VERSION 5.8 ;
BUSBITCHARS "[]" ;
DIVIDERCHAR "/" ;
UNITS
    DATABASE MICRONS 1000 ;
END UNITS

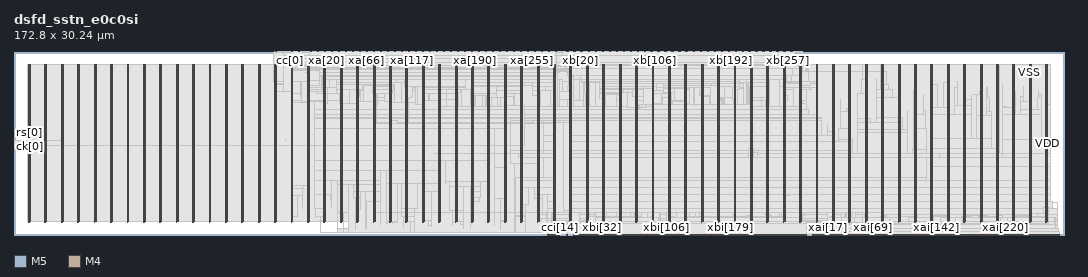
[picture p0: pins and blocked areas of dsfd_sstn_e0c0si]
MACRO dsfd_sstn_e0c0si
  FOREIGN dsfd_sstn_e0c0si 0 0 ;
  CLASS BLOCK ;
  SIZE 172.8 BY 30.24 ;
  PIN c0[0]
    DIRECTION INPUT ;
    USE SIGNAL ;
    PORT
      LAYER M5 ;
        RECT  44.208 30.156 44.232 30.24 ;
    END
  END c0[0]
  PIN c0[1]
    DIRECTION INPUT ;
    USE SIGNAL ;
    PORT
      LAYER M5 ;
        RECT  44.352 30.156 44.376 30.24 ;
    END
  END c0[1]
  PIN cc[0]
    DIRECTION OUTPUT ;
    USE SIGNAL ;
    PORT
      LAYER M5 ;
        RECT  45.456 30.156 45.48 30.24 ;
    END
  END cc[0]
  PIN cc[10]
    DIRECTION OUTPUT ;
    USE SIGNAL ;
    PORT
      LAYER M5 ;
        RECT  46.896 30.156 46.92 30.24 ;
    END
  END cc[10]
  PIN cc[11]
    DIRECTION OUTPUT ;
    USE SIGNAL ;
    PORT
      LAYER M5 ;
        RECT  47.04 30.156 47.064 30.24 ;
    END
  END cc[11]
  PIN cc[12]
    DIRECTION OUTPUT ;
    USE SIGNAL ;
    PORT
      LAYER M5 ;
        RECT  47.184 30.156 47.208 30.24 ;
    END
  END cc[12]
  PIN cc[13]
    DIRECTION OUTPUT ;
    USE SIGNAL ;
    PORT
      LAYER M5 ;
        RECT  47.328 30.156 47.352 30.24 ;
    END
  END cc[13]
  PIN cc[14]
    DIRECTION OUTPUT ;
    USE SIGNAL ;
    PORT
      LAYER M5 ;
        RECT  47.472 30.156 47.496 30.24 ;
    END
  END cc[14]
  PIN cc[1]
    DIRECTION OUTPUT ;
    USE SIGNAL ;
    PORT
      LAYER M5 ;
        RECT  45.6 30.156 45.624 30.24 ;
    END
  END cc[1]
  PIN cc[2]
    DIRECTION OUTPUT ;
    USE SIGNAL ;
    PORT
      LAYER M5 ;
        RECT  45.744 30.156 45.768 30.24 ;
    END
  END cc[2]
  PIN cc[3]
    DIRECTION OUTPUT ;
    USE SIGNAL ;
    PORT
      LAYER M5 ;
        RECT  45.888 30.156 45.912 30.24 ;
    END
  END cc[3]
  PIN cc[4]
    DIRECTION OUTPUT ;
    USE SIGNAL ;
    PORT
      LAYER M5 ;
        RECT  46.032 30.156 46.056 30.24 ;
    END
  END cc[4]
  PIN cc[5]
    DIRECTION OUTPUT ;
    USE SIGNAL ;
    PORT
      LAYER M5 ;
        RECT  46.176 30.156 46.2 30.24 ;
    END
  END cc[5]
  PIN cc[6]
    DIRECTION OUTPUT ;
    USE SIGNAL ;
    PORT
      LAYER M5 ;
        RECT  46.32 30.156 46.344 30.24 ;
    END
  END cc[6]
  PIN cc[7]
    DIRECTION OUTPUT ;
    USE SIGNAL ;
    PORT
      LAYER M5 ;
        RECT  46.464 30.156 46.488 30.24 ;
    END
  END cc[7]
  PIN cc[8]
    DIRECTION OUTPUT ;
    USE SIGNAL ;
    PORT
      LAYER M5 ;
        RECT  46.608 30.156 46.632 30.24 ;
    END
  END cc[8]
  PIN cc[9]
    DIRECTION OUTPUT ;
    USE SIGNAL ;
    PORT
      LAYER M5 ;
        RECT  46.752 30.156 46.776 30.24 ;
    END
  END cc[9]
  PIN cci[0]
    DIRECTION INPUT ;
    USE SIGNAL ;
    PORT
      LAYER M5 ;
        RECT  87.792 0 87.816 0.084 ;
    END
  END cci[0]
  PIN cci[10]
    DIRECTION INPUT ;
    USE SIGNAL ;
    PORT
      LAYER M5 ;
        RECT  89.232 0 89.256 0.084 ;
    END
  END cci[10]
  PIN cci[11]
    DIRECTION INPUT ;
    USE SIGNAL ;
    PORT
      LAYER M5 ;
        RECT  89.376 0 89.4 0.084 ;
    END
  END cci[11]
  PIN cci[12]
    DIRECTION INPUT ;
    USE SIGNAL ;
    PORT
      LAYER M5 ;
        RECT  89.52 0 89.544 0.084 ;
    END
  END cci[12]
  PIN cci[13]
    DIRECTION INPUT ;
    USE SIGNAL ;
    PORT
      LAYER M5 ;
        RECT  89.664 0 89.688 0.084 ;
    END
  END cci[13]
  PIN cci[14]
    DIRECTION INPUT ;
    USE SIGNAL ;
    PORT
      LAYER M5 ;
        RECT  89.808 0 89.832 0.084 ;
    END
  END cci[14]
  PIN cci[1]
    DIRECTION INPUT ;
    USE SIGNAL ;
    PORT
      LAYER M5 ;
        RECT  87.936 0 87.96 0.084 ;
    END
  END cci[1]
  PIN cci[2]
    DIRECTION INPUT ;
    USE SIGNAL ;
    PORT
      LAYER M5 ;
        RECT  88.08 0 88.104 0.084 ;
    END
  END cci[2]
  PIN cci[3]
    DIRECTION INPUT ;
    USE SIGNAL ;
    PORT
      LAYER M5 ;
        RECT  88.224 0 88.248 0.084 ;
    END
  END cci[3]
  PIN cci[4]
    DIRECTION INPUT ;
    USE SIGNAL ;
    PORT
      LAYER M5 ;
        RECT  88.368 0 88.392 0.084 ;
    END
  END cci[4]
  PIN cci[5]
    DIRECTION INPUT ;
    USE SIGNAL ;
    PORT
      LAYER M5 ;
        RECT  88.512 0 88.536 0.084 ;
    END
  END cci[5]
  PIN cci[6]
    DIRECTION INPUT ;
    USE SIGNAL ;
    PORT
      LAYER M5 ;
        RECT  88.656 0 88.68 0.084 ;
    END
  END cci[6]
  PIN cci[7]
    DIRECTION INPUT ;
    USE SIGNAL ;
    PORT
      LAYER M5 ;
        RECT  88.8 0 88.824 0.084 ;
    END
  END cci[7]
  PIN cci[8]
    DIRECTION INPUT ;
    USE SIGNAL ;
    PORT
      LAYER M5 ;
        RECT  88.944 0 88.968 0.084 ;
    END
  END cci[8]
  PIN cci[9]
    DIRECTION INPUT ;
    USE SIGNAL ;
    PORT
      LAYER M5 ;
        RECT  89.088 0 89.112 0.084 ;
    END
  END cci[9]
  PIN ck[0]
    DIRECTION INPUT ;
    USE SIGNAL ;
    PORT
      LAYER M4 ;
        RECT  0 14.592 0.084 14.616 ;
    END
    PORT
      LAYER M4 ;
        RECT  0.06 14.592 0.097 14.616 ;
    END
  END ck[0]
  PIN e0[0]
    DIRECTION INPUT ;
    USE SIGNAL ;
    PORT
      LAYER M5 ;
        RECT  42.96 30.156 42.984 30.24 ;
    END
  END e0[0]
  PIN e0[1]
    DIRECTION INPUT ;
    USE SIGNAL ;
    PORT
      LAYER M5 ;
        RECT  43.104 30.156 43.128 30.24 ;
    END
  END e0[1]
  PIN rs[0]
    DIRECTION INPUT ;
    USE SIGNAL ;
    PORT
      LAYER M4 ;
        RECT  0 15.6 0.084 15.624 ;
    END
    PORT
      LAYER M4 ;
        RECT  0.06 15.6 0.097 15.624 ;
    END
  END rs[0]
  PIN si[0]
    DIRECTION INPUT ;
    USE SIGNAL ;
    PORT
      LAYER M5 ;
        RECT  129.552 30.156 129.576 30.24 ;
    END
  END si[0]
  PIN si[1]
    DIRECTION INPUT ;
    USE SIGNAL ;
    PORT
      LAYER M5 ;
        RECT  129.696 30.156 129.72 30.24 ;
    END
  END si[1]
  PIN so[0]
    DIRECTION OUTPUT ;
    USE SIGNAL ;
    PORT
      LAYER M5 ;
        RECT  90.912 0 90.936 0.084 ;
    END
  END so[0]
  PIN so[1]
    DIRECTION OUTPUT ;
    USE SIGNAL ;
    PORT
      LAYER M5 ;
        RECT  91.056 0 91.08 0.084 ;
    END
  END so[1]
  PIN xa[0]
    DIRECTION OUTPUT ;
    USE SIGNAL ;
    PORT
      LAYER M5 ;
        RECT  48.576 30.156 48.6 30.24 ;
    END
  END xa[0]
  PIN xa[100]
    DIRECTION OUTPUT ;
    USE SIGNAL ;
    PORT
      LAYER M5 ;
        RECT  62.976 30.156 63 30.24 ;
    END
  END xa[100]
  PIN xa[101]
    DIRECTION OUTPUT ;
    USE SIGNAL ;
    PORT
      LAYER M5 ;
        RECT  63.12 30.156 63.144 30.24 ;
    END
  END xa[101]
  PIN xa[102]
    DIRECTION OUTPUT ;
    USE SIGNAL ;
    PORT
      LAYER M5 ;
        RECT  63.264 30.156 63.288 30.24 ;
    END
  END xa[102]
  PIN xa[103]
    DIRECTION OUTPUT ;
    USE SIGNAL ;
    PORT
      LAYER M5 ;
        RECT  63.408 30.156 63.432 30.24 ;
    END
  END xa[103]
  PIN xa[104]
    DIRECTION OUTPUT ;
    USE SIGNAL ;
    PORT
      LAYER M5 ;
        RECT  63.552 30.156 63.576 30.24 ;
    END
  END xa[104]
  PIN xa[105]
    DIRECTION OUTPUT ;
    USE SIGNAL ;
    PORT
      LAYER M5 ;
        RECT  63.696 30.156 63.72 30.24 ;
    END
  END xa[105]
  PIN xa[106]
    DIRECTION OUTPUT ;
    USE SIGNAL ;
    PORT
      LAYER M5 ;
        RECT  63.84 30.156 63.864 30.24 ;
    END
  END xa[106]
  PIN xa[107]
    DIRECTION OUTPUT ;
    USE SIGNAL ;
    PORT
      LAYER M5 ;
        RECT  63.984 30.156 64.008 30.24 ;
    END
  END xa[107]
  PIN xa[108]
    DIRECTION OUTPUT ;
    USE SIGNAL ;
    PORT
      LAYER M5 ;
        RECT  64.128 30.156 64.152 30.24 ;
    END
  END xa[108]
  PIN xa[109]
    DIRECTION OUTPUT ;
    USE SIGNAL ;
    PORT
      LAYER M5 ;
        RECT  64.272 30.156 64.296 30.24 ;
    END
  END xa[109]
  PIN xa[10]
    DIRECTION OUTPUT ;
    USE SIGNAL ;
    PORT
      LAYER M5 ;
        RECT  50.016 30.156 50.04 30.24 ;
    END
  END xa[10]
  PIN xa[110]
    DIRECTION OUTPUT ;
    USE SIGNAL ;
    PORT
      LAYER M5 ;
        RECT  64.416 30.156 64.44 30.24 ;
    END
  END xa[110]
  PIN xa[111]
    DIRECTION OUTPUT ;
    USE SIGNAL ;
    PORT
      LAYER M5 ;
        RECT  64.56 30.156 64.584 30.24 ;
    END
  END xa[111]
  PIN xa[112]
    DIRECTION OUTPUT ;
    USE SIGNAL ;
    PORT
      LAYER M5 ;
        RECT  64.704 30.156 64.728 30.24 ;
    END
  END xa[112]
  PIN xa[113]
    DIRECTION OUTPUT ;
    USE SIGNAL ;
    PORT
      LAYER M5 ;
        RECT  64.848 30.156 64.872 30.24 ;
    END
  END xa[113]
  PIN xa[114]
    DIRECTION OUTPUT ;
    USE SIGNAL ;
    PORT
      LAYER M5 ;
        RECT  64.992 30.156 65.016 30.24 ;
    END
  END xa[114]
  PIN xa[115]
    DIRECTION OUTPUT ;
    USE SIGNAL ;
    PORT
      LAYER M5 ;
        RECT  65.136 30.156 65.16 30.24 ;
    END
  END xa[115]
  PIN xa[116]
    DIRECTION OUTPUT ;
    USE SIGNAL ;
    PORT
      LAYER M5 ;
        RECT  65.28 30.156 65.304 30.24 ;
    END
  END xa[116]
  PIN xa[117]
    DIRECTION OUTPUT ;
    USE SIGNAL ;
    PORT
      LAYER M5 ;
        RECT  65.424 30.156 65.448 30.24 ;
    END
  END xa[117]
  PIN xa[118]
    DIRECTION OUTPUT ;
    USE SIGNAL ;
    PORT
      LAYER M5 ;
        RECT  65.568 30.156 65.592 30.24 ;
    END
  END xa[118]
  PIN xa[119]
    DIRECTION OUTPUT ;
    USE SIGNAL ;
    PORT
      LAYER M5 ;
        RECT  65.712 30.156 65.736 30.24 ;
    END
  END xa[119]
  PIN xa[11]
    DIRECTION OUTPUT ;
    USE SIGNAL ;
    PORT
      LAYER M5 ;
        RECT  50.16 30.156 50.184 30.24 ;
    END
  END xa[11]
  PIN xa[120]
    DIRECTION OUTPUT ;
    USE SIGNAL ;
    PORT
      LAYER M5 ;
        RECT  65.856 30.156 65.88 30.24 ;
    END
  END xa[120]
  PIN xa[121]
    DIRECTION OUTPUT ;
    USE SIGNAL ;
    PORT
      LAYER M5 ;
        RECT  66 30.156 66.024 30.24 ;
    END
  END xa[121]
  PIN xa[122]
    DIRECTION OUTPUT ;
    USE SIGNAL ;
    PORT
      LAYER M5 ;
        RECT  66.144 30.156 66.168 30.24 ;
    END
  END xa[122]
  PIN xa[123]
    DIRECTION OUTPUT ;
    USE SIGNAL ;
    PORT
      LAYER M5 ;
        RECT  66.288 30.156 66.312 30.24 ;
    END
  END xa[123]
  PIN xa[124]
    DIRECTION OUTPUT ;
    USE SIGNAL ;
    PORT
      LAYER M5 ;
        RECT  66.432 30.156 66.456 30.24 ;
    END
  END xa[124]
  PIN xa[125]
    DIRECTION OUTPUT ;
    USE SIGNAL ;
    PORT
      LAYER M5 ;
        RECT  66.576 30.156 66.6 30.24 ;
    END
  END xa[125]
  PIN xa[126]
    DIRECTION OUTPUT ;
    USE SIGNAL ;
    PORT
      LAYER M5 ;
        RECT  66.72 30.156 66.744 30.24 ;
    END
  END xa[126]
  PIN xa[127]
    DIRECTION OUTPUT ;
    USE SIGNAL ;
    PORT
      LAYER M5 ;
        RECT  66.864 30.156 66.888 30.24 ;
    END
  END xa[127]
  PIN xa[128]
    DIRECTION OUTPUT ;
    USE SIGNAL ;
    PORT
      LAYER M5 ;
        RECT  67.008 30.156 67.032 30.24 ;
    END
  END xa[128]
  PIN xa[129]
    DIRECTION OUTPUT ;
    USE SIGNAL ;
    PORT
      LAYER M5 ;
        RECT  67.152 30.156 67.176 30.24 ;
    END
  END xa[129]
  PIN xa[12]
    DIRECTION OUTPUT ;
    USE SIGNAL ;
    PORT
      LAYER M5 ;
        RECT  50.304 30.156 50.328 30.24 ;
    END
  END xa[12]
  PIN xa[130]
    DIRECTION OUTPUT ;
    USE SIGNAL ;
    PORT
      LAYER M5 ;
        RECT  67.296 30.156 67.32 30.24 ;
    END
  END xa[130]
  PIN xa[131]
    DIRECTION OUTPUT ;
    USE SIGNAL ;
    PORT
      LAYER M5 ;
        RECT  67.44 30.156 67.464 30.24 ;
    END
  END xa[131]
  PIN xa[132]
    DIRECTION OUTPUT ;
    USE SIGNAL ;
    PORT
      LAYER M5 ;
        RECT  67.584 30.156 67.608 30.24 ;
    END
  END xa[132]
  PIN xa[133]
    DIRECTION OUTPUT ;
    USE SIGNAL ;
    PORT
      LAYER M5 ;
        RECT  67.728 30.156 67.752 30.24 ;
    END
  END xa[133]
  PIN xa[134]
    DIRECTION OUTPUT ;
    USE SIGNAL ;
    PORT
      LAYER M5 ;
        RECT  67.872 30.156 67.896 30.24 ;
    END
  END xa[134]
  PIN xa[135]
    DIRECTION OUTPUT ;
    USE SIGNAL ;
    PORT
      LAYER M5 ;
        RECT  68.016 30.156 68.04 30.24 ;
    END
  END xa[135]
  PIN xa[136]
    DIRECTION OUTPUT ;
    USE SIGNAL ;
    PORT
      LAYER M5 ;
        RECT  68.16 30.156 68.184 30.24 ;
    END
  END xa[136]
  PIN xa[137]
    DIRECTION OUTPUT ;
    USE SIGNAL ;
    PORT
      LAYER M5 ;
        RECT  68.304 30.156 68.328 30.24 ;
    END
  END xa[137]
  PIN xa[138]
    DIRECTION OUTPUT ;
    USE SIGNAL ;
    PORT
      LAYER M5 ;
        RECT  68.448 30.156 68.472 30.24 ;
    END
  END xa[138]
  PIN xa[139]
    DIRECTION OUTPUT ;
    USE SIGNAL ;
    PORT
      LAYER M5 ;
        RECT  68.592 30.156 68.616 30.24 ;
    END
  END xa[139]
  PIN xa[13]
    DIRECTION OUTPUT ;
    USE SIGNAL ;
    PORT
      LAYER M5 ;
        RECT  50.448 30.156 50.472 30.24 ;
    END
  END xa[13]
  PIN xa[140]
    DIRECTION OUTPUT ;
    USE SIGNAL ;
    PORT
      LAYER M5 ;
        RECT  68.736 30.156 68.76 30.24 ;
    END
  END xa[140]
  PIN xa[141]
    DIRECTION OUTPUT ;
    USE SIGNAL ;
    PORT
      LAYER M5 ;
        RECT  68.88 30.156 68.904 30.24 ;
    END
  END xa[141]
  PIN xa[142]
    DIRECTION OUTPUT ;
    USE SIGNAL ;
    PORT
      LAYER M5 ;
        RECT  69.024 30.156 69.048 30.24 ;
    END
  END xa[142]
  PIN xa[143]
    DIRECTION OUTPUT ;
    USE SIGNAL ;
    PORT
      LAYER M5 ;
        RECT  69.168 30.156 69.192 30.24 ;
    END
  END xa[143]
  PIN xa[144]
    DIRECTION OUTPUT ;
    USE SIGNAL ;
    PORT
      LAYER M5 ;
        RECT  69.312 30.156 69.336 30.24 ;
    END
  END xa[144]
  PIN xa[145]
    DIRECTION OUTPUT ;
    USE SIGNAL ;
    PORT
      LAYER M5 ;
        RECT  69.456 30.156 69.48 30.24 ;
    END
  END xa[145]
  PIN xa[146]
    DIRECTION OUTPUT ;
    USE SIGNAL ;
    PORT
      LAYER M5 ;
        RECT  69.6 30.156 69.624 30.24 ;
    END
  END xa[146]
  PIN xa[147]
    DIRECTION OUTPUT ;
    USE SIGNAL ;
    PORT
      LAYER M5 ;
        RECT  69.744 30.156 69.768 30.24 ;
    END
  END xa[147]
  PIN xa[148]
    DIRECTION OUTPUT ;
    USE SIGNAL ;
    PORT
      LAYER M5 ;
        RECT  69.888 30.156 69.912 30.24 ;
    END
  END xa[148]
  PIN xa[149]
    DIRECTION OUTPUT ;
    USE SIGNAL ;
    PORT
      LAYER M5 ;
        RECT  70.032 30.156 70.056 30.24 ;
    END
  END xa[149]
  PIN xa[14]
    DIRECTION OUTPUT ;
    USE SIGNAL ;
    PORT
      LAYER M5 ;
        RECT  50.592 30.156 50.616 30.24 ;
    END
  END xa[14]
  PIN xa[150]
    DIRECTION OUTPUT ;
    USE SIGNAL ;
    PORT
      LAYER M5 ;
        RECT  70.176 30.156 70.2 30.24 ;
    END
  END xa[150]
  PIN xa[151]
    DIRECTION OUTPUT ;
    USE SIGNAL ;
    PORT
      LAYER M5 ;
        RECT  70.32 30.156 70.344 30.24 ;
    END
  END xa[151]
  PIN xa[152]
    DIRECTION OUTPUT ;
    USE SIGNAL ;
    PORT
      LAYER M5 ;
        RECT  70.464 30.156 70.488 30.24 ;
    END
  END xa[152]
  PIN xa[153]
    DIRECTION OUTPUT ;
    USE SIGNAL ;
    PORT
      LAYER M5 ;
        RECT  70.608 30.156 70.632 30.24 ;
    END
  END xa[153]
  PIN xa[154]
    DIRECTION OUTPUT ;
    USE SIGNAL ;
    PORT
      LAYER M5 ;
        RECT  70.752 30.156 70.776 30.24 ;
    END
  END xa[154]
  PIN xa[155]
    DIRECTION OUTPUT ;
    USE SIGNAL ;
    PORT
      LAYER M5 ;
        RECT  70.896 30.156 70.92 30.24 ;
    END
  END xa[155]
  PIN xa[156]
    DIRECTION OUTPUT ;
    USE SIGNAL ;
    PORT
      LAYER M5 ;
        RECT  71.04 30.156 71.064 30.24 ;
    END
  END xa[156]
  PIN xa[157]
    DIRECTION OUTPUT ;
    USE SIGNAL ;
    PORT
      LAYER M5 ;
        RECT  71.184 30.156 71.208 30.24 ;
    END
  END xa[157]
  PIN xa[158]
    DIRECTION OUTPUT ;
    USE SIGNAL ;
    PORT
      LAYER M5 ;
        RECT  71.328 30.156 71.352 30.24 ;
    END
  END xa[158]
  PIN xa[159]
    DIRECTION OUTPUT ;
    USE SIGNAL ;
    PORT
      LAYER M5 ;
        RECT  71.472 30.156 71.496 30.24 ;
    END
  END xa[159]
  PIN xa[15]
    DIRECTION OUTPUT ;
    USE SIGNAL ;
    PORT
      LAYER M5 ;
        RECT  50.736 30.156 50.76 30.24 ;
    END
  END xa[15]
  PIN xa[160]
    DIRECTION OUTPUT ;
    USE SIGNAL ;
    PORT
      LAYER M5 ;
        RECT  71.616 30.156 71.64 30.24 ;
    END
  END xa[160]
  PIN xa[161]
    DIRECTION OUTPUT ;
    USE SIGNAL ;
    PORT
      LAYER M5 ;
        RECT  71.76 30.156 71.784 30.24 ;
    END
  END xa[161]
  PIN xa[162]
    DIRECTION OUTPUT ;
    USE SIGNAL ;
    PORT
      LAYER M5 ;
        RECT  71.904 30.156 71.928 30.24 ;
    END
  END xa[162]
  PIN xa[163]
    DIRECTION OUTPUT ;
    USE SIGNAL ;
    PORT
      LAYER M5 ;
        RECT  72.048 30.156 72.072 30.24 ;
    END
  END xa[163]
  PIN xa[164]
    DIRECTION OUTPUT ;
    USE SIGNAL ;
    PORT
      LAYER M5 ;
        RECT  72.192 30.156 72.216 30.24 ;
    END
  END xa[164]
  PIN xa[165]
    DIRECTION OUTPUT ;
    USE SIGNAL ;
    PORT
      LAYER M5 ;
        RECT  72.336 30.156 72.36 30.24 ;
    END
  END xa[165]
  PIN xa[166]
    DIRECTION OUTPUT ;
    USE SIGNAL ;
    PORT
      LAYER M5 ;
        RECT  72.48 30.156 72.504 30.24 ;
    END
  END xa[166]
  PIN xa[167]
    DIRECTION OUTPUT ;
    USE SIGNAL ;
    PORT
      LAYER M5 ;
        RECT  72.624 30.156 72.648 30.24 ;
    END
  END xa[167]
  PIN xa[168]
    DIRECTION OUTPUT ;
    USE SIGNAL ;
    PORT
      LAYER M5 ;
        RECT  72.768 30.156 72.792 30.24 ;
    END
  END xa[168]
  PIN xa[169]
    DIRECTION OUTPUT ;
    USE SIGNAL ;
    PORT
      LAYER M5 ;
        RECT  72.912 30.156 72.936 30.24 ;
    END
  END xa[169]
  PIN xa[16]
    DIRECTION OUTPUT ;
    USE SIGNAL ;
    PORT
      LAYER M5 ;
        RECT  50.88 30.156 50.904 30.24 ;
    END
  END xa[16]
  PIN xa[170]
    DIRECTION OUTPUT ;
    USE SIGNAL ;
    PORT
      LAYER M5 ;
        RECT  73.056 30.156 73.08 30.24 ;
    END
  END xa[170]
  PIN xa[171]
    DIRECTION OUTPUT ;
    USE SIGNAL ;
    PORT
      LAYER M5 ;
        RECT  73.2 30.156 73.224 30.24 ;
    END
  END xa[171]
  PIN xa[172]
    DIRECTION OUTPUT ;
    USE SIGNAL ;
    PORT
      LAYER M5 ;
        RECT  73.344 30.156 73.368 30.24 ;
    END
  END xa[172]
  PIN xa[173]
    DIRECTION OUTPUT ;
    USE SIGNAL ;
    PORT
      LAYER M5 ;
        RECT  73.488 30.156 73.512 30.24 ;
    END
  END xa[173]
  PIN xa[174]
    DIRECTION OUTPUT ;
    USE SIGNAL ;
    PORT
      LAYER M5 ;
        RECT  73.632 30.156 73.656 30.24 ;
    END
  END xa[174]
  PIN xa[175]
    DIRECTION OUTPUT ;
    USE SIGNAL ;
    PORT
      LAYER M5 ;
        RECT  73.776 30.156 73.8 30.24 ;
    END
  END xa[175]
  PIN xa[176]
    DIRECTION OUTPUT ;
    USE SIGNAL ;
    PORT
      LAYER M5 ;
        RECT  73.92 30.156 73.944 30.24 ;
    END
  END xa[176]
  PIN xa[177]
    DIRECTION OUTPUT ;
    USE SIGNAL ;
    PORT
      LAYER M5 ;
        RECT  74.064 30.156 74.088 30.24 ;
    END
  END xa[177]
  PIN xa[178]
    DIRECTION OUTPUT ;
    USE SIGNAL ;
    PORT
      LAYER M5 ;
        RECT  74.208 30.156 74.232 30.24 ;
    END
  END xa[178]
  PIN xa[179]
    DIRECTION OUTPUT ;
    USE SIGNAL ;
    PORT
      LAYER M5 ;
        RECT  74.352 30.156 74.376 30.24 ;
    END
  END xa[179]
  PIN xa[17]
    DIRECTION OUTPUT ;
    USE SIGNAL ;
    PORT
      LAYER M5 ;
        RECT  51.024 30.156 51.048 30.24 ;
    END
  END xa[17]
  PIN xa[180]
    DIRECTION OUTPUT ;
    USE SIGNAL ;
    PORT
      LAYER M5 ;
        RECT  74.496 30.156 74.52 30.24 ;
    END
  END xa[180]
  PIN xa[181]
    DIRECTION OUTPUT ;
    USE SIGNAL ;
    PORT
      LAYER M5 ;
        RECT  74.64 30.156 74.664 30.24 ;
    END
  END xa[181]
  PIN xa[182]
    DIRECTION OUTPUT ;
    USE SIGNAL ;
    PORT
      LAYER M5 ;
        RECT  74.784 30.156 74.808 30.24 ;
    END
  END xa[182]
  PIN xa[183]
    DIRECTION OUTPUT ;
    USE SIGNAL ;
    PORT
      LAYER M5 ;
        RECT  74.928 30.156 74.952 30.24 ;
    END
  END xa[183]
  PIN xa[184]
    DIRECTION OUTPUT ;
    USE SIGNAL ;
    PORT
      LAYER M5 ;
        RECT  75.072 30.156 75.096 30.24 ;
    END
  END xa[184]
  PIN xa[185]
    DIRECTION OUTPUT ;
    USE SIGNAL ;
    PORT
      LAYER M5 ;
        RECT  75.216 30.156 75.24 30.24 ;
    END
  END xa[185]
  PIN xa[186]
    DIRECTION OUTPUT ;
    USE SIGNAL ;
    PORT
      LAYER M5 ;
        RECT  75.36 30.156 75.384 30.24 ;
    END
  END xa[186]
  PIN xa[187]
    DIRECTION OUTPUT ;
    USE SIGNAL ;
    PORT
      LAYER M5 ;
        RECT  75.504 30.156 75.528 30.24 ;
    END
  END xa[187]
  PIN xa[188]
    DIRECTION OUTPUT ;
    USE SIGNAL ;
    PORT
      LAYER M5 ;
        RECT  75.648 30.156 75.672 30.24 ;
    END
  END xa[188]
  PIN xa[189]
    DIRECTION OUTPUT ;
    USE SIGNAL ;
    PORT
      LAYER M5 ;
        RECT  75.792 30.156 75.816 30.24 ;
    END
  END xa[189]
  PIN xa[18]
    DIRECTION OUTPUT ;
    USE SIGNAL ;
    PORT
      LAYER M5 ;
        RECT  51.168 30.156 51.192 30.24 ;
    END
  END xa[18]
  PIN xa[190]
    DIRECTION OUTPUT ;
    USE SIGNAL ;
    PORT
      LAYER M5 ;
        RECT  75.936 30.156 75.96 30.24 ;
    END
  END xa[190]
  PIN xa[191]
    DIRECTION OUTPUT ;
    USE SIGNAL ;
    PORT
      LAYER M5 ;
        RECT  76.08 30.156 76.104 30.24 ;
    END
  END xa[191]
  PIN xa[192]
    DIRECTION OUTPUT ;
    USE SIGNAL ;
    PORT
      LAYER M5 ;
        RECT  76.224 30.156 76.248 30.24 ;
    END
  END xa[192]
  PIN xa[193]
    DIRECTION OUTPUT ;
    USE SIGNAL ;
    PORT
      LAYER M5 ;
        RECT  76.368 30.156 76.392 30.24 ;
    END
  END xa[193]
  PIN xa[194]
    DIRECTION OUTPUT ;
    USE SIGNAL ;
    PORT
      LAYER M5 ;
        RECT  76.512 30.156 76.536 30.24 ;
    END
  END xa[194]
  PIN xa[195]
    DIRECTION OUTPUT ;
    USE SIGNAL ;
    PORT
      LAYER M5 ;
        RECT  76.656 30.156 76.68 30.24 ;
    END
  END xa[195]
  PIN xa[196]
    DIRECTION OUTPUT ;
    USE SIGNAL ;
    PORT
      LAYER M5 ;
        RECT  76.8 30.156 76.824 30.24 ;
    END
  END xa[196]
  PIN xa[197]
    DIRECTION OUTPUT ;
    USE SIGNAL ;
    PORT
      LAYER M5 ;
        RECT  76.944 30.156 76.968 30.24 ;
    END
  END xa[197]
  PIN xa[198]
    DIRECTION OUTPUT ;
    USE SIGNAL ;
    PORT
      LAYER M5 ;
        RECT  77.088 30.156 77.112 30.24 ;
    END
  END xa[198]
  PIN xa[199]
    DIRECTION OUTPUT ;
    USE SIGNAL ;
    PORT
      LAYER M5 ;
        RECT  77.232 30.156 77.256 30.24 ;
    END
  END xa[199]
  PIN xa[19]
    DIRECTION OUTPUT ;
    USE SIGNAL ;
    PORT
      LAYER M5 ;
        RECT  51.312 30.156 51.336 30.24 ;
    END
  END xa[19]
  PIN xa[1]
    DIRECTION OUTPUT ;
    USE SIGNAL ;
    PORT
      LAYER M5 ;
        RECT  48.72 30.156 48.744 30.24 ;
    END
  END xa[1]
  PIN xa[200]
    DIRECTION OUTPUT ;
    USE SIGNAL ;
    PORT
      LAYER M5 ;
        RECT  77.376 30.156 77.4 30.24 ;
    END
  END xa[200]
  PIN xa[201]
    DIRECTION OUTPUT ;
    USE SIGNAL ;
    PORT
      LAYER M5 ;
        RECT  77.52 30.156 77.544 30.24 ;
    END
  END xa[201]
  PIN xa[202]
    DIRECTION OUTPUT ;
    USE SIGNAL ;
    PORT
      LAYER M5 ;
        RECT  77.664 30.156 77.688 30.24 ;
    END
  END xa[202]
  PIN xa[203]
    DIRECTION OUTPUT ;
    USE SIGNAL ;
    PORT
      LAYER M5 ;
        RECT  77.808 30.156 77.832 30.24 ;
    END
  END xa[203]
  PIN xa[204]
    DIRECTION OUTPUT ;
    USE SIGNAL ;
    PORT
      LAYER M5 ;
        RECT  77.952 30.156 77.976 30.24 ;
    END
  END xa[204]
  PIN xa[205]
    DIRECTION OUTPUT ;
    USE SIGNAL ;
    PORT
      LAYER M5 ;
        RECT  78.096 30.156 78.12 30.24 ;
    END
  END xa[205]
  PIN xa[206]
    DIRECTION OUTPUT ;
    USE SIGNAL ;
    PORT
      LAYER M5 ;
        RECT  78.24 30.156 78.264 30.24 ;
    END
  END xa[206]
  PIN xa[207]
    DIRECTION OUTPUT ;
    USE SIGNAL ;
    PORT
      LAYER M5 ;
        RECT  78.384 30.156 78.408 30.24 ;
    END
  END xa[207]
  PIN xa[208]
    DIRECTION OUTPUT ;
    USE SIGNAL ;
    PORT
      LAYER M5 ;
        RECT  78.528 30.156 78.552 30.24 ;
    END
  END xa[208]
  PIN xa[209]
    DIRECTION OUTPUT ;
    USE SIGNAL ;
    PORT
      LAYER M5 ;
        RECT  78.672 30.156 78.696 30.24 ;
    END
  END xa[209]
  PIN xa[20]
    DIRECTION OUTPUT ;
    USE SIGNAL ;
    PORT
      LAYER M5 ;
        RECT  51.456 30.156 51.48 30.24 ;
    END
  END xa[20]
  PIN xa[210]
    DIRECTION OUTPUT ;
    USE SIGNAL ;
    PORT
      LAYER M5 ;
        RECT  78.816 30.156 78.84 30.24 ;
    END
  END xa[210]
  PIN xa[211]
    DIRECTION OUTPUT ;
    USE SIGNAL ;
    PORT
      LAYER M5 ;
        RECT  78.96 30.156 78.984 30.24 ;
    END
  END xa[211]
  PIN xa[212]
    DIRECTION OUTPUT ;
    USE SIGNAL ;
    PORT
      LAYER M5 ;
        RECT  79.104 30.156 79.128 30.24 ;
    END
  END xa[212]
  PIN xa[213]
    DIRECTION OUTPUT ;
    USE SIGNAL ;
    PORT
      LAYER M5 ;
        RECT  79.248 30.156 79.272 30.24 ;
    END
  END xa[213]
  PIN xa[214]
    DIRECTION OUTPUT ;
    USE SIGNAL ;
    PORT
      LAYER M5 ;
        RECT  79.392 30.156 79.416 30.24 ;
    END
  END xa[214]
  PIN xa[215]
    DIRECTION OUTPUT ;
    USE SIGNAL ;
    PORT
      LAYER M5 ;
        RECT  79.536 30.156 79.56 30.24 ;
    END
  END xa[215]
  PIN xa[216]
    DIRECTION OUTPUT ;
    USE SIGNAL ;
    PORT
      LAYER M5 ;
        RECT  79.68 30.156 79.704 30.24 ;
    END
  END xa[216]
  PIN xa[217]
    DIRECTION OUTPUT ;
    USE SIGNAL ;
    PORT
      LAYER M5 ;
        RECT  79.824 30.156 79.848 30.24 ;
    END
  END xa[217]
  PIN xa[218]
    DIRECTION OUTPUT ;
    USE SIGNAL ;
    PORT
      LAYER M5 ;
        RECT  79.968 30.156 79.992 30.24 ;
    END
  END xa[218]
  PIN xa[219]
    DIRECTION OUTPUT ;
    USE SIGNAL ;
    PORT
      LAYER M5 ;
        RECT  80.112 30.156 80.136 30.24 ;
    END
  END xa[219]
  PIN xa[21]
    DIRECTION OUTPUT ;
    USE SIGNAL ;
    PORT
      LAYER M5 ;
        RECT  51.6 30.156 51.624 30.24 ;
    END
  END xa[21]
  PIN xa[220]
    DIRECTION OUTPUT ;
    USE SIGNAL ;
    PORT
      LAYER M5 ;
        RECT  80.256 30.156 80.28 30.24 ;
    END
  END xa[220]
  PIN xa[221]
    DIRECTION OUTPUT ;
    USE SIGNAL ;
    PORT
      LAYER M5 ;
        RECT  80.4 30.156 80.424 30.24 ;
    END
  END xa[221]
  PIN xa[222]
    DIRECTION OUTPUT ;
    USE SIGNAL ;
    PORT
      LAYER M5 ;
        RECT  80.544 30.156 80.568 30.24 ;
    END
  END xa[222]
  PIN xa[223]
    DIRECTION OUTPUT ;
    USE SIGNAL ;
    PORT
      LAYER M5 ;
        RECT  80.688 30.156 80.712 30.24 ;
    END
  END xa[223]
  PIN xa[224]
    DIRECTION OUTPUT ;
    USE SIGNAL ;
    PORT
      LAYER M5 ;
        RECT  80.832 30.156 80.856 30.24 ;
    END
  END xa[224]
  PIN xa[225]
    DIRECTION OUTPUT ;
    USE SIGNAL ;
    PORT
      LAYER M5 ;
        RECT  80.976 30.156 81 30.24 ;
    END
  END xa[225]
  PIN xa[226]
    DIRECTION OUTPUT ;
    USE SIGNAL ;
    PORT
      LAYER M5 ;
        RECT  81.12 30.156 81.144 30.24 ;
    END
  END xa[226]
  PIN xa[227]
    DIRECTION OUTPUT ;
    USE SIGNAL ;
    PORT
      LAYER M5 ;
        RECT  81.264 30.156 81.288 30.24 ;
    END
  END xa[227]
  PIN xa[228]
    DIRECTION OUTPUT ;
    USE SIGNAL ;
    PORT
      LAYER M5 ;
        RECT  81.408 30.156 81.432 30.24 ;
    END
  END xa[228]
  PIN xa[229]
    DIRECTION OUTPUT ;
    USE SIGNAL ;
    PORT
      LAYER M5 ;
        RECT  81.552 30.156 81.576 30.24 ;
    END
  END xa[229]
  PIN xa[22]
    DIRECTION OUTPUT ;
    USE SIGNAL ;
    PORT
      LAYER M5 ;
        RECT  51.744 30.156 51.768 30.24 ;
    END
  END xa[22]
  PIN xa[230]
    DIRECTION OUTPUT ;
    USE SIGNAL ;
    PORT
      LAYER M5 ;
        RECT  81.696 30.156 81.72 30.24 ;
    END
  END xa[230]
  PIN xa[231]
    DIRECTION OUTPUT ;
    USE SIGNAL ;
    PORT
      LAYER M5 ;
        RECT  81.84 30.156 81.864 30.24 ;
    END
  END xa[231]
  PIN xa[232]
    DIRECTION OUTPUT ;
    USE SIGNAL ;
    PORT
      LAYER M5 ;
        RECT  81.984 30.156 82.008 30.24 ;
    END
  END xa[232]
  PIN xa[233]
    DIRECTION OUTPUT ;
    USE SIGNAL ;
    PORT
      LAYER M5 ;
        RECT  82.128 30.156 82.152 30.24 ;
    END
  END xa[233]
  PIN xa[234]
    DIRECTION OUTPUT ;
    USE SIGNAL ;
    PORT
      LAYER M5 ;
        RECT  82.272 30.156 82.296 30.24 ;
    END
  END xa[234]
  PIN xa[235]
    DIRECTION OUTPUT ;
    USE SIGNAL ;
    PORT
      LAYER M5 ;
        RECT  82.416 30.156 82.44 30.24 ;
    END
  END xa[235]
  PIN xa[236]
    DIRECTION OUTPUT ;
    USE SIGNAL ;
    PORT
      LAYER M5 ;
        RECT  82.56 30.156 82.584 30.24 ;
    END
  END xa[236]
  PIN xa[237]
    DIRECTION OUTPUT ;
    USE SIGNAL ;
    PORT
      LAYER M5 ;
        RECT  82.704 30.156 82.728 30.24 ;
    END
  END xa[237]
  PIN xa[238]
    DIRECTION OUTPUT ;
    USE SIGNAL ;
    PORT
      LAYER M5 ;
        RECT  82.848 30.156 82.872 30.24 ;
    END
  END xa[238]
  PIN xa[239]
    DIRECTION OUTPUT ;
    USE SIGNAL ;
    PORT
      LAYER M5 ;
        RECT  82.992 30.156 83.016 30.24 ;
    END
  END xa[239]
  PIN xa[23]
    DIRECTION OUTPUT ;
    USE SIGNAL ;
    PORT
      LAYER M5 ;
        RECT  51.888 30.156 51.912 30.24 ;
    END
  END xa[23]
  PIN xa[240]
    DIRECTION OUTPUT ;
    USE SIGNAL ;
    PORT
      LAYER M5 ;
        RECT  83.136 30.156 83.16 30.24 ;
    END
  END xa[240]
  PIN xa[241]
    DIRECTION OUTPUT ;
    USE SIGNAL ;
    PORT
      LAYER M5 ;
        RECT  83.28 30.156 83.304 30.24 ;
    END
  END xa[241]
  PIN xa[242]
    DIRECTION OUTPUT ;
    USE SIGNAL ;
    PORT
      LAYER M5 ;
        RECT  83.424 30.156 83.448 30.24 ;
    END
  END xa[242]
  PIN xa[243]
    DIRECTION OUTPUT ;
    USE SIGNAL ;
    PORT
      LAYER M5 ;
        RECT  83.568 30.156 83.592 30.24 ;
    END
  END xa[243]
  PIN xa[244]
    DIRECTION OUTPUT ;
    USE SIGNAL ;
    PORT
      LAYER M5 ;
        RECT  83.712 30.156 83.736 30.24 ;
    END
  END xa[244]
  PIN xa[245]
    DIRECTION OUTPUT ;
    USE SIGNAL ;
    PORT
      LAYER M5 ;
        RECT  83.856 30.156 83.88 30.24 ;
    END
  END xa[245]
  PIN xa[246]
    DIRECTION OUTPUT ;
    USE SIGNAL ;
    PORT
      LAYER M5 ;
        RECT  84 30.156 84.024 30.24 ;
    END
  END xa[246]
  PIN xa[247]
    DIRECTION OUTPUT ;
    USE SIGNAL ;
    PORT
      LAYER M5 ;
        RECT  84.144 30.156 84.168 30.24 ;
    END
  END xa[247]
  PIN xa[248]
    DIRECTION OUTPUT ;
    USE SIGNAL ;
    PORT
      LAYER M5 ;
        RECT  84.288 30.156 84.312 30.24 ;
    END
  END xa[248]
  PIN xa[249]
    DIRECTION OUTPUT ;
    USE SIGNAL ;
    PORT
      LAYER M5 ;
        RECT  84.432 30.156 84.456 30.24 ;
    END
  END xa[249]
  PIN xa[24]
    DIRECTION OUTPUT ;
    USE SIGNAL ;
    PORT
      LAYER M5 ;
        RECT  52.032 30.156 52.056 30.24 ;
    END
  END xa[24]
  PIN xa[250]
    DIRECTION OUTPUT ;
    USE SIGNAL ;
    PORT
      LAYER M5 ;
        RECT  84.576 30.156 84.6 30.24 ;
    END
  END xa[250]
  PIN xa[251]
    DIRECTION OUTPUT ;
    USE SIGNAL ;
    PORT
      LAYER M5 ;
        RECT  84.72 30.156 84.744 30.24 ;
    END
  END xa[251]
  PIN xa[252]
    DIRECTION OUTPUT ;
    USE SIGNAL ;
    PORT
      LAYER M5 ;
        RECT  84.864 30.156 84.888 30.24 ;
    END
  END xa[252]
  PIN xa[253]
    DIRECTION OUTPUT ;
    USE SIGNAL ;
    PORT
      LAYER M5 ;
        RECT  85.008 30.156 85.032 30.24 ;
    END
  END xa[253]
  PIN xa[254]
    DIRECTION OUTPUT ;
    USE SIGNAL ;
    PORT
      LAYER M5 ;
        RECT  85.152 30.156 85.176 30.24 ;
    END
  END xa[254]
  PIN xa[255]
    DIRECTION OUTPUT ;
    USE SIGNAL ;
    PORT
      LAYER M5 ;
        RECT  85.296 30.156 85.32 30.24 ;
    END
  END xa[255]
  PIN xa[256]
    DIRECTION OUTPUT ;
    USE SIGNAL ;
    PORT
      LAYER M5 ;
        RECT  85.44 30.156 85.464 30.24 ;
    END
  END xa[256]
  PIN xa[257]
    DIRECTION OUTPUT ;
    USE SIGNAL ;
    PORT
      LAYER M5 ;
        RECT  85.584 30.156 85.608 30.24 ;
    END
  END xa[257]
  PIN xa[258]
    DIRECTION OUTPUT ;
    USE SIGNAL ;
    PORT
      LAYER M5 ;
        RECT  85.728 30.156 85.752 30.24 ;
    END
  END xa[258]
  PIN xa[259]
    DIRECTION OUTPUT ;
    USE SIGNAL ;
    PORT
      LAYER M5 ;
        RECT  85.872 30.156 85.896 30.24 ;
    END
  END xa[259]
  PIN xa[25]
    DIRECTION OUTPUT ;
    USE SIGNAL ;
    PORT
      LAYER M5 ;
        RECT  52.176 30.156 52.2 30.24 ;
    END
  END xa[25]
  PIN xa[260]
    DIRECTION OUTPUT ;
    USE SIGNAL ;
    PORT
      LAYER M5 ;
        RECT  86.016 30.156 86.04 30.24 ;
    END
  END xa[260]
  PIN xa[261]
    DIRECTION OUTPUT ;
    USE SIGNAL ;
    PORT
      LAYER M5 ;
        RECT  86.16 30.156 86.184 30.24 ;
    END
  END xa[261]
  PIN xa[262]
    DIRECTION OUTPUT ;
    USE SIGNAL ;
    PORT
      LAYER M5 ;
        RECT  86.304 30.156 86.328 30.24 ;
    END
  END xa[262]
  PIN xa[263]
    DIRECTION OUTPUT ;
    USE SIGNAL ;
    PORT
      LAYER M5 ;
        RECT  86.448 30.156 86.472 30.24 ;
    END
  END xa[263]
  PIN xa[264]
    DIRECTION OUTPUT ;
    USE SIGNAL ;
    PORT
      LAYER M5 ;
        RECT  86.592 30.156 86.616 30.24 ;
    END
  END xa[264]
  PIN xa[265]
    DIRECTION OUTPUT ;
    USE SIGNAL ;
    PORT
      LAYER M5 ;
        RECT  86.736 30.156 86.76 30.24 ;
    END
  END xa[265]
  PIN xa[266]
    DIRECTION OUTPUT ;
    USE SIGNAL ;
    PORT
      LAYER M5 ;
        RECT  86.88 30.156 86.904 30.24 ;
    END
  END xa[266]
  PIN xa[267]
    DIRECTION OUTPUT ;
    USE SIGNAL ;
    PORT
      LAYER M5 ;
        RECT  87.024 30.156 87.048 30.24 ;
    END
  END xa[267]
  PIN xa[268]
    DIRECTION OUTPUT ;
    USE SIGNAL ;
    PORT
      LAYER M5 ;
        RECT  87.168 30.156 87.192 30.24 ;
    END
  END xa[268]
  PIN xa[269]
    DIRECTION OUTPUT ;
    USE SIGNAL ;
    PORT
      LAYER M5 ;
        RECT  87.312 30.156 87.336 30.24 ;
    END
  END xa[269]
  PIN xa[26]
    DIRECTION OUTPUT ;
    USE SIGNAL ;
    PORT
      LAYER M5 ;
        RECT  52.32 30.156 52.344 30.24 ;
    END
  END xa[26]
  PIN xa[270]
    DIRECTION OUTPUT ;
    USE SIGNAL ;
    PORT
      LAYER M5 ;
        RECT  87.456 30.156 87.48 30.24 ;
    END
  END xa[270]
  PIN xa[271]
    DIRECTION OUTPUT ;
    USE SIGNAL ;
    PORT
      LAYER M5 ;
        RECT  87.6 30.156 87.624 30.24 ;
    END
  END xa[271]
  PIN xa[272]
    DIRECTION OUTPUT ;
    USE SIGNAL ;
    PORT
      LAYER M5 ;
        RECT  87.744 30.156 87.768 30.24 ;
    END
  END xa[272]
  PIN xa[273]
    DIRECTION OUTPUT ;
    USE SIGNAL ;
    PORT
      LAYER M5 ;
        RECT  87.888 30.156 87.912 30.24 ;
    END
  END xa[273]
  PIN xa[274]
    DIRECTION OUTPUT ;
    USE SIGNAL ;
    PORT
      LAYER M5 ;
        RECT  88.032 30.156 88.056 30.24 ;
    END
  END xa[274]
  PIN xa[275]
    DIRECTION OUTPUT ;
    USE SIGNAL ;
    PORT
      LAYER M5 ;
        RECT  88.176 30.156 88.2 30.24 ;
    END
  END xa[275]
  PIN xa[276]
    DIRECTION OUTPUT ;
    USE SIGNAL ;
    PORT
      LAYER M5 ;
        RECT  88.32 30.156 88.344 30.24 ;
    END
  END xa[276]
  PIN xa[277]
    DIRECTION OUTPUT ;
    USE SIGNAL ;
    PORT
      LAYER M5 ;
        RECT  88.464 30.156 88.488 30.24 ;
    END
  END xa[277]
  PIN xa[278]
    DIRECTION OUTPUT ;
    USE SIGNAL ;
    PORT
      LAYER M5 ;
        RECT  88.608 30.156 88.632 30.24 ;
    END
  END xa[278]
  PIN xa[279]
    DIRECTION OUTPUT ;
    USE SIGNAL ;
    PORT
      LAYER M5 ;
        RECT  88.752 30.156 88.776 30.24 ;
    END
  END xa[279]
  PIN xa[27]
    DIRECTION OUTPUT ;
    USE SIGNAL ;
    PORT
      LAYER M5 ;
        RECT  52.464 30.156 52.488 30.24 ;
    END
  END xa[27]
  PIN xa[280]
    DIRECTION OUTPUT ;
    USE SIGNAL ;
    PORT
      LAYER M5 ;
        RECT  88.896 30.156 88.92 30.24 ;
    END
  END xa[280]
  PIN xa[281]
    DIRECTION OUTPUT ;
    USE SIGNAL ;
    PORT
      LAYER M5 ;
        RECT  89.04 30.156 89.064 30.24 ;
    END
  END xa[281]
  PIN xa[282]
    DIRECTION OUTPUT ;
    USE SIGNAL ;
    PORT
      LAYER M5 ;
        RECT  89.184 30.156 89.208 30.24 ;
    END
  END xa[282]
  PIN xa[28]
    DIRECTION OUTPUT ;
    USE SIGNAL ;
    PORT
      LAYER M5 ;
        RECT  52.608 30.156 52.632 30.24 ;
    END
  END xa[28]
  PIN xa[29]
    DIRECTION OUTPUT ;
    USE SIGNAL ;
    PORT
      LAYER M5 ;
        RECT  52.752 30.156 52.776 30.24 ;
    END
  END xa[29]
  PIN xa[2]
    DIRECTION OUTPUT ;
    USE SIGNAL ;
    PORT
      LAYER M5 ;
        RECT  48.864 30.156 48.888 30.24 ;
    END
  END xa[2]
  PIN xa[30]
    DIRECTION OUTPUT ;
    USE SIGNAL ;
    PORT
      LAYER M5 ;
        RECT  52.896 30.156 52.92 30.24 ;
    END
  END xa[30]
  PIN xa[31]
    DIRECTION OUTPUT ;
    USE SIGNAL ;
    PORT
      LAYER M5 ;
        RECT  53.04 30.156 53.064 30.24 ;
    END
  END xa[31]
  PIN xa[32]
    DIRECTION OUTPUT ;
    USE SIGNAL ;
    PORT
      LAYER M5 ;
        RECT  53.184 30.156 53.208 30.24 ;
    END
  END xa[32]
  PIN xa[33]
    DIRECTION OUTPUT ;
    USE SIGNAL ;
    PORT
      LAYER M5 ;
        RECT  53.328 30.156 53.352 30.24 ;
    END
  END xa[33]
  PIN xa[34]
    DIRECTION OUTPUT ;
    USE SIGNAL ;
    PORT
      LAYER M5 ;
        RECT  53.472 30.156 53.496 30.24 ;
    END
  END xa[34]
  PIN xa[35]
    DIRECTION OUTPUT ;
    USE SIGNAL ;
    PORT
      LAYER M5 ;
        RECT  53.616 30.156 53.64 30.24 ;
    END
  END xa[35]
  PIN xa[36]
    DIRECTION OUTPUT ;
    USE SIGNAL ;
    PORT
      LAYER M5 ;
        RECT  53.76 30.156 53.784 30.24 ;
    END
  END xa[36]
  PIN xa[37]
    DIRECTION OUTPUT ;
    USE SIGNAL ;
    PORT
      LAYER M5 ;
        RECT  53.904 30.156 53.928 30.24 ;
    END
  END xa[37]
  PIN xa[38]
    DIRECTION OUTPUT ;
    USE SIGNAL ;
    PORT
      LAYER M5 ;
        RECT  54.048 30.156 54.072 30.24 ;
    END
  END xa[38]
  PIN xa[39]
    DIRECTION OUTPUT ;
    USE SIGNAL ;
    PORT
      LAYER M5 ;
        RECT  54.192 30.156 54.216 30.24 ;
    END
  END xa[39]
  PIN xa[3]
    DIRECTION OUTPUT ;
    USE SIGNAL ;
    PORT
      LAYER M5 ;
        RECT  49.008 30.156 49.032 30.24 ;
    END
  END xa[3]
  PIN xa[40]
    DIRECTION OUTPUT ;
    USE SIGNAL ;
    PORT
      LAYER M5 ;
        RECT  54.336 30.156 54.36 30.24 ;
    END
  END xa[40]
  PIN xa[41]
    DIRECTION OUTPUT ;
    USE SIGNAL ;
    PORT
      LAYER M5 ;
        RECT  54.48 30.156 54.504 30.24 ;
    END
  END xa[41]
  PIN xa[42]
    DIRECTION OUTPUT ;
    USE SIGNAL ;
    PORT
      LAYER M5 ;
        RECT  54.624 30.156 54.648 30.24 ;
    END
  END xa[42]
  PIN xa[43]
    DIRECTION OUTPUT ;
    USE SIGNAL ;
    PORT
      LAYER M5 ;
        RECT  54.768 30.156 54.792 30.24 ;
    END
  END xa[43]
  PIN xa[44]
    DIRECTION OUTPUT ;
    USE SIGNAL ;
    PORT
      LAYER M5 ;
        RECT  54.912 30.156 54.936 30.24 ;
    END
  END xa[44]
  PIN xa[45]
    DIRECTION OUTPUT ;
    USE SIGNAL ;
    PORT
      LAYER M5 ;
        RECT  55.056 30.156 55.08 30.24 ;
    END
  END xa[45]
  PIN xa[46]
    DIRECTION OUTPUT ;
    USE SIGNAL ;
    PORT
      LAYER M5 ;
        RECT  55.2 30.156 55.224 30.24 ;
    END
  END xa[46]
  PIN xa[47]
    DIRECTION OUTPUT ;
    USE SIGNAL ;
    PORT
      LAYER M5 ;
        RECT  55.344 30.156 55.368 30.24 ;
    END
  END xa[47]
  PIN xa[48]
    DIRECTION OUTPUT ;
    USE SIGNAL ;
    PORT
      LAYER M5 ;
        RECT  55.488 30.156 55.512 30.24 ;
    END
  END xa[48]
  PIN xa[49]
    DIRECTION OUTPUT ;
    USE SIGNAL ;
    PORT
      LAYER M5 ;
        RECT  55.632 30.156 55.656 30.24 ;
    END
  END xa[49]
  PIN xa[4]
    DIRECTION OUTPUT ;
    USE SIGNAL ;
    PORT
      LAYER M5 ;
        RECT  49.152 30.156 49.176 30.24 ;
    END
  END xa[4]
  PIN xa[50]
    DIRECTION OUTPUT ;
    USE SIGNAL ;
    PORT
      LAYER M5 ;
        RECT  55.776 30.156 55.8 30.24 ;
    END
  END xa[50]
  PIN xa[51]
    DIRECTION OUTPUT ;
    USE SIGNAL ;
    PORT
      LAYER M5 ;
        RECT  55.92 30.156 55.944 30.24 ;
    END
  END xa[51]
  PIN xa[52]
    DIRECTION OUTPUT ;
    USE SIGNAL ;
    PORT
      LAYER M5 ;
        RECT  56.064 30.156 56.088 30.24 ;
    END
  END xa[52]
  PIN xa[53]
    DIRECTION OUTPUT ;
    USE SIGNAL ;
    PORT
      LAYER M5 ;
        RECT  56.208 30.156 56.232 30.24 ;
    END
  END xa[53]
  PIN xa[54]
    DIRECTION OUTPUT ;
    USE SIGNAL ;
    PORT
      LAYER M5 ;
        RECT  56.352 30.156 56.376 30.24 ;
    END
  END xa[54]
  PIN xa[55]
    DIRECTION OUTPUT ;
    USE SIGNAL ;
    PORT
      LAYER M5 ;
        RECT  56.496 30.156 56.52 30.24 ;
    END
  END xa[55]
  PIN xa[56]
    DIRECTION OUTPUT ;
    USE SIGNAL ;
    PORT
      LAYER M5 ;
        RECT  56.64 30.156 56.664 30.24 ;
    END
  END xa[56]
  PIN xa[57]
    DIRECTION OUTPUT ;
    USE SIGNAL ;
    PORT
      LAYER M5 ;
        RECT  56.784 30.156 56.808 30.24 ;
    END
  END xa[57]
  PIN xa[58]
    DIRECTION OUTPUT ;
    USE SIGNAL ;
    PORT
      LAYER M5 ;
        RECT  56.928 30.156 56.952 30.24 ;
    END
  END xa[58]
  PIN xa[59]
    DIRECTION OUTPUT ;
    USE SIGNAL ;
    PORT
      LAYER M5 ;
        RECT  57.072 30.156 57.096 30.24 ;
    END
  END xa[59]
  PIN xa[5]
    DIRECTION OUTPUT ;
    USE SIGNAL ;
    PORT
      LAYER M5 ;
        RECT  49.296 30.156 49.32 30.24 ;
    END
  END xa[5]
  PIN xa[60]
    DIRECTION OUTPUT ;
    USE SIGNAL ;
    PORT
      LAYER M5 ;
        RECT  57.216 30.156 57.24 30.24 ;
    END
  END xa[60]
  PIN xa[61]
    DIRECTION OUTPUT ;
    USE SIGNAL ;
    PORT
      LAYER M5 ;
        RECT  57.36 30.156 57.384 30.24 ;
    END
  END xa[61]
  PIN xa[62]
    DIRECTION OUTPUT ;
    USE SIGNAL ;
    PORT
      LAYER M5 ;
        RECT  57.504 30.156 57.528 30.24 ;
    END
  END xa[62]
  PIN xa[63]
    DIRECTION OUTPUT ;
    USE SIGNAL ;
    PORT
      LAYER M5 ;
        RECT  57.648 30.156 57.672 30.24 ;
    END
  END xa[63]
  PIN xa[64]
    DIRECTION OUTPUT ;
    USE SIGNAL ;
    PORT
      LAYER M5 ;
        RECT  57.792 30.156 57.816 30.24 ;
    END
  END xa[64]
  PIN xa[65]
    DIRECTION OUTPUT ;
    USE SIGNAL ;
    PORT
      LAYER M5 ;
        RECT  57.936 30.156 57.96 30.24 ;
    END
  END xa[65]
  PIN xa[66]
    DIRECTION OUTPUT ;
    USE SIGNAL ;
    PORT
      LAYER M5 ;
        RECT  58.08 30.156 58.104 30.24 ;
    END
  END xa[66]
  PIN xa[67]
    DIRECTION OUTPUT ;
    USE SIGNAL ;
    PORT
      LAYER M5 ;
        RECT  58.224 30.156 58.248 30.24 ;
    END
  END xa[67]
  PIN xa[68]
    DIRECTION OUTPUT ;
    USE SIGNAL ;
    PORT
      LAYER M5 ;
        RECT  58.368 30.156 58.392 30.24 ;
    END
  END xa[68]
  PIN xa[69]
    DIRECTION OUTPUT ;
    USE SIGNAL ;
    PORT
      LAYER M5 ;
        RECT  58.512 30.156 58.536 30.24 ;
    END
  END xa[69]
  PIN xa[6]
    DIRECTION OUTPUT ;
    USE SIGNAL ;
    PORT
      LAYER M5 ;
        RECT  49.44 30.156 49.464 30.24 ;
    END
  END xa[6]
  PIN xa[70]
    DIRECTION OUTPUT ;
    USE SIGNAL ;
    PORT
      LAYER M5 ;
        RECT  58.656 30.156 58.68 30.24 ;
    END
  END xa[70]
  PIN xa[71]
    DIRECTION OUTPUT ;
    USE SIGNAL ;
    PORT
      LAYER M5 ;
        RECT  58.8 30.156 58.824 30.24 ;
    END
  END xa[71]
  PIN xa[72]
    DIRECTION OUTPUT ;
    USE SIGNAL ;
    PORT
      LAYER M5 ;
        RECT  58.944 30.156 58.968 30.24 ;
    END
  END xa[72]
  PIN xa[73]
    DIRECTION OUTPUT ;
    USE SIGNAL ;
    PORT
      LAYER M5 ;
        RECT  59.088 30.156 59.112 30.24 ;
    END
  END xa[73]
  PIN xa[74]
    DIRECTION OUTPUT ;
    USE SIGNAL ;
    PORT
      LAYER M5 ;
        RECT  59.232 30.156 59.256 30.24 ;
    END
  END xa[74]
  PIN xa[75]
    DIRECTION OUTPUT ;
    USE SIGNAL ;
    PORT
      LAYER M5 ;
        RECT  59.376 30.156 59.4 30.24 ;
    END
  END xa[75]
  PIN xa[76]
    DIRECTION OUTPUT ;
    USE SIGNAL ;
    PORT
      LAYER M5 ;
        RECT  59.52 30.156 59.544 30.24 ;
    END
  END xa[76]
  PIN xa[77]
    DIRECTION OUTPUT ;
    USE SIGNAL ;
    PORT
      LAYER M5 ;
        RECT  59.664 30.156 59.688 30.24 ;
    END
  END xa[77]
  PIN xa[78]
    DIRECTION OUTPUT ;
    USE SIGNAL ;
    PORT
      LAYER M5 ;
        RECT  59.808 30.156 59.832 30.24 ;
    END
  END xa[78]
  PIN xa[79]
    DIRECTION OUTPUT ;
    USE SIGNAL ;
    PORT
      LAYER M5 ;
        RECT  59.952 30.156 59.976 30.24 ;
    END
  END xa[79]
  PIN xa[7]
    DIRECTION OUTPUT ;
    USE SIGNAL ;
    PORT
      LAYER M5 ;
        RECT  49.584 30.156 49.608 30.24 ;
    END
  END xa[7]
  PIN xa[80]
    DIRECTION OUTPUT ;
    USE SIGNAL ;
    PORT
      LAYER M5 ;
        RECT  60.096 30.156 60.12 30.24 ;
    END
  END xa[80]
  PIN xa[81]
    DIRECTION OUTPUT ;
    USE SIGNAL ;
    PORT
      LAYER M5 ;
        RECT  60.24 30.156 60.264 30.24 ;
    END
  END xa[81]
  PIN xa[82]
    DIRECTION OUTPUT ;
    USE SIGNAL ;
    PORT
      LAYER M5 ;
        RECT  60.384 30.156 60.408 30.24 ;
    END
  END xa[82]
  PIN xa[83]
    DIRECTION OUTPUT ;
    USE SIGNAL ;
    PORT
      LAYER M5 ;
        RECT  60.528 30.156 60.552 30.24 ;
    END
  END xa[83]
  PIN xa[84]
    DIRECTION OUTPUT ;
    USE SIGNAL ;
    PORT
      LAYER M5 ;
        RECT  60.672 30.156 60.696 30.24 ;
    END
  END xa[84]
  PIN xa[85]
    DIRECTION OUTPUT ;
    USE SIGNAL ;
    PORT
      LAYER M5 ;
        RECT  60.816 30.156 60.84 30.24 ;
    END
  END xa[85]
  PIN xa[86]
    DIRECTION OUTPUT ;
    USE SIGNAL ;
    PORT
      LAYER M5 ;
        RECT  60.96 30.156 60.984 30.24 ;
    END
  END xa[86]
  PIN xa[87]
    DIRECTION OUTPUT ;
    USE SIGNAL ;
    PORT
      LAYER M5 ;
        RECT  61.104 30.156 61.128 30.24 ;
    END
  END xa[87]
  PIN xa[88]
    DIRECTION OUTPUT ;
    USE SIGNAL ;
    PORT
      LAYER M5 ;
        RECT  61.248 30.156 61.272 30.24 ;
    END
  END xa[88]
  PIN xa[89]
    DIRECTION OUTPUT ;
    USE SIGNAL ;
    PORT
      LAYER M5 ;
        RECT  61.392 30.156 61.416 30.24 ;
    END
  END xa[89]
  PIN xa[8]
    DIRECTION OUTPUT ;
    USE SIGNAL ;
    PORT
      LAYER M5 ;
        RECT  49.728 30.156 49.752 30.24 ;
    END
  END xa[8]
  PIN xa[90]
    DIRECTION OUTPUT ;
    USE SIGNAL ;
    PORT
      LAYER M5 ;
        RECT  61.536 30.156 61.56 30.24 ;
    END
  END xa[90]
  PIN xa[91]
    DIRECTION OUTPUT ;
    USE SIGNAL ;
    PORT
      LAYER M5 ;
        RECT  61.68 30.156 61.704 30.24 ;
    END
  END xa[91]
  PIN xa[92]
    DIRECTION OUTPUT ;
    USE SIGNAL ;
    PORT
      LAYER M5 ;
        RECT  61.824 30.156 61.848 30.24 ;
    END
  END xa[92]
  PIN xa[93]
    DIRECTION OUTPUT ;
    USE SIGNAL ;
    PORT
      LAYER M5 ;
        RECT  61.968 30.156 61.992 30.24 ;
    END
  END xa[93]
  PIN xa[94]
    DIRECTION OUTPUT ;
    USE SIGNAL ;
    PORT
      LAYER M5 ;
        RECT  62.112 30.156 62.136 30.24 ;
    END
  END xa[94]
  PIN xa[95]
    DIRECTION OUTPUT ;
    USE SIGNAL ;
    PORT
      LAYER M5 ;
        RECT  62.256 30.156 62.28 30.24 ;
    END
  END xa[95]
  PIN xa[96]
    DIRECTION OUTPUT ;
    USE SIGNAL ;
    PORT
      LAYER M5 ;
        RECT  62.4 30.156 62.424 30.24 ;
    END
  END xa[96]
  PIN xa[97]
    DIRECTION OUTPUT ;
    USE SIGNAL ;
    PORT
      LAYER M5 ;
        RECT  62.544 30.156 62.568 30.24 ;
    END
  END xa[97]
  PIN xa[98]
    DIRECTION OUTPUT ;
    USE SIGNAL ;
    PORT
      LAYER M5 ;
        RECT  62.688 30.156 62.712 30.24 ;
    END
  END xa[98]
  PIN xa[99]
    DIRECTION OUTPUT ;
    USE SIGNAL ;
    PORT
      LAYER M5 ;
        RECT  62.832 30.156 62.856 30.24 ;
    END
  END xa[99]
  PIN xa[9]
    DIRECTION OUTPUT ;
    USE SIGNAL ;
    PORT
      LAYER M5 ;
        RECT  49.872 30.156 49.896 30.24 ;
    END
  END xa[9]
  PIN xai[0]
    DIRECTION INPUT ;
    USE SIGNAL ;
    PORT
      LAYER M5 ;
        RECT  131.424 0 131.448 0.084 ;
    END
  END xai[0]
  PIN xai[100]
    DIRECTION INPUT ;
    USE SIGNAL ;
    PORT
      LAYER M5 ;
        RECT  145.824 0 145.848 0.084 ;
    END
  END xai[100]
  PIN xai[101]
    DIRECTION INPUT ;
    USE SIGNAL ;
    PORT
      LAYER M5 ;
        RECT  145.968 0 145.992 0.084 ;
    END
  END xai[101]
  PIN xai[102]
    DIRECTION INPUT ;
    USE SIGNAL ;
    PORT
      LAYER M5 ;
        RECT  146.112 0 146.136 0.084 ;
    END
  END xai[102]
  PIN xai[103]
    DIRECTION INPUT ;
    USE SIGNAL ;
    PORT
      LAYER M5 ;
        RECT  146.256 0 146.28 0.084 ;
    END
  END xai[103]
  PIN xai[104]
    DIRECTION INPUT ;
    USE SIGNAL ;
    PORT
      LAYER M5 ;
        RECT  146.4 0 146.424 0.084 ;
    END
  END xai[104]
  PIN xai[105]
    DIRECTION INPUT ;
    USE SIGNAL ;
    PORT
      LAYER M5 ;
        RECT  146.544 0 146.568 0.084 ;
    END
  END xai[105]
  PIN xai[106]
    DIRECTION INPUT ;
    USE SIGNAL ;
    PORT
      LAYER M5 ;
        RECT  146.688 0 146.712 0.084 ;
    END
  END xai[106]
  PIN xai[107]
    DIRECTION INPUT ;
    USE SIGNAL ;
    PORT
      LAYER M5 ;
        RECT  146.832 0 146.856 0.084 ;
    END
  END xai[107]
  PIN xai[108]
    DIRECTION INPUT ;
    USE SIGNAL ;
    PORT
      LAYER M5 ;
        RECT  146.976 0 147 0.084 ;
    END
  END xai[108]
  PIN xai[109]
    DIRECTION INPUT ;
    USE SIGNAL ;
    PORT
      LAYER M5 ;
        RECT  147.12 0 147.144 0.084 ;
    END
  END xai[109]
  PIN xai[10]
    DIRECTION INPUT ;
    USE SIGNAL ;
    PORT
      LAYER M5 ;
        RECT  132.864 0 132.888 0.084 ;
    END
  END xai[10]
  PIN xai[110]
    DIRECTION INPUT ;
    USE SIGNAL ;
    PORT
      LAYER M5 ;
        RECT  147.264 0 147.288 0.084 ;
    END
  END xai[110]
  PIN xai[111]
    DIRECTION INPUT ;
    USE SIGNAL ;
    PORT
      LAYER M5 ;
        RECT  147.408 0 147.432 0.084 ;
    END
  END xai[111]
  PIN xai[112]
    DIRECTION INPUT ;
    USE SIGNAL ;
    PORT
      LAYER M5 ;
        RECT  147.552 0 147.576 0.084 ;
    END
  END xai[112]
  PIN xai[113]
    DIRECTION INPUT ;
    USE SIGNAL ;
    PORT
      LAYER M5 ;
        RECT  147.696 0 147.72 0.084 ;
    END
  END xai[113]
  PIN xai[114]
    DIRECTION INPUT ;
    USE SIGNAL ;
    PORT
      LAYER M5 ;
        RECT  147.84 0 147.864 0.084 ;
    END
  END xai[114]
  PIN xai[115]
    DIRECTION INPUT ;
    USE SIGNAL ;
    PORT
      LAYER M5 ;
        RECT  147.984 0 148.008 0.084 ;
    END
  END xai[115]
  PIN xai[116]
    DIRECTION INPUT ;
    USE SIGNAL ;
    PORT
      LAYER M5 ;
        RECT  148.128 0 148.152 0.084 ;
    END
  END xai[116]
  PIN xai[117]
    DIRECTION INPUT ;
    USE SIGNAL ;
    PORT
      LAYER M5 ;
        RECT  148.272 0 148.296 0.084 ;
    END
  END xai[117]
  PIN xai[118]
    DIRECTION INPUT ;
    USE SIGNAL ;
    PORT
      LAYER M5 ;
        RECT  148.416 0 148.44 0.084 ;
    END
  END xai[118]
  PIN xai[119]
    DIRECTION INPUT ;
    USE SIGNAL ;
    PORT
      LAYER M5 ;
        RECT  148.56 0 148.584 0.084 ;
    END
  END xai[119]
  PIN xai[11]
    DIRECTION INPUT ;
    USE SIGNAL ;
    PORT
      LAYER M5 ;
        RECT  133.008 0 133.032 0.084 ;
    END
  END xai[11]
  PIN xai[120]
    DIRECTION INPUT ;
    USE SIGNAL ;
    PORT
      LAYER M5 ;
        RECT  148.704 0 148.728 0.084 ;
    END
  END xai[120]
  PIN xai[121]
    DIRECTION INPUT ;
    USE SIGNAL ;
    PORT
      LAYER M5 ;
        RECT  148.848 0 148.872 0.084 ;
    END
  END xai[121]
  PIN xai[122]
    DIRECTION INPUT ;
    USE SIGNAL ;
    PORT
      LAYER M5 ;
        RECT  148.992 0 149.016 0.084 ;
    END
  END xai[122]
  PIN xai[123]
    DIRECTION INPUT ;
    USE SIGNAL ;
    PORT
      LAYER M5 ;
        RECT  149.136 0 149.16 0.084 ;
    END
  END xai[123]
  PIN xai[124]
    DIRECTION INPUT ;
    USE SIGNAL ;
    PORT
      LAYER M5 ;
        RECT  149.28 0 149.304 0.084 ;
    END
  END xai[124]
  PIN xai[125]
    DIRECTION INPUT ;
    USE SIGNAL ;
    PORT
      LAYER M5 ;
        RECT  149.424 0 149.448 0.084 ;
    END
  END xai[125]
  PIN xai[126]
    DIRECTION INPUT ;
    USE SIGNAL ;
    PORT
      LAYER M5 ;
        RECT  149.568 0 149.592 0.084 ;
    END
  END xai[126]
  PIN xai[127]
    DIRECTION INPUT ;
    USE SIGNAL ;
    PORT
      LAYER M5 ;
        RECT  149.712 0 149.736 0.084 ;
    END
  END xai[127]
  PIN xai[128]
    DIRECTION INPUT ;
    USE SIGNAL ;
    PORT
      LAYER M5 ;
        RECT  149.856 0 149.88 0.084 ;
    END
  END xai[128]
  PIN xai[129]
    DIRECTION INPUT ;
    USE SIGNAL ;
    PORT
      LAYER M5 ;
        RECT  150 0 150.024 0.084 ;
    END
  END xai[129]
  PIN xai[12]
    DIRECTION INPUT ;
    USE SIGNAL ;
    PORT
      LAYER M5 ;
        RECT  133.152 0 133.176 0.084 ;
    END
  END xai[12]
  PIN xai[130]
    DIRECTION INPUT ;
    USE SIGNAL ;
    PORT
      LAYER M5 ;
        RECT  150.144 0 150.168 0.084 ;
    END
  END xai[130]
  PIN xai[131]
    DIRECTION INPUT ;
    USE SIGNAL ;
    PORT
      LAYER M5 ;
        RECT  150.288 0 150.312 0.084 ;
    END
  END xai[131]
  PIN xai[132]
    DIRECTION INPUT ;
    USE SIGNAL ;
    PORT
      LAYER M5 ;
        RECT  150.432 0 150.456 0.084 ;
    END
  END xai[132]
  PIN xai[133]
    DIRECTION INPUT ;
    USE SIGNAL ;
    PORT
      LAYER M5 ;
        RECT  150.576 0 150.6 0.084 ;
    END
  END xai[133]
  PIN xai[134]
    DIRECTION INPUT ;
    USE SIGNAL ;
    PORT
      LAYER M5 ;
        RECT  150.72 0 150.744 0.084 ;
    END
  END xai[134]
  PIN xai[135]
    DIRECTION INPUT ;
    USE SIGNAL ;
    PORT
      LAYER M5 ;
        RECT  150.864 0 150.888 0.084 ;
    END
  END xai[135]
  PIN xai[136]
    DIRECTION INPUT ;
    USE SIGNAL ;
    PORT
      LAYER M5 ;
        RECT  151.008 0 151.032 0.084 ;
    END
  END xai[136]
  PIN xai[137]
    DIRECTION INPUT ;
    USE SIGNAL ;
    PORT
      LAYER M5 ;
        RECT  151.152 0 151.176 0.084 ;
    END
  END xai[137]
  PIN xai[138]
    DIRECTION INPUT ;
    USE SIGNAL ;
    PORT
      LAYER M5 ;
        RECT  151.296 0 151.32 0.084 ;
    END
  END xai[138]
  PIN xai[139]
    DIRECTION INPUT ;
    USE SIGNAL ;
    PORT
      LAYER M5 ;
        RECT  151.44 0 151.464 0.084 ;
    END
  END xai[139]
  PIN xai[13]
    DIRECTION INPUT ;
    USE SIGNAL ;
    PORT
      LAYER M5 ;
        RECT  133.296 0 133.32 0.084 ;
    END
  END xai[13]
  PIN xai[140]
    DIRECTION INPUT ;
    USE SIGNAL ;
    PORT
      LAYER M5 ;
        RECT  151.584 0 151.608 0.084 ;
    END
  END xai[140]
  PIN xai[141]
    DIRECTION INPUT ;
    USE SIGNAL ;
    PORT
      LAYER M5 ;
        RECT  151.728 0 151.752 0.084 ;
    END
  END xai[141]
  PIN xai[142]
    DIRECTION INPUT ;
    USE SIGNAL ;
    PORT
      LAYER M5 ;
        RECT  151.872 0 151.896 0.084 ;
    END
  END xai[142]
  PIN xai[143]
    DIRECTION INPUT ;
    USE SIGNAL ;
    PORT
      LAYER M5 ;
        RECT  152.016 0 152.04 0.084 ;
    END
  END xai[143]
  PIN xai[144]
    DIRECTION INPUT ;
    USE SIGNAL ;
    PORT
      LAYER M5 ;
        RECT  152.16 0 152.184 0.084 ;
    END
  END xai[144]
  PIN xai[145]
    DIRECTION INPUT ;
    USE SIGNAL ;
    PORT
      LAYER M5 ;
        RECT  152.304 0 152.328 0.084 ;
    END
  END xai[145]
  PIN xai[146]
    DIRECTION INPUT ;
    USE SIGNAL ;
    PORT
      LAYER M5 ;
        RECT  152.448 0 152.472 0.084 ;
    END
  END xai[146]
  PIN xai[147]
    DIRECTION INPUT ;
    USE SIGNAL ;
    PORT
      LAYER M5 ;
        RECT  152.592 0 152.616 0.084 ;
    END
  END xai[147]
  PIN xai[148]
    DIRECTION INPUT ;
    USE SIGNAL ;
    PORT
      LAYER M5 ;
        RECT  152.736 0 152.76 0.084 ;
    END
  END xai[148]
  PIN xai[149]
    DIRECTION INPUT ;
    USE SIGNAL ;
    PORT
      LAYER M5 ;
        RECT  152.88 0 152.904 0.084 ;
    END
  END xai[149]
  PIN xai[14]
    DIRECTION INPUT ;
    USE SIGNAL ;
    PORT
      LAYER M5 ;
        RECT  133.44 0 133.464 0.084 ;
    END
  END xai[14]
  PIN xai[150]
    DIRECTION INPUT ;
    USE SIGNAL ;
    PORT
      LAYER M5 ;
        RECT  153.024 0 153.048 0.084 ;
    END
  END xai[150]
  PIN xai[151]
    DIRECTION INPUT ;
    USE SIGNAL ;
    PORT
      LAYER M5 ;
        RECT  153.168 0 153.192 0.084 ;
    END
  END xai[151]
  PIN xai[152]
    DIRECTION INPUT ;
    USE SIGNAL ;
    PORT
      LAYER M5 ;
        RECT  153.312 0 153.336 0.084 ;
    END
  END xai[152]
  PIN xai[153]
    DIRECTION INPUT ;
    USE SIGNAL ;
    PORT
      LAYER M5 ;
        RECT  153.456 0 153.48 0.084 ;
    END
  END xai[153]
  PIN xai[154]
    DIRECTION INPUT ;
    USE SIGNAL ;
    PORT
      LAYER M5 ;
        RECT  153.6 0 153.624 0.084 ;
    END
  END xai[154]
  PIN xai[155]
    DIRECTION INPUT ;
    USE SIGNAL ;
    PORT
      LAYER M5 ;
        RECT  153.744 0 153.768 0.084 ;
    END
  END xai[155]
  PIN xai[156]
    DIRECTION INPUT ;
    USE SIGNAL ;
    PORT
      LAYER M5 ;
        RECT  153.888 0 153.912 0.084 ;
    END
  END xai[156]
  PIN xai[157]
    DIRECTION INPUT ;
    USE SIGNAL ;
    PORT
      LAYER M5 ;
        RECT  154.032 0 154.056 0.084 ;
    END
  END xai[157]
  PIN xai[158]
    DIRECTION INPUT ;
    USE SIGNAL ;
    PORT
      LAYER M5 ;
        RECT  154.176 0 154.2 0.084 ;
    END
  END xai[158]
  PIN xai[159]
    DIRECTION INPUT ;
    USE SIGNAL ;
    PORT
      LAYER M5 ;
        RECT  154.32 0 154.344 0.084 ;
    END
  END xai[159]
  PIN xai[15]
    DIRECTION INPUT ;
    USE SIGNAL ;
    PORT
      LAYER M5 ;
        RECT  133.584 0 133.608 0.084 ;
    END
  END xai[15]
  PIN xai[160]
    DIRECTION INPUT ;
    USE SIGNAL ;
    PORT
      LAYER M5 ;
        RECT  154.464 0 154.488 0.084 ;
    END
  END xai[160]
  PIN xai[161]
    DIRECTION INPUT ;
    USE SIGNAL ;
    PORT
      LAYER M5 ;
        RECT  154.608 0 154.632 0.084 ;
    END
  END xai[161]
  PIN xai[162]
    DIRECTION INPUT ;
    USE SIGNAL ;
    PORT
      LAYER M5 ;
        RECT  154.752 0 154.776 0.084 ;
    END
  END xai[162]
  PIN xai[163]
    DIRECTION INPUT ;
    USE SIGNAL ;
    PORT
      LAYER M5 ;
        RECT  154.896 0 154.92 0.084 ;
    END
  END xai[163]
  PIN xai[164]
    DIRECTION INPUT ;
    USE SIGNAL ;
    PORT
      LAYER M5 ;
        RECT  155.04 0 155.064 0.084 ;
    END
  END xai[164]
  PIN xai[165]
    DIRECTION INPUT ;
    USE SIGNAL ;
    PORT
      LAYER M5 ;
        RECT  155.184 0 155.208 0.084 ;
    END
  END xai[165]
  PIN xai[166]
    DIRECTION INPUT ;
    USE SIGNAL ;
    PORT
      LAYER M5 ;
        RECT  155.328 0 155.352 0.084 ;
    END
  END xai[166]
  PIN xai[167]
    DIRECTION INPUT ;
    USE SIGNAL ;
    PORT
      LAYER M5 ;
        RECT  155.472 0 155.496 0.084 ;
    END
  END xai[167]
  PIN xai[168]
    DIRECTION INPUT ;
    USE SIGNAL ;
    PORT
      LAYER M5 ;
        RECT  155.616 0 155.64 0.084 ;
    END
  END xai[168]
  PIN xai[169]
    DIRECTION INPUT ;
    USE SIGNAL ;
    PORT
      LAYER M5 ;
        RECT  155.76 0 155.784 0.084 ;
    END
  END xai[169]
  PIN xai[16]
    DIRECTION INPUT ;
    USE SIGNAL ;
    PORT
      LAYER M5 ;
        RECT  133.728 0 133.752 0.084 ;
    END
  END xai[16]
  PIN xai[170]
    DIRECTION INPUT ;
    USE SIGNAL ;
    PORT
      LAYER M5 ;
        RECT  155.904 0 155.928 0.084 ;
    END
  END xai[170]
  PIN xai[171]
    DIRECTION INPUT ;
    USE SIGNAL ;
    PORT
      LAYER M5 ;
        RECT  156.048 0 156.072 0.084 ;
    END
  END xai[171]
  PIN xai[172]
    DIRECTION INPUT ;
    USE SIGNAL ;
    PORT
      LAYER M5 ;
        RECT  156.192 0 156.216 0.084 ;
    END
  END xai[172]
  PIN xai[173]
    DIRECTION INPUT ;
    USE SIGNAL ;
    PORT
      LAYER M5 ;
        RECT  156.336 0 156.36 0.084 ;
    END
  END xai[173]
  PIN xai[174]
    DIRECTION INPUT ;
    USE SIGNAL ;
    PORT
      LAYER M5 ;
        RECT  156.48 0 156.504 0.084 ;
    END
  END xai[174]
  PIN xai[175]
    DIRECTION INPUT ;
    USE SIGNAL ;
    PORT
      LAYER M5 ;
        RECT  156.624 0 156.648 0.084 ;
    END
  END xai[175]
  PIN xai[176]
    DIRECTION INPUT ;
    USE SIGNAL ;
    PORT
      LAYER M5 ;
        RECT  156.768 0 156.792 0.084 ;
    END
  END xai[176]
  PIN xai[177]
    DIRECTION INPUT ;
    USE SIGNAL ;
    PORT
      LAYER M5 ;
        RECT  156.912 0 156.936 0.084 ;
    END
  END xai[177]
  PIN xai[178]
    DIRECTION INPUT ;
    USE SIGNAL ;
    PORT
      LAYER M5 ;
        RECT  157.056 0 157.08 0.084 ;
    END
  END xai[178]
  PIN xai[179]
    DIRECTION INPUT ;
    USE SIGNAL ;
    PORT
      LAYER M5 ;
        RECT  157.2 0 157.224 0.084 ;
    END
  END xai[179]
  PIN xai[17]
    DIRECTION INPUT ;
    USE SIGNAL ;
    PORT
      LAYER M5 ;
        RECT  133.872 0 133.896 0.084 ;
    END
  END xai[17]
  PIN xai[180]
    DIRECTION INPUT ;
    USE SIGNAL ;
    PORT
      LAYER M5 ;
        RECT  157.344 0 157.368 0.084 ;
    END
  END xai[180]
  PIN xai[181]
    DIRECTION INPUT ;
    USE SIGNAL ;
    PORT
      LAYER M5 ;
        RECT  157.488 0 157.512 0.084 ;
    END
  END xai[181]
  PIN xai[182]
    DIRECTION INPUT ;
    USE SIGNAL ;
    PORT
      LAYER M5 ;
        RECT  157.632 0 157.656 0.084 ;
    END
  END xai[182]
  PIN xai[183]
    DIRECTION INPUT ;
    USE SIGNAL ;
    PORT
      LAYER M5 ;
        RECT  157.776 0 157.8 0.084 ;
    END
  END xai[183]
  PIN xai[184]
    DIRECTION INPUT ;
    USE SIGNAL ;
    PORT
      LAYER M5 ;
        RECT  157.92 0 157.944 0.084 ;
    END
  END xai[184]
  PIN xai[185]
    DIRECTION INPUT ;
    USE SIGNAL ;
    PORT
      LAYER M5 ;
        RECT  158.064 0 158.088 0.084 ;
    END
  END xai[185]
  PIN xai[186]
    DIRECTION INPUT ;
    USE SIGNAL ;
    PORT
      LAYER M5 ;
        RECT  158.208 0 158.232 0.084 ;
    END
  END xai[186]
  PIN xai[187]
    DIRECTION INPUT ;
    USE SIGNAL ;
    PORT
      LAYER M5 ;
        RECT  158.352 0 158.376 0.084 ;
    END
  END xai[187]
  PIN xai[188]
    DIRECTION INPUT ;
    USE SIGNAL ;
    PORT
      LAYER M5 ;
        RECT  158.496 0 158.52 0.084 ;
    END
  END xai[188]
  PIN xai[189]
    DIRECTION INPUT ;
    USE SIGNAL ;
    PORT
      LAYER M5 ;
        RECT  158.64 0 158.664 0.084 ;
    END
  END xai[189]
  PIN xai[18]
    DIRECTION INPUT ;
    USE SIGNAL ;
    PORT
      LAYER M5 ;
        RECT  134.016 0 134.04 0.084 ;
    END
  END xai[18]
  PIN xai[190]
    DIRECTION INPUT ;
    USE SIGNAL ;
    PORT
      LAYER M5 ;
        RECT  158.784 0 158.808 0.084 ;
    END
  END xai[190]
  PIN xai[191]
    DIRECTION INPUT ;
    USE SIGNAL ;
    PORT
      LAYER M5 ;
        RECT  158.928 0 158.952 0.084 ;
    END
  END xai[191]
  PIN xai[192]
    DIRECTION INPUT ;
    USE SIGNAL ;
    PORT
      LAYER M5 ;
        RECT  159.072 0 159.096 0.084 ;
    END
  END xai[192]
  PIN xai[193]
    DIRECTION INPUT ;
    USE SIGNAL ;
    PORT
      LAYER M5 ;
        RECT  159.216 0 159.24 0.084 ;
    END
  END xai[193]
  PIN xai[194]
    DIRECTION INPUT ;
    USE SIGNAL ;
    PORT
      LAYER M5 ;
        RECT  159.36 0 159.384 0.084 ;
    END
  END xai[194]
  PIN xai[195]
    DIRECTION INPUT ;
    USE SIGNAL ;
    PORT
      LAYER M5 ;
        RECT  159.504 0 159.528 0.084 ;
    END
  END xai[195]
  PIN xai[196]
    DIRECTION INPUT ;
    USE SIGNAL ;
    PORT
      LAYER M5 ;
        RECT  159.648 0 159.672 0.084 ;
    END
  END xai[196]
  PIN xai[197]
    DIRECTION INPUT ;
    USE SIGNAL ;
    PORT
      LAYER M5 ;
        RECT  159.792 0 159.816 0.084 ;
    END
  END xai[197]
  PIN xai[198]
    DIRECTION INPUT ;
    USE SIGNAL ;
    PORT
      LAYER M5 ;
        RECT  159.936 0 159.96 0.084 ;
    END
  END xai[198]
  PIN xai[199]
    DIRECTION INPUT ;
    USE SIGNAL ;
    PORT
      LAYER M5 ;
        RECT  160.08 0 160.104 0.084 ;
    END
  END xai[199]
  PIN xai[19]
    DIRECTION INPUT ;
    USE SIGNAL ;
    PORT
      LAYER M5 ;
        RECT  134.16 0 134.184 0.084 ;
    END
  END xai[19]
  PIN xai[1]
    DIRECTION INPUT ;
    USE SIGNAL ;
    PORT
      LAYER M5 ;
        RECT  131.568 0 131.592 0.084 ;
    END
  END xai[1]
  PIN xai[200]
    DIRECTION INPUT ;
    USE SIGNAL ;
    PORT
      LAYER M5 ;
        RECT  160.224 0 160.248 0.084 ;
    END
  END xai[200]
  PIN xai[201]
    DIRECTION INPUT ;
    USE SIGNAL ;
    PORT
      LAYER M5 ;
        RECT  160.368 0 160.392 0.084 ;
    END
  END xai[201]
  PIN xai[202]
    DIRECTION INPUT ;
    USE SIGNAL ;
    PORT
      LAYER M5 ;
        RECT  160.512 0 160.536 0.084 ;
    END
  END xai[202]
  PIN xai[203]
    DIRECTION INPUT ;
    USE SIGNAL ;
    PORT
      LAYER M5 ;
        RECT  160.656 0 160.68 0.084 ;
    END
  END xai[203]
  PIN xai[204]
    DIRECTION INPUT ;
    USE SIGNAL ;
    PORT
      LAYER M5 ;
        RECT  160.8 0 160.824 0.084 ;
    END
  END xai[204]
  PIN xai[205]
    DIRECTION INPUT ;
    USE SIGNAL ;
    PORT
      LAYER M5 ;
        RECT  160.944 0 160.968 0.084 ;
    END
  END xai[205]
  PIN xai[206]
    DIRECTION INPUT ;
    USE SIGNAL ;
    PORT
      LAYER M5 ;
        RECT  161.088 0 161.112 0.084 ;
    END
  END xai[206]
  PIN xai[207]
    DIRECTION INPUT ;
    USE SIGNAL ;
    PORT
      LAYER M5 ;
        RECT  161.232 0 161.256 0.084 ;
    END
  END xai[207]
  PIN xai[208]
    DIRECTION INPUT ;
    USE SIGNAL ;
    PORT
      LAYER M5 ;
        RECT  161.376 0 161.4 0.084 ;
    END
  END xai[208]
  PIN xai[209]
    DIRECTION INPUT ;
    USE SIGNAL ;
    PORT
      LAYER M5 ;
        RECT  161.52 0 161.544 0.084 ;
    END
  END xai[209]
  PIN xai[20]
    DIRECTION INPUT ;
    USE SIGNAL ;
    PORT
      LAYER M5 ;
        RECT  134.304 0 134.328 0.084 ;
    END
  END xai[20]
  PIN xai[210]
    DIRECTION INPUT ;
    USE SIGNAL ;
    PORT
      LAYER M5 ;
        RECT  161.664 0 161.688 0.084 ;
    END
  END xai[210]
  PIN xai[211]
    DIRECTION INPUT ;
    USE SIGNAL ;
    PORT
      LAYER M5 ;
        RECT  161.808 0 161.832 0.084 ;
    END
  END xai[211]
  PIN xai[212]
    DIRECTION INPUT ;
    USE SIGNAL ;
    PORT
      LAYER M5 ;
        RECT  161.952 0 161.976 0.084 ;
    END
  END xai[212]
  PIN xai[213]
    DIRECTION INPUT ;
    USE SIGNAL ;
    PORT
      LAYER M5 ;
        RECT  162.096 0 162.12 0.084 ;
    END
  END xai[213]
  PIN xai[214]
    DIRECTION INPUT ;
    USE SIGNAL ;
    PORT
      LAYER M5 ;
        RECT  162.24 0 162.264 0.084 ;
    END
  END xai[214]
  PIN xai[215]
    DIRECTION INPUT ;
    USE SIGNAL ;
    PORT
      LAYER M5 ;
        RECT  162.384 0 162.408 0.084 ;
    END
  END xai[215]
  PIN xai[216]
    DIRECTION INPUT ;
    USE SIGNAL ;
    PORT
      LAYER M5 ;
        RECT  162.528 0 162.552 0.084 ;
    END
  END xai[216]
  PIN xai[217]
    DIRECTION INPUT ;
    USE SIGNAL ;
    PORT
      LAYER M5 ;
        RECT  162.672 0 162.696 0.084 ;
    END
  END xai[217]
  PIN xai[218]
    DIRECTION INPUT ;
    USE SIGNAL ;
    PORT
      LAYER M5 ;
        RECT  162.816 0 162.84 0.084 ;
    END
  END xai[218]
  PIN xai[219]
    DIRECTION INPUT ;
    USE SIGNAL ;
    PORT
      LAYER M5 ;
        RECT  162.96 0 162.984 0.084 ;
    END
  END xai[219]
  PIN xai[21]
    DIRECTION INPUT ;
    USE SIGNAL ;
    PORT
      LAYER M5 ;
        RECT  134.448 0 134.472 0.084 ;
    END
  END xai[21]
  PIN xai[220]
    DIRECTION INPUT ;
    USE SIGNAL ;
    PORT
      LAYER M5 ;
        RECT  163.104 0 163.128 0.084 ;
    END
  END xai[220]
  PIN xai[221]
    DIRECTION INPUT ;
    USE SIGNAL ;
    PORT
      LAYER M5 ;
        RECT  163.248 0 163.272 0.084 ;
    END
  END xai[221]
  PIN xai[222]
    DIRECTION INPUT ;
    USE SIGNAL ;
    PORT
      LAYER M5 ;
        RECT  163.392 0 163.416 0.084 ;
    END
  END xai[222]
  PIN xai[223]
    DIRECTION INPUT ;
    USE SIGNAL ;
    PORT
      LAYER M5 ;
        RECT  163.536 0 163.56 0.084 ;
    END
  END xai[223]
  PIN xai[224]
    DIRECTION INPUT ;
    USE SIGNAL ;
    PORT
      LAYER M5 ;
        RECT  163.68 0 163.704 0.084 ;
    END
  END xai[224]
  PIN xai[225]
    DIRECTION INPUT ;
    USE SIGNAL ;
    PORT
      LAYER M5 ;
        RECT  163.824 0 163.848 0.084 ;
    END
  END xai[225]
  PIN xai[226]
    DIRECTION INPUT ;
    USE SIGNAL ;
    PORT
      LAYER M5 ;
        RECT  163.968 0 163.992 0.084 ;
    END
  END xai[226]
  PIN xai[227]
    DIRECTION INPUT ;
    USE SIGNAL ;
    PORT
      LAYER M5 ;
        RECT  164.112 0 164.136 0.084 ;
    END
  END xai[227]
  PIN xai[228]
    DIRECTION INPUT ;
    USE SIGNAL ;
    PORT
      LAYER M5 ;
        RECT  164.256 0 164.28 0.084 ;
    END
  END xai[228]
  PIN xai[229]
    DIRECTION INPUT ;
    USE SIGNAL ;
    PORT
      LAYER M5 ;
        RECT  164.4 0 164.424 0.084 ;
    END
  END xai[229]
  PIN xai[22]
    DIRECTION INPUT ;
    USE SIGNAL ;
    PORT
      LAYER M5 ;
        RECT  134.592 0 134.616 0.084 ;
    END
  END xai[22]
  PIN xai[230]
    DIRECTION INPUT ;
    USE SIGNAL ;
    PORT
      LAYER M5 ;
        RECT  164.544 0 164.568 0.084 ;
    END
  END xai[230]
  PIN xai[231]
    DIRECTION INPUT ;
    USE SIGNAL ;
    PORT
      LAYER M5 ;
        RECT  164.688 0 164.712 0.084 ;
    END
  END xai[231]
  PIN xai[232]
    DIRECTION INPUT ;
    USE SIGNAL ;
    PORT
      LAYER M5 ;
        RECT  164.832 0 164.856 0.084 ;
    END
  END xai[232]
  PIN xai[233]
    DIRECTION INPUT ;
    USE SIGNAL ;
    PORT
      LAYER M5 ;
        RECT  164.976 0 165 0.084 ;
    END
  END xai[233]
  PIN xai[234]
    DIRECTION INPUT ;
    USE SIGNAL ;
    PORT
      LAYER M5 ;
        RECT  165.12 0 165.144 0.084 ;
    END
  END xai[234]
  PIN xai[235]
    DIRECTION INPUT ;
    USE SIGNAL ;
    PORT
      LAYER M5 ;
        RECT  165.264 0 165.288 0.084 ;
    END
  END xai[235]
  PIN xai[236]
    DIRECTION INPUT ;
    USE SIGNAL ;
    PORT
      LAYER M5 ;
        RECT  165.408 0 165.432 0.084 ;
    END
  END xai[236]
  PIN xai[237]
    DIRECTION INPUT ;
    USE SIGNAL ;
    PORT
      LAYER M5 ;
        RECT  165.552 0 165.576 0.084 ;
    END
  END xai[237]
  PIN xai[238]
    DIRECTION INPUT ;
    USE SIGNAL ;
    PORT
      LAYER M5 ;
        RECT  165.696 0 165.72 0.084 ;
    END
  END xai[238]
  PIN xai[239]
    DIRECTION INPUT ;
    USE SIGNAL ;
    PORT
      LAYER M5 ;
        RECT  165.84 0 165.864 0.084 ;
    END
  END xai[239]
  PIN xai[23]
    DIRECTION INPUT ;
    USE SIGNAL ;
    PORT
      LAYER M5 ;
        RECT  134.736 0 134.76 0.084 ;
    END
  END xai[23]
  PIN xai[240]
    DIRECTION INPUT ;
    USE SIGNAL ;
    PORT
      LAYER M5 ;
        RECT  165.984 0 166.008 0.084 ;
    END
  END xai[240]
  PIN xai[241]
    DIRECTION INPUT ;
    USE SIGNAL ;
    PORT
      LAYER M5 ;
        RECT  166.128 0 166.152 0.084 ;
    END
  END xai[241]
  PIN xai[242]
    DIRECTION INPUT ;
    USE SIGNAL ;
    PORT
      LAYER M5 ;
        RECT  166.272 0 166.296 0.084 ;
    END
  END xai[242]
  PIN xai[243]
    DIRECTION INPUT ;
    USE SIGNAL ;
    PORT
      LAYER M5 ;
        RECT  166.416 0 166.44 0.084 ;
    END
  END xai[243]
  PIN xai[244]
    DIRECTION INPUT ;
    USE SIGNAL ;
    PORT
      LAYER M5 ;
        RECT  166.56 0 166.584 0.084 ;
    END
  END xai[244]
  PIN xai[245]
    DIRECTION INPUT ;
    USE SIGNAL ;
    PORT
      LAYER M5 ;
        RECT  166.704 0 166.728 0.084 ;
    END
  END xai[245]
  PIN xai[246]
    DIRECTION INPUT ;
    USE SIGNAL ;
    PORT
      LAYER M5 ;
        RECT  166.848 0 166.872 0.084 ;
    END
  END xai[246]
  PIN xai[247]
    DIRECTION INPUT ;
    USE SIGNAL ;
    PORT
      LAYER M5 ;
        RECT  166.992 0 167.016 0.084 ;
    END
  END xai[247]
  PIN xai[248]
    DIRECTION INPUT ;
    USE SIGNAL ;
    PORT
      LAYER M5 ;
        RECT  167.136 0 167.16 0.084 ;
    END
  END xai[248]
  PIN xai[249]
    DIRECTION INPUT ;
    USE SIGNAL ;
    PORT
      LAYER M5 ;
        RECT  167.28 0 167.304 0.084 ;
    END
  END xai[249]
  PIN xai[24]
    DIRECTION INPUT ;
    USE SIGNAL ;
    PORT
      LAYER M5 ;
        RECT  134.88 0 134.904 0.084 ;
    END
  END xai[24]
  PIN xai[250]
    DIRECTION INPUT ;
    USE SIGNAL ;
    PORT
      LAYER M5 ;
        RECT  167.424 0 167.448 0.084 ;
    END
  END xai[250]
  PIN xai[251]
    DIRECTION INPUT ;
    USE SIGNAL ;
    PORT
      LAYER M5 ;
        RECT  167.568 0 167.592 0.084 ;
    END
  END xai[251]
  PIN xai[252]
    DIRECTION INPUT ;
    USE SIGNAL ;
    PORT
      LAYER M5 ;
        RECT  167.712 0 167.736 0.084 ;
    END
  END xai[252]
  PIN xai[253]
    DIRECTION INPUT ;
    USE SIGNAL ;
    PORT
      LAYER M5 ;
        RECT  167.856 0 167.88 0.084 ;
    END
  END xai[253]
  PIN xai[254]
    DIRECTION INPUT ;
    USE SIGNAL ;
    PORT
      LAYER M5 ;
        RECT  168 0 168.024 0.084 ;
    END
  END xai[254]
  PIN xai[255]
    DIRECTION INPUT ;
    USE SIGNAL ;
    PORT
      LAYER M5 ;
        RECT  168.144 0 168.168 0.084 ;
    END
  END xai[255]
  PIN xai[256]
    DIRECTION INPUT ;
    USE SIGNAL ;
    PORT
      LAYER M5 ;
        RECT  168.288 0 168.312 0.084 ;
    END
  END xai[256]
  PIN xai[257]
    DIRECTION INPUT ;
    USE SIGNAL ;
    PORT
      LAYER M5 ;
        RECT  168.432 0 168.456 0.084 ;
    END
  END xai[257]
  PIN xai[258]
    DIRECTION INPUT ;
    USE SIGNAL ;
    PORT
      LAYER M5 ;
        RECT  168.576 0 168.6 0.084 ;
    END
  END xai[258]
  PIN xai[259]
    DIRECTION INPUT ;
    USE SIGNAL ;
    PORT
      LAYER M5 ;
        RECT  168.72 0 168.744 0.084 ;
    END
  END xai[259]
  PIN xai[25]
    DIRECTION INPUT ;
    USE SIGNAL ;
    PORT
      LAYER M5 ;
        RECT  135.024 0 135.048 0.084 ;
    END
  END xai[25]
  PIN xai[260]
    DIRECTION INPUT ;
    USE SIGNAL ;
    PORT
      LAYER M5 ;
        RECT  168.864 0 168.888 0.084 ;
    END
  END xai[260]
  PIN xai[261]
    DIRECTION INPUT ;
    USE SIGNAL ;
    PORT
      LAYER M5 ;
        RECT  169.008 0 169.032 0.084 ;
    END
  END xai[261]
  PIN xai[262]
    DIRECTION INPUT ;
    USE SIGNAL ;
    PORT
      LAYER M5 ;
        RECT  169.152 0 169.176 0.084 ;
    END
  END xai[262]
  PIN xai[263]
    DIRECTION INPUT ;
    USE SIGNAL ;
    PORT
      LAYER M5 ;
        RECT  169.296 0 169.32 0.084 ;
    END
  END xai[263]
  PIN xai[264]
    DIRECTION INPUT ;
    USE SIGNAL ;
    PORT
      LAYER M5 ;
        RECT  169.44 0 169.464 0.084 ;
    END
  END xai[264]
  PIN xai[265]
    DIRECTION INPUT ;
    USE SIGNAL ;
    PORT
      LAYER M5 ;
        RECT  169.584 0 169.608 0.084 ;
    END
  END xai[265]
  PIN xai[266]
    DIRECTION INPUT ;
    USE SIGNAL ;
    PORT
      LAYER M5 ;
        RECT  169.728 0 169.752 0.084 ;
    END
  END xai[266]
  PIN xai[267]
    DIRECTION INPUT ;
    USE SIGNAL ;
    PORT
      LAYER M5 ;
        RECT  169.872 0 169.896 0.084 ;
    END
  END xai[267]
  PIN xai[268]
    DIRECTION INPUT ;
    USE SIGNAL ;
    PORT
      LAYER M5 ;
        RECT  170.016 0 170.04 0.084 ;
    END
  END xai[268]
  PIN xai[269]
    DIRECTION INPUT ;
    USE SIGNAL ;
    PORT
      LAYER M5 ;
        RECT  170.16 0 170.184 0.084 ;
    END
  END xai[269]
  PIN xai[26]
    DIRECTION INPUT ;
    USE SIGNAL ;
    PORT
      LAYER M5 ;
        RECT  135.168 0 135.192 0.084 ;
    END
  END xai[26]
  PIN xai[270]
    DIRECTION INPUT ;
    USE SIGNAL ;
    PORT
      LAYER M5 ;
        RECT  170.304 0 170.328 0.084 ;
    END
  END xai[270]
  PIN xai[271]
    DIRECTION INPUT ;
    USE SIGNAL ;
    PORT
      LAYER M5 ;
        RECT  170.448 0 170.472 0.084 ;
    END
  END xai[271]
  PIN xai[272]
    DIRECTION INPUT ;
    USE SIGNAL ;
    PORT
      LAYER M5 ;
        RECT  170.592 0 170.616 0.084 ;
    END
  END xai[272]
  PIN xai[273]
    DIRECTION INPUT ;
    USE SIGNAL ;
    PORT
      LAYER M5 ;
        RECT  170.736 0 170.76 0.084 ;
    END
  END xai[273]
  PIN xai[274]
    DIRECTION INPUT ;
    USE SIGNAL ;
    PORT
      LAYER M5 ;
        RECT  170.88 0 170.904 0.084 ;
    END
  END xai[274]
  PIN xai[275]
    DIRECTION INPUT ;
    USE SIGNAL ;
    PORT
      LAYER M5 ;
        RECT  171.024 0 171.048 0.084 ;
    END
  END xai[275]
  PIN xai[276]
    DIRECTION INPUT ;
    USE SIGNAL ;
    PORT
      LAYER M5 ;
        RECT  171.168 0 171.192 0.084 ;
    END
  END xai[276]
  PIN xai[277]
    DIRECTION INPUT ;
    USE SIGNAL ;
    PORT
      LAYER M5 ;
        RECT  171.312 0 171.336 0.084 ;
    END
  END xai[277]
  PIN xai[278]
    DIRECTION INPUT ;
    USE SIGNAL ;
    PORT
      LAYER M5 ;
        RECT  171.456 0 171.48 0.084 ;
    END
  END xai[278]
  PIN xai[279]
    DIRECTION INPUT ;
    USE SIGNAL ;
    PORT
      LAYER M5 ;
        RECT  171.6 0 171.624 0.084 ;
    END
  END xai[279]
  PIN xai[27]
    DIRECTION INPUT ;
    USE SIGNAL ;
    PORT
      LAYER M5 ;
        RECT  135.312 0 135.336 0.084 ;
    END
  END xai[27]
  PIN xai[280]
    DIRECTION INPUT ;
    USE SIGNAL ;
    PORT
      LAYER M5 ;
        RECT  171.744 0 171.768 0.084 ;
    END
  END xai[280]
  PIN xai[281]
    DIRECTION INPUT ;
    USE SIGNAL ;
    PORT
      LAYER M5 ;
        RECT  171.888 0 171.912 0.084 ;
    END
  END xai[281]
  PIN xai[282]
    DIRECTION INPUT ;
    USE SIGNAL ;
    PORT
      LAYER M5 ;
        RECT  172.032 0 172.056 0.084 ;
    END
  END xai[282]
  PIN xai[28]
    DIRECTION INPUT ;
    USE SIGNAL ;
    PORT
      LAYER M5 ;
        RECT  135.456 0 135.48 0.084 ;
    END
  END xai[28]
  PIN xai[29]
    DIRECTION INPUT ;
    USE SIGNAL ;
    PORT
      LAYER M5 ;
        RECT  135.6 0 135.624 0.084 ;
    END
  END xai[29]
  PIN xai[2]
    DIRECTION INPUT ;
    USE SIGNAL ;
    PORT
      LAYER M5 ;
        RECT  131.712 0 131.736 0.084 ;
    END
  END xai[2]
  PIN xai[30]
    DIRECTION INPUT ;
    USE SIGNAL ;
    PORT
      LAYER M5 ;
        RECT  135.744 0 135.768 0.084 ;
    END
  END xai[30]
  PIN xai[31]
    DIRECTION INPUT ;
    USE SIGNAL ;
    PORT
      LAYER M5 ;
        RECT  135.888 0 135.912 0.084 ;
    END
  END xai[31]
  PIN xai[32]
    DIRECTION INPUT ;
    USE SIGNAL ;
    PORT
      LAYER M5 ;
        RECT  136.032 0 136.056 0.084 ;
    END
  END xai[32]
  PIN xai[33]
    DIRECTION INPUT ;
    USE SIGNAL ;
    PORT
      LAYER M5 ;
        RECT  136.176 0 136.2 0.084 ;
    END
  END xai[33]
  PIN xai[34]
    DIRECTION INPUT ;
    USE SIGNAL ;
    PORT
      LAYER M5 ;
        RECT  136.32 0 136.344 0.084 ;
    END
  END xai[34]
  PIN xai[35]
    DIRECTION INPUT ;
    USE SIGNAL ;
    PORT
      LAYER M5 ;
        RECT  136.464 0 136.488 0.084 ;
    END
  END xai[35]
  PIN xai[36]
    DIRECTION INPUT ;
    USE SIGNAL ;
    PORT
      LAYER M5 ;
        RECT  136.608 0 136.632 0.084 ;
    END
  END xai[36]
  PIN xai[37]
    DIRECTION INPUT ;
    USE SIGNAL ;
    PORT
      LAYER M5 ;
        RECT  136.752 0 136.776 0.084 ;
    END
  END xai[37]
  PIN xai[38]
    DIRECTION INPUT ;
    USE SIGNAL ;
    PORT
      LAYER M5 ;
        RECT  136.896 0 136.92 0.084 ;
    END
  END xai[38]
  PIN xai[39]
    DIRECTION INPUT ;
    USE SIGNAL ;
    PORT
      LAYER M5 ;
        RECT  137.04 0 137.064 0.084 ;
    END
  END xai[39]
  PIN xai[3]
    DIRECTION INPUT ;
    USE SIGNAL ;
    PORT
      LAYER M5 ;
        RECT  131.856 0 131.88 0.084 ;
    END
  END xai[3]
  PIN xai[40]
    DIRECTION INPUT ;
    USE SIGNAL ;
    PORT
      LAYER M5 ;
        RECT  137.184 0 137.208 0.084 ;
    END
  END xai[40]
  PIN xai[41]
    DIRECTION INPUT ;
    USE SIGNAL ;
    PORT
      LAYER M5 ;
        RECT  137.328 0 137.352 0.084 ;
    END
  END xai[41]
  PIN xai[42]
    DIRECTION INPUT ;
    USE SIGNAL ;
    PORT
      LAYER M5 ;
        RECT  137.472 0 137.496 0.084 ;
    END
  END xai[42]
  PIN xai[43]
    DIRECTION INPUT ;
    USE SIGNAL ;
    PORT
      LAYER M5 ;
        RECT  137.616 0 137.64 0.084 ;
    END
  END xai[43]
  PIN xai[44]
    DIRECTION INPUT ;
    USE SIGNAL ;
    PORT
      LAYER M5 ;
        RECT  137.76 0 137.784 0.084 ;
    END
  END xai[44]
  PIN xai[45]
    DIRECTION INPUT ;
    USE SIGNAL ;
    PORT
      LAYER M5 ;
        RECT  137.904 0 137.928 0.084 ;
    END
  END xai[45]
  PIN xai[46]
    DIRECTION INPUT ;
    USE SIGNAL ;
    PORT
      LAYER M5 ;
        RECT  138.048 0 138.072 0.084 ;
    END
  END xai[46]
  PIN xai[47]
    DIRECTION INPUT ;
    USE SIGNAL ;
    PORT
      LAYER M5 ;
        RECT  138.192 0 138.216 0.084 ;
    END
  END xai[47]
  PIN xai[48]
    DIRECTION INPUT ;
    USE SIGNAL ;
    PORT
      LAYER M5 ;
        RECT  138.336 0 138.36 0.084 ;
    END
  END xai[48]
  PIN xai[49]
    DIRECTION INPUT ;
    USE SIGNAL ;
    PORT
      LAYER M5 ;
        RECT  138.48 0 138.504 0.084 ;
    END
  END xai[49]
  PIN xai[4]
    DIRECTION INPUT ;
    USE SIGNAL ;
    PORT
      LAYER M5 ;
        RECT  132 0 132.024 0.084 ;
    END
  END xai[4]
  PIN xai[50]
    DIRECTION INPUT ;
    USE SIGNAL ;
    PORT
      LAYER M5 ;
        RECT  138.624 0 138.648 0.084 ;
    END
  END xai[50]
  PIN xai[51]
    DIRECTION INPUT ;
    USE SIGNAL ;
    PORT
      LAYER M5 ;
        RECT  138.768 0 138.792 0.084 ;
    END
  END xai[51]
  PIN xai[52]
    DIRECTION INPUT ;
    USE SIGNAL ;
    PORT
      LAYER M5 ;
        RECT  138.912 0 138.936 0.084 ;
    END
  END xai[52]
  PIN xai[53]
    DIRECTION INPUT ;
    USE SIGNAL ;
    PORT
      LAYER M5 ;
        RECT  139.056 0 139.08 0.084 ;
    END
  END xai[53]
  PIN xai[54]
    DIRECTION INPUT ;
    USE SIGNAL ;
    PORT
      LAYER M5 ;
        RECT  139.2 0 139.224 0.084 ;
    END
  END xai[54]
  PIN xai[55]
    DIRECTION INPUT ;
    USE SIGNAL ;
    PORT
      LAYER M5 ;
        RECT  139.344 0 139.368 0.084 ;
    END
  END xai[55]
  PIN xai[56]
    DIRECTION INPUT ;
    USE SIGNAL ;
    PORT
      LAYER M5 ;
        RECT  139.488 0 139.512 0.084 ;
    END
  END xai[56]
  PIN xai[57]
    DIRECTION INPUT ;
    USE SIGNAL ;
    PORT
      LAYER M5 ;
        RECT  139.632 0 139.656 0.084 ;
    END
  END xai[57]
  PIN xai[58]
    DIRECTION INPUT ;
    USE SIGNAL ;
    PORT
      LAYER M5 ;
        RECT  139.776 0 139.8 0.084 ;
    END
  END xai[58]
  PIN xai[59]
    DIRECTION INPUT ;
    USE SIGNAL ;
    PORT
      LAYER M5 ;
        RECT  139.92 0 139.944 0.084 ;
    END
  END xai[59]
  PIN xai[5]
    DIRECTION INPUT ;
    USE SIGNAL ;
    PORT
      LAYER M5 ;
        RECT  132.144 0 132.168 0.084 ;
    END
  END xai[5]
  PIN xai[60]
    DIRECTION INPUT ;
    USE SIGNAL ;
    PORT
      LAYER M5 ;
        RECT  140.064 0 140.088 0.084 ;
    END
  END xai[60]
  PIN xai[61]
    DIRECTION INPUT ;
    USE SIGNAL ;
    PORT
      LAYER M5 ;
        RECT  140.208 0 140.232 0.084 ;
    END
  END xai[61]
  PIN xai[62]
    DIRECTION INPUT ;
    USE SIGNAL ;
    PORT
      LAYER M5 ;
        RECT  140.352 0 140.376 0.084 ;
    END
  END xai[62]
  PIN xai[63]
    DIRECTION INPUT ;
    USE SIGNAL ;
    PORT
      LAYER M5 ;
        RECT  140.496 0 140.52 0.084 ;
    END
  END xai[63]
  PIN xai[64]
    DIRECTION INPUT ;
    USE SIGNAL ;
    PORT
      LAYER M5 ;
        RECT  140.64 0 140.664 0.084 ;
    END
  END xai[64]
  PIN xai[65]
    DIRECTION INPUT ;
    USE SIGNAL ;
    PORT
      LAYER M5 ;
        RECT  140.784 0 140.808 0.084 ;
    END
  END xai[65]
  PIN xai[66]
    DIRECTION INPUT ;
    USE SIGNAL ;
    PORT
      LAYER M5 ;
        RECT  140.928 0 140.952 0.084 ;
    END
  END xai[66]
  PIN xai[67]
    DIRECTION INPUT ;
    USE SIGNAL ;
    PORT
      LAYER M5 ;
        RECT  141.072 0 141.096 0.084 ;
    END
  END xai[67]
  PIN xai[68]
    DIRECTION INPUT ;
    USE SIGNAL ;
    PORT
      LAYER M5 ;
        RECT  141.216 0 141.24 0.084 ;
    END
  END xai[68]
  PIN xai[69]
    DIRECTION INPUT ;
    USE SIGNAL ;
    PORT
      LAYER M5 ;
        RECT  141.36 0 141.384 0.084 ;
    END
  END xai[69]
  PIN xai[6]
    DIRECTION INPUT ;
    USE SIGNAL ;
    PORT
      LAYER M5 ;
        RECT  132.288 0 132.312 0.084 ;
    END
  END xai[6]
  PIN xai[70]
    DIRECTION INPUT ;
    USE SIGNAL ;
    PORT
      LAYER M5 ;
        RECT  141.504 0 141.528 0.084 ;
    END
  END xai[70]
  PIN xai[71]
    DIRECTION INPUT ;
    USE SIGNAL ;
    PORT
      LAYER M5 ;
        RECT  141.648 0 141.672 0.084 ;
    END
  END xai[71]
  PIN xai[72]
    DIRECTION INPUT ;
    USE SIGNAL ;
    PORT
      LAYER M5 ;
        RECT  141.792 0 141.816 0.084 ;
    END
  END xai[72]
  PIN xai[73]
    DIRECTION INPUT ;
    USE SIGNAL ;
    PORT
      LAYER M5 ;
        RECT  141.936 0 141.96 0.084 ;
    END
  END xai[73]
  PIN xai[74]
    DIRECTION INPUT ;
    USE SIGNAL ;
    PORT
      LAYER M5 ;
        RECT  142.08 0 142.104 0.084 ;
    END
  END xai[74]
  PIN xai[75]
    DIRECTION INPUT ;
    USE SIGNAL ;
    PORT
      LAYER M5 ;
        RECT  142.224 0 142.248 0.084 ;
    END
  END xai[75]
  PIN xai[76]
    DIRECTION INPUT ;
    USE SIGNAL ;
    PORT
      LAYER M5 ;
        RECT  142.368 0 142.392 0.084 ;
    END
  END xai[76]
  PIN xai[77]
    DIRECTION INPUT ;
    USE SIGNAL ;
    PORT
      LAYER M5 ;
        RECT  142.512 0 142.536 0.084 ;
    END
  END xai[77]
  PIN xai[78]
    DIRECTION INPUT ;
    USE SIGNAL ;
    PORT
      LAYER M5 ;
        RECT  142.656 0 142.68 0.084 ;
    END
  END xai[78]
  PIN xai[79]
    DIRECTION INPUT ;
    USE SIGNAL ;
    PORT
      LAYER M5 ;
        RECT  142.8 0 142.824 0.084 ;
    END
  END xai[79]
  PIN xai[7]
    DIRECTION INPUT ;
    USE SIGNAL ;
    PORT
      LAYER M5 ;
        RECT  132.432 0 132.456 0.084 ;
    END
  END xai[7]
  PIN xai[80]
    DIRECTION INPUT ;
    USE SIGNAL ;
    PORT
      LAYER M5 ;
        RECT  142.944 0 142.968 0.084 ;
    END
  END xai[80]
  PIN xai[81]
    DIRECTION INPUT ;
    USE SIGNAL ;
    PORT
      LAYER M5 ;
        RECT  143.088 0 143.112 0.084 ;
    END
  END xai[81]
  PIN xai[82]
    DIRECTION INPUT ;
    USE SIGNAL ;
    PORT
      LAYER M5 ;
        RECT  143.232 0 143.256 0.084 ;
    END
  END xai[82]
  PIN xai[83]
    DIRECTION INPUT ;
    USE SIGNAL ;
    PORT
      LAYER M5 ;
        RECT  143.376 0 143.4 0.084 ;
    END
  END xai[83]
  PIN xai[84]
    DIRECTION INPUT ;
    USE SIGNAL ;
    PORT
      LAYER M5 ;
        RECT  143.52 0 143.544 0.084 ;
    END
  END xai[84]
  PIN xai[85]
    DIRECTION INPUT ;
    USE SIGNAL ;
    PORT
      LAYER M5 ;
        RECT  143.664 0 143.688 0.084 ;
    END
  END xai[85]
  PIN xai[86]
    DIRECTION INPUT ;
    USE SIGNAL ;
    PORT
      LAYER M5 ;
        RECT  143.808 0 143.832 0.084 ;
    END
  END xai[86]
  PIN xai[87]
    DIRECTION INPUT ;
    USE SIGNAL ;
    PORT
      LAYER M5 ;
        RECT  143.952 0 143.976 0.084 ;
    END
  END xai[87]
  PIN xai[88]
    DIRECTION INPUT ;
    USE SIGNAL ;
    PORT
      LAYER M5 ;
        RECT  144.096 0 144.12 0.084 ;
    END
  END xai[88]
  PIN xai[89]
    DIRECTION INPUT ;
    USE SIGNAL ;
    PORT
      LAYER M5 ;
        RECT  144.24 0 144.264 0.084 ;
    END
  END xai[89]
  PIN xai[8]
    DIRECTION INPUT ;
    USE SIGNAL ;
    PORT
      LAYER M5 ;
        RECT  132.576 0 132.6 0.084 ;
    END
  END xai[8]
  PIN xai[90]
    DIRECTION INPUT ;
    USE SIGNAL ;
    PORT
      LAYER M5 ;
        RECT  144.384 0 144.408 0.084 ;
    END
  END xai[90]
  PIN xai[91]
    DIRECTION INPUT ;
    USE SIGNAL ;
    PORT
      LAYER M5 ;
        RECT  144.528 0 144.552 0.084 ;
    END
  END xai[91]
  PIN xai[92]
    DIRECTION INPUT ;
    USE SIGNAL ;
    PORT
      LAYER M5 ;
        RECT  144.672 0 144.696 0.084 ;
    END
  END xai[92]
  PIN xai[93]
    DIRECTION INPUT ;
    USE SIGNAL ;
    PORT
      LAYER M5 ;
        RECT  144.816 0 144.84 0.084 ;
    END
  END xai[93]
  PIN xai[94]
    DIRECTION INPUT ;
    USE SIGNAL ;
    PORT
      LAYER M5 ;
        RECT  144.96 0 144.984 0.084 ;
    END
  END xai[94]
  PIN xai[95]
    DIRECTION INPUT ;
    USE SIGNAL ;
    PORT
      LAYER M5 ;
        RECT  145.104 0 145.128 0.084 ;
    END
  END xai[95]
  PIN xai[96]
    DIRECTION INPUT ;
    USE SIGNAL ;
    PORT
      LAYER M5 ;
        RECT  145.248 0 145.272 0.084 ;
    END
  END xai[96]
  PIN xai[97]
    DIRECTION INPUT ;
    USE SIGNAL ;
    PORT
      LAYER M5 ;
        RECT  145.392 0 145.416 0.084 ;
    END
  END xai[97]
  PIN xai[98]
    DIRECTION INPUT ;
    USE SIGNAL ;
    PORT
      LAYER M5 ;
        RECT  145.536 0 145.56 0.084 ;
    END
  END xai[98]
  PIN xai[99]
    DIRECTION INPUT ;
    USE SIGNAL ;
    PORT
      LAYER M5 ;
        RECT  145.68 0 145.704 0.084 ;
    END
  END xai[99]
  PIN xai[9]
    DIRECTION INPUT ;
    USE SIGNAL ;
    PORT
      LAYER M5 ;
        RECT  132.72 0 132.744 0.084 ;
    END
  END xai[9]
  PIN xb[0]
    DIRECTION OUTPUT ;
    USE SIGNAL ;
    PORT
      LAYER M5 ;
        RECT  90.288 30.156 90.312 30.24 ;
    END
  END xb[0]
  PIN xb[100]
    DIRECTION OUTPUT ;
    USE SIGNAL ;
    PORT
      LAYER M5 ;
        RECT  104.688 30.156 104.712 30.24 ;
    END
  END xb[100]
  PIN xb[101]
    DIRECTION OUTPUT ;
    USE SIGNAL ;
    PORT
      LAYER M5 ;
        RECT  104.832 30.156 104.856 30.24 ;
    END
  END xb[101]
  PIN xb[102]
    DIRECTION OUTPUT ;
    USE SIGNAL ;
    PORT
      LAYER M5 ;
        RECT  104.976 30.156 105 30.24 ;
    END
  END xb[102]
  PIN xb[103]
    DIRECTION OUTPUT ;
    USE SIGNAL ;
    PORT
      LAYER M5 ;
        RECT  105.12 30.156 105.144 30.24 ;
    END
  END xb[103]
  PIN xb[104]
    DIRECTION OUTPUT ;
    USE SIGNAL ;
    PORT
      LAYER M5 ;
        RECT  105.264 30.156 105.288 30.24 ;
    END
  END xb[104]
  PIN xb[105]
    DIRECTION OUTPUT ;
    USE SIGNAL ;
    PORT
      LAYER M5 ;
        RECT  105.408 30.156 105.432 30.24 ;
    END
  END xb[105]
  PIN xb[106]
    DIRECTION OUTPUT ;
    USE SIGNAL ;
    PORT
      LAYER M5 ;
        RECT  105.552 30.156 105.576 30.24 ;
    END
  END xb[106]
  PIN xb[107]
    DIRECTION OUTPUT ;
    USE SIGNAL ;
    PORT
      LAYER M5 ;
        RECT  105.696 30.156 105.72 30.24 ;
    END
  END xb[107]
  PIN xb[108]
    DIRECTION OUTPUT ;
    USE SIGNAL ;
    PORT
      LAYER M5 ;
        RECT  105.84 30.156 105.864 30.24 ;
    END
  END xb[108]
  PIN xb[109]
    DIRECTION OUTPUT ;
    USE SIGNAL ;
    PORT
      LAYER M5 ;
        RECT  105.984 30.156 106.008 30.24 ;
    END
  END xb[109]
  PIN xb[10]
    DIRECTION OUTPUT ;
    USE SIGNAL ;
    PORT
      LAYER M5 ;
        RECT  91.728 30.156 91.752 30.24 ;
    END
  END xb[10]
  PIN xb[110]
    DIRECTION OUTPUT ;
    USE SIGNAL ;
    PORT
      LAYER M5 ;
        RECT  106.128 30.156 106.152 30.24 ;
    END
  END xb[110]
  PIN xb[111]
    DIRECTION OUTPUT ;
    USE SIGNAL ;
    PORT
      LAYER M5 ;
        RECT  106.272 30.156 106.296 30.24 ;
    END
  END xb[111]
  PIN xb[112]
    DIRECTION OUTPUT ;
    USE SIGNAL ;
    PORT
      LAYER M5 ;
        RECT  106.416 30.156 106.44 30.24 ;
    END
  END xb[112]
  PIN xb[113]
    DIRECTION OUTPUT ;
    USE SIGNAL ;
    PORT
      LAYER M5 ;
        RECT  106.56 30.156 106.584 30.24 ;
    END
  END xb[113]
  PIN xb[114]
    DIRECTION OUTPUT ;
    USE SIGNAL ;
    PORT
      LAYER M5 ;
        RECT  106.704 30.156 106.728 30.24 ;
    END
  END xb[114]
  PIN xb[115]
    DIRECTION OUTPUT ;
    USE SIGNAL ;
    PORT
      LAYER M5 ;
        RECT  106.848 30.156 106.872 30.24 ;
    END
  END xb[115]
  PIN xb[116]
    DIRECTION OUTPUT ;
    USE SIGNAL ;
    PORT
      LAYER M5 ;
        RECT  106.992 30.156 107.016 30.24 ;
    END
  END xb[116]
  PIN xb[117]
    DIRECTION OUTPUT ;
    USE SIGNAL ;
    PORT
      LAYER M5 ;
        RECT  107.136 30.156 107.16 30.24 ;
    END
  END xb[117]
  PIN xb[118]
    DIRECTION OUTPUT ;
    USE SIGNAL ;
    PORT
      LAYER M5 ;
        RECT  107.28 30.156 107.304 30.24 ;
    END
  END xb[118]
  PIN xb[119]
    DIRECTION OUTPUT ;
    USE SIGNAL ;
    PORT
      LAYER M5 ;
        RECT  107.424 30.156 107.448 30.24 ;
    END
  END xb[119]
  PIN xb[11]
    DIRECTION OUTPUT ;
    USE SIGNAL ;
    PORT
      LAYER M5 ;
        RECT  91.872 30.156 91.896 30.24 ;
    END
  END xb[11]
  PIN xb[120]
    DIRECTION OUTPUT ;
    USE SIGNAL ;
    PORT
      LAYER M5 ;
        RECT  107.568 30.156 107.592 30.24 ;
    END
  END xb[120]
  PIN xb[121]
    DIRECTION OUTPUT ;
    USE SIGNAL ;
    PORT
      LAYER M5 ;
        RECT  107.712 30.156 107.736 30.24 ;
    END
  END xb[121]
  PIN xb[122]
    DIRECTION OUTPUT ;
    USE SIGNAL ;
    PORT
      LAYER M5 ;
        RECT  107.856 30.156 107.88 30.24 ;
    END
  END xb[122]
  PIN xb[123]
    DIRECTION OUTPUT ;
    USE SIGNAL ;
    PORT
      LAYER M5 ;
        RECT  108 30.156 108.024 30.24 ;
    END
  END xb[123]
  PIN xb[124]
    DIRECTION OUTPUT ;
    USE SIGNAL ;
    PORT
      LAYER M5 ;
        RECT  108.144 30.156 108.168 30.24 ;
    END
  END xb[124]
  PIN xb[125]
    DIRECTION OUTPUT ;
    USE SIGNAL ;
    PORT
      LAYER M5 ;
        RECT  108.288 30.156 108.312 30.24 ;
    END
  END xb[125]
  PIN xb[126]
    DIRECTION OUTPUT ;
    USE SIGNAL ;
    PORT
      LAYER M5 ;
        RECT  108.432 30.156 108.456 30.24 ;
    END
  END xb[126]
  PIN xb[127]
    DIRECTION OUTPUT ;
    USE SIGNAL ;
    PORT
      LAYER M5 ;
        RECT  108.576 30.156 108.6 30.24 ;
    END
  END xb[127]
  PIN xb[128]
    DIRECTION OUTPUT ;
    USE SIGNAL ;
    PORT
      LAYER M5 ;
        RECT  108.72 30.156 108.744 30.24 ;
    END
  END xb[128]
  PIN xb[129]
    DIRECTION OUTPUT ;
    USE SIGNAL ;
    PORT
      LAYER M5 ;
        RECT  108.864 30.156 108.888 30.24 ;
    END
  END xb[129]
  PIN xb[12]
    DIRECTION OUTPUT ;
    USE SIGNAL ;
    PORT
      LAYER M5 ;
        RECT  92.016 30.156 92.04 30.24 ;
    END
  END xb[12]
  PIN xb[130]
    DIRECTION OUTPUT ;
    USE SIGNAL ;
    PORT
      LAYER M5 ;
        RECT  109.008 30.156 109.032 30.24 ;
    END
  END xb[130]
  PIN xb[131]
    DIRECTION OUTPUT ;
    USE SIGNAL ;
    PORT
      LAYER M5 ;
        RECT  109.152 30.156 109.176 30.24 ;
    END
  END xb[131]
  PIN xb[132]
    DIRECTION OUTPUT ;
    USE SIGNAL ;
    PORT
      LAYER M5 ;
        RECT  109.296 30.156 109.32 30.24 ;
    END
  END xb[132]
  PIN xb[133]
    DIRECTION OUTPUT ;
    USE SIGNAL ;
    PORT
      LAYER M5 ;
        RECT  109.44 30.156 109.464 30.24 ;
    END
  END xb[133]
  PIN xb[134]
    DIRECTION OUTPUT ;
    USE SIGNAL ;
    PORT
      LAYER M5 ;
        RECT  109.584 30.156 109.608 30.24 ;
    END
  END xb[134]
  PIN xb[135]
    DIRECTION OUTPUT ;
    USE SIGNAL ;
    PORT
      LAYER M5 ;
        RECT  109.728 30.156 109.752 30.24 ;
    END
  END xb[135]
  PIN xb[136]
    DIRECTION OUTPUT ;
    USE SIGNAL ;
    PORT
      LAYER M5 ;
        RECT  109.872 30.156 109.896 30.24 ;
    END
  END xb[136]
  PIN xb[137]
    DIRECTION OUTPUT ;
    USE SIGNAL ;
    PORT
      LAYER M5 ;
        RECT  110.016 30.156 110.04 30.24 ;
    END
  END xb[137]
  PIN xb[138]
    DIRECTION OUTPUT ;
    USE SIGNAL ;
    PORT
      LAYER M5 ;
        RECT  110.16 30.156 110.184 30.24 ;
    END
  END xb[138]
  PIN xb[139]
    DIRECTION OUTPUT ;
    USE SIGNAL ;
    PORT
      LAYER M5 ;
        RECT  110.304 30.156 110.328 30.24 ;
    END
  END xb[139]
  PIN xb[13]
    DIRECTION OUTPUT ;
    USE SIGNAL ;
    PORT
      LAYER M5 ;
        RECT  92.16 30.156 92.184 30.24 ;
    END
  END xb[13]
  PIN xb[140]
    DIRECTION OUTPUT ;
    USE SIGNAL ;
    PORT
      LAYER M5 ;
        RECT  110.448 30.156 110.472 30.24 ;
    END
  END xb[140]
  PIN xb[141]
    DIRECTION OUTPUT ;
    USE SIGNAL ;
    PORT
      LAYER M5 ;
        RECT  110.592 30.156 110.616 30.24 ;
    END
  END xb[141]
  PIN xb[142]
    DIRECTION OUTPUT ;
    USE SIGNAL ;
    PORT
      LAYER M5 ;
        RECT  110.736 30.156 110.76 30.24 ;
    END
  END xb[142]
  PIN xb[143]
    DIRECTION OUTPUT ;
    USE SIGNAL ;
    PORT
      LAYER M5 ;
        RECT  110.88 30.156 110.904 30.24 ;
    END
  END xb[143]
  PIN xb[144]
    DIRECTION OUTPUT ;
    USE SIGNAL ;
    PORT
      LAYER M5 ;
        RECT  111.024 30.156 111.048 30.24 ;
    END
  END xb[144]
  PIN xb[145]
    DIRECTION OUTPUT ;
    USE SIGNAL ;
    PORT
      LAYER M5 ;
        RECT  111.168 30.156 111.192 30.24 ;
    END
  END xb[145]
  PIN xb[146]
    DIRECTION OUTPUT ;
    USE SIGNAL ;
    PORT
      LAYER M5 ;
        RECT  111.312 30.156 111.336 30.24 ;
    END
  END xb[146]
  PIN xb[147]
    DIRECTION OUTPUT ;
    USE SIGNAL ;
    PORT
      LAYER M5 ;
        RECT  111.456 30.156 111.48 30.24 ;
    END
  END xb[147]
  PIN xb[148]
    DIRECTION OUTPUT ;
    USE SIGNAL ;
    PORT
      LAYER M5 ;
        RECT  111.6 30.156 111.624 30.24 ;
    END
  END xb[148]
  PIN xb[149]
    DIRECTION OUTPUT ;
    USE SIGNAL ;
    PORT
      LAYER M5 ;
        RECT  111.744 30.156 111.768 30.24 ;
    END
  END xb[149]
  PIN xb[14]
    DIRECTION OUTPUT ;
    USE SIGNAL ;
    PORT
      LAYER M5 ;
        RECT  92.304 30.156 92.328 30.24 ;
    END
  END xb[14]
  PIN xb[150]
    DIRECTION OUTPUT ;
    USE SIGNAL ;
    PORT
      LAYER M5 ;
        RECT  111.888 30.156 111.912 30.24 ;
    END
  END xb[150]
  PIN xb[151]
    DIRECTION OUTPUT ;
    USE SIGNAL ;
    PORT
      LAYER M5 ;
        RECT  112.032 30.156 112.056 30.24 ;
    END
  END xb[151]
  PIN xb[152]
    DIRECTION OUTPUT ;
    USE SIGNAL ;
    PORT
      LAYER M5 ;
        RECT  112.176 30.156 112.2 30.24 ;
    END
  END xb[152]
  PIN xb[153]
    DIRECTION OUTPUT ;
    USE SIGNAL ;
    PORT
      LAYER M5 ;
        RECT  112.32 30.156 112.344 30.24 ;
    END
  END xb[153]
  PIN xb[154]
    DIRECTION OUTPUT ;
    USE SIGNAL ;
    PORT
      LAYER M5 ;
        RECT  112.464 30.156 112.488 30.24 ;
    END
  END xb[154]
  PIN xb[155]
    DIRECTION OUTPUT ;
    USE SIGNAL ;
    PORT
      LAYER M5 ;
        RECT  112.608 30.156 112.632 30.24 ;
    END
  END xb[155]
  PIN xb[156]
    DIRECTION OUTPUT ;
    USE SIGNAL ;
    PORT
      LAYER M5 ;
        RECT  112.752 30.156 112.776 30.24 ;
    END
  END xb[156]
  PIN xb[157]
    DIRECTION OUTPUT ;
    USE SIGNAL ;
    PORT
      LAYER M5 ;
        RECT  112.896 30.156 112.92 30.24 ;
    END
  END xb[157]
  PIN xb[158]
    DIRECTION OUTPUT ;
    USE SIGNAL ;
    PORT
      LAYER M5 ;
        RECT  113.04 30.156 113.064 30.24 ;
    END
  END xb[158]
  PIN xb[159]
    DIRECTION OUTPUT ;
    USE SIGNAL ;
    PORT
      LAYER M5 ;
        RECT  113.184 30.156 113.208 30.24 ;
    END
  END xb[159]
  PIN xb[15]
    DIRECTION OUTPUT ;
    USE SIGNAL ;
    PORT
      LAYER M5 ;
        RECT  92.448 30.156 92.472 30.24 ;
    END
  END xb[15]
  PIN xb[160]
    DIRECTION OUTPUT ;
    USE SIGNAL ;
    PORT
      LAYER M5 ;
        RECT  113.328 30.156 113.352 30.24 ;
    END
  END xb[160]
  PIN xb[161]
    DIRECTION OUTPUT ;
    USE SIGNAL ;
    PORT
      LAYER M5 ;
        RECT  113.472 30.156 113.496 30.24 ;
    END
  END xb[161]
  PIN xb[162]
    DIRECTION OUTPUT ;
    USE SIGNAL ;
    PORT
      LAYER M5 ;
        RECT  113.616 30.156 113.64 30.24 ;
    END
  END xb[162]
  PIN xb[163]
    DIRECTION OUTPUT ;
    USE SIGNAL ;
    PORT
      LAYER M5 ;
        RECT  113.76 30.156 113.784 30.24 ;
    END
  END xb[163]
  PIN xb[164]
    DIRECTION OUTPUT ;
    USE SIGNAL ;
    PORT
      LAYER M5 ;
        RECT  113.904 30.156 113.928 30.24 ;
    END
  END xb[164]
  PIN xb[165]
    DIRECTION OUTPUT ;
    USE SIGNAL ;
    PORT
      LAYER M5 ;
        RECT  114.048 30.156 114.072 30.24 ;
    END
  END xb[165]
  PIN xb[166]
    DIRECTION OUTPUT ;
    USE SIGNAL ;
    PORT
      LAYER M5 ;
        RECT  114.192 30.156 114.216 30.24 ;
    END
  END xb[166]
  PIN xb[167]
    DIRECTION OUTPUT ;
    USE SIGNAL ;
    PORT
      LAYER M5 ;
        RECT  114.336 30.156 114.36 30.24 ;
    END
  END xb[167]
  PIN xb[168]
    DIRECTION OUTPUT ;
    USE SIGNAL ;
    PORT
      LAYER M5 ;
        RECT  114.48 30.156 114.504 30.24 ;
    END
  END xb[168]
  PIN xb[169]
    DIRECTION OUTPUT ;
    USE SIGNAL ;
    PORT
      LAYER M5 ;
        RECT  114.624 30.156 114.648 30.24 ;
    END
  END xb[169]
  PIN xb[16]
    DIRECTION OUTPUT ;
    USE SIGNAL ;
    PORT
      LAYER M5 ;
        RECT  92.592 30.156 92.616 30.24 ;
    END
  END xb[16]
  PIN xb[170]
    DIRECTION OUTPUT ;
    USE SIGNAL ;
    PORT
      LAYER M5 ;
        RECT  114.768 30.156 114.792 30.24 ;
    END
  END xb[170]
  PIN xb[171]
    DIRECTION OUTPUT ;
    USE SIGNAL ;
    PORT
      LAYER M5 ;
        RECT  114.912 30.156 114.936 30.24 ;
    END
  END xb[171]
  PIN xb[172]
    DIRECTION OUTPUT ;
    USE SIGNAL ;
    PORT
      LAYER M5 ;
        RECT  115.056 30.156 115.08 30.24 ;
    END
  END xb[172]
  PIN xb[173]
    DIRECTION OUTPUT ;
    USE SIGNAL ;
    PORT
      LAYER M5 ;
        RECT  115.2 30.156 115.224 30.24 ;
    END
  END xb[173]
  PIN xb[174]
    DIRECTION OUTPUT ;
    USE SIGNAL ;
    PORT
      LAYER M5 ;
        RECT  115.344 30.156 115.368 30.24 ;
    END
  END xb[174]
  PIN xb[175]
    DIRECTION OUTPUT ;
    USE SIGNAL ;
    PORT
      LAYER M5 ;
        RECT  115.488 30.156 115.512 30.24 ;
    END
  END xb[175]
  PIN xb[176]
    DIRECTION OUTPUT ;
    USE SIGNAL ;
    PORT
      LAYER M5 ;
        RECT  115.632 30.156 115.656 30.24 ;
    END
  END xb[176]
  PIN xb[177]
    DIRECTION OUTPUT ;
    USE SIGNAL ;
    PORT
      LAYER M5 ;
        RECT  115.776 30.156 115.8 30.24 ;
    END
  END xb[177]
  PIN xb[178]
    DIRECTION OUTPUT ;
    USE SIGNAL ;
    PORT
      LAYER M5 ;
        RECT  115.92 30.156 115.944 30.24 ;
    END
  END xb[178]
  PIN xb[179]
    DIRECTION OUTPUT ;
    USE SIGNAL ;
    PORT
      LAYER M5 ;
        RECT  116.064 30.156 116.088 30.24 ;
    END
  END xb[179]
  PIN xb[17]
    DIRECTION OUTPUT ;
    USE SIGNAL ;
    PORT
      LAYER M5 ;
        RECT  92.736 30.156 92.76 30.24 ;
    END
  END xb[17]
  PIN xb[180]
    DIRECTION OUTPUT ;
    USE SIGNAL ;
    PORT
      LAYER M5 ;
        RECT  116.208 30.156 116.232 30.24 ;
    END
  END xb[180]
  PIN xb[181]
    DIRECTION OUTPUT ;
    USE SIGNAL ;
    PORT
      LAYER M5 ;
        RECT  116.352 30.156 116.376 30.24 ;
    END
  END xb[181]
  PIN xb[182]
    DIRECTION OUTPUT ;
    USE SIGNAL ;
    PORT
      LAYER M5 ;
        RECT  116.496 30.156 116.52 30.24 ;
    END
  END xb[182]
  PIN xb[183]
    DIRECTION OUTPUT ;
    USE SIGNAL ;
    PORT
      LAYER M5 ;
        RECT  116.64 30.156 116.664 30.24 ;
    END
  END xb[183]
  PIN xb[184]
    DIRECTION OUTPUT ;
    USE SIGNAL ;
    PORT
      LAYER M5 ;
        RECT  116.784 30.156 116.808 30.24 ;
    END
  END xb[184]
  PIN xb[185]
    DIRECTION OUTPUT ;
    USE SIGNAL ;
    PORT
      LAYER M5 ;
        RECT  116.928 30.156 116.952 30.24 ;
    END
  END xb[185]
  PIN xb[186]
    DIRECTION OUTPUT ;
    USE SIGNAL ;
    PORT
      LAYER M5 ;
        RECT  117.072 30.156 117.096 30.24 ;
    END
  END xb[186]
  PIN xb[187]
    DIRECTION OUTPUT ;
    USE SIGNAL ;
    PORT
      LAYER M5 ;
        RECT  117.216 30.156 117.24 30.24 ;
    END
  END xb[187]
  PIN xb[188]
    DIRECTION OUTPUT ;
    USE SIGNAL ;
    PORT
      LAYER M5 ;
        RECT  117.36 30.156 117.384 30.24 ;
    END
  END xb[188]
  PIN xb[189]
    DIRECTION OUTPUT ;
    USE SIGNAL ;
    PORT
      LAYER M5 ;
        RECT  117.504 30.156 117.528 30.24 ;
    END
  END xb[189]
  PIN xb[18]
    DIRECTION OUTPUT ;
    USE SIGNAL ;
    PORT
      LAYER M5 ;
        RECT  92.88 30.156 92.904 30.24 ;
    END
  END xb[18]
  PIN xb[190]
    DIRECTION OUTPUT ;
    USE SIGNAL ;
    PORT
      LAYER M5 ;
        RECT  117.648 30.156 117.672 30.24 ;
    END
  END xb[190]
  PIN xb[191]
    DIRECTION OUTPUT ;
    USE SIGNAL ;
    PORT
      LAYER M5 ;
        RECT  117.792 30.156 117.816 30.24 ;
    END
  END xb[191]
  PIN xb[192]
    DIRECTION OUTPUT ;
    USE SIGNAL ;
    PORT
      LAYER M5 ;
        RECT  117.936 30.156 117.96 30.24 ;
    END
  END xb[192]
  PIN xb[193]
    DIRECTION OUTPUT ;
    USE SIGNAL ;
    PORT
      LAYER M5 ;
        RECT  118.08 30.156 118.104 30.24 ;
    END
  END xb[193]
  PIN xb[194]
    DIRECTION OUTPUT ;
    USE SIGNAL ;
    PORT
      LAYER M5 ;
        RECT  118.224 30.156 118.248 30.24 ;
    END
  END xb[194]
  PIN xb[195]
    DIRECTION OUTPUT ;
    USE SIGNAL ;
    PORT
      LAYER M5 ;
        RECT  118.368 30.156 118.392 30.24 ;
    END
  END xb[195]
  PIN xb[196]
    DIRECTION OUTPUT ;
    USE SIGNAL ;
    PORT
      LAYER M5 ;
        RECT  118.512 30.156 118.536 30.24 ;
    END
  END xb[196]
  PIN xb[197]
    DIRECTION OUTPUT ;
    USE SIGNAL ;
    PORT
      LAYER M5 ;
        RECT  118.656 30.156 118.68 30.24 ;
    END
  END xb[197]
  PIN xb[198]
    DIRECTION OUTPUT ;
    USE SIGNAL ;
    PORT
      LAYER M5 ;
        RECT  118.8 30.156 118.824 30.24 ;
    END
  END xb[198]
  PIN xb[199]
    DIRECTION OUTPUT ;
    USE SIGNAL ;
    PORT
      LAYER M5 ;
        RECT  118.944 30.156 118.968 30.24 ;
    END
  END xb[199]
  PIN xb[19]
    DIRECTION OUTPUT ;
    USE SIGNAL ;
    PORT
      LAYER M5 ;
        RECT  93.024 30.156 93.048 30.24 ;
    END
  END xb[19]
  PIN xb[1]
    DIRECTION OUTPUT ;
    USE SIGNAL ;
    PORT
      LAYER M5 ;
        RECT  90.432 30.156 90.456 30.24 ;
    END
  END xb[1]
  PIN xb[200]
    DIRECTION OUTPUT ;
    USE SIGNAL ;
    PORT
      LAYER M5 ;
        RECT  119.088 30.156 119.112 30.24 ;
    END
  END xb[200]
  PIN xb[201]
    DIRECTION OUTPUT ;
    USE SIGNAL ;
    PORT
      LAYER M5 ;
        RECT  119.232 30.156 119.256 30.24 ;
    END
  END xb[201]
  PIN xb[202]
    DIRECTION OUTPUT ;
    USE SIGNAL ;
    PORT
      LAYER M5 ;
        RECT  119.376 30.156 119.4 30.24 ;
    END
  END xb[202]
  PIN xb[203]
    DIRECTION OUTPUT ;
    USE SIGNAL ;
    PORT
      LAYER M5 ;
        RECT  119.52 30.156 119.544 30.24 ;
    END
  END xb[203]
  PIN xb[204]
    DIRECTION OUTPUT ;
    USE SIGNAL ;
    PORT
      LAYER M5 ;
        RECT  119.664 30.156 119.688 30.24 ;
    END
  END xb[204]
  PIN xb[205]
    DIRECTION OUTPUT ;
    USE SIGNAL ;
    PORT
      LAYER M5 ;
        RECT  119.808 30.156 119.832 30.24 ;
    END
  END xb[205]
  PIN xb[206]
    DIRECTION OUTPUT ;
    USE SIGNAL ;
    PORT
      LAYER M5 ;
        RECT  119.952 30.156 119.976 30.24 ;
    END
  END xb[206]
  PIN xb[207]
    DIRECTION OUTPUT ;
    USE SIGNAL ;
    PORT
      LAYER M5 ;
        RECT  120.096 30.156 120.12 30.24 ;
    END
  END xb[207]
  PIN xb[208]
    DIRECTION OUTPUT ;
    USE SIGNAL ;
    PORT
      LAYER M5 ;
        RECT  120.24 30.156 120.264 30.24 ;
    END
  END xb[208]
  PIN xb[209]
    DIRECTION OUTPUT ;
    USE SIGNAL ;
    PORT
      LAYER M5 ;
        RECT  120.384 30.156 120.408 30.24 ;
    END
  END xb[209]
  PIN xb[20]
    DIRECTION OUTPUT ;
    USE SIGNAL ;
    PORT
      LAYER M5 ;
        RECT  93.168 30.156 93.192 30.24 ;
    END
  END xb[20]
  PIN xb[210]
    DIRECTION OUTPUT ;
    USE SIGNAL ;
    PORT
      LAYER M5 ;
        RECT  120.528 30.156 120.552 30.24 ;
    END
  END xb[210]
  PIN xb[211]
    DIRECTION OUTPUT ;
    USE SIGNAL ;
    PORT
      LAYER M5 ;
        RECT  120.672 30.156 120.696 30.24 ;
    END
  END xb[211]
  PIN xb[212]
    DIRECTION OUTPUT ;
    USE SIGNAL ;
    PORT
      LAYER M5 ;
        RECT  120.816 30.156 120.84 30.24 ;
    END
  END xb[212]
  PIN xb[213]
    DIRECTION OUTPUT ;
    USE SIGNAL ;
    PORT
      LAYER M5 ;
        RECT  120.96 30.156 120.984 30.24 ;
    END
  END xb[213]
  PIN xb[214]
    DIRECTION OUTPUT ;
    USE SIGNAL ;
    PORT
      LAYER M5 ;
        RECT  121.104 30.156 121.128 30.24 ;
    END
  END xb[214]
  PIN xb[215]
    DIRECTION OUTPUT ;
    USE SIGNAL ;
    PORT
      LAYER M5 ;
        RECT  121.248 30.156 121.272 30.24 ;
    END
  END xb[215]
  PIN xb[216]
    DIRECTION OUTPUT ;
    USE SIGNAL ;
    PORT
      LAYER M5 ;
        RECT  121.392 30.156 121.416 30.24 ;
    END
  END xb[216]
  PIN xb[217]
    DIRECTION OUTPUT ;
    USE SIGNAL ;
    PORT
      LAYER M5 ;
        RECT  121.536 30.156 121.56 30.24 ;
    END
  END xb[217]
  PIN xb[218]
    DIRECTION OUTPUT ;
    USE SIGNAL ;
    PORT
      LAYER M5 ;
        RECT  121.68 30.156 121.704 30.24 ;
    END
  END xb[218]
  PIN xb[219]
    DIRECTION OUTPUT ;
    USE SIGNAL ;
    PORT
      LAYER M5 ;
        RECT  121.824 30.156 121.848 30.24 ;
    END
  END xb[219]
  PIN xb[21]
    DIRECTION OUTPUT ;
    USE SIGNAL ;
    PORT
      LAYER M5 ;
        RECT  93.312 30.156 93.336 30.24 ;
    END
  END xb[21]
  PIN xb[220]
    DIRECTION OUTPUT ;
    USE SIGNAL ;
    PORT
      LAYER M5 ;
        RECT  121.968 30.156 121.992 30.24 ;
    END
  END xb[220]
  PIN xb[221]
    DIRECTION OUTPUT ;
    USE SIGNAL ;
    PORT
      LAYER M5 ;
        RECT  122.112 30.156 122.136 30.24 ;
    END
  END xb[221]
  PIN xb[222]
    DIRECTION OUTPUT ;
    USE SIGNAL ;
    PORT
      LAYER M5 ;
        RECT  122.256 30.156 122.28 30.24 ;
    END
  END xb[222]
  PIN xb[223]
    DIRECTION OUTPUT ;
    USE SIGNAL ;
    PORT
      LAYER M5 ;
        RECT  122.4 30.156 122.424 30.24 ;
    END
  END xb[223]
  PIN xb[224]
    DIRECTION OUTPUT ;
    USE SIGNAL ;
    PORT
      LAYER M5 ;
        RECT  122.544 30.156 122.568 30.24 ;
    END
  END xb[224]
  PIN xb[225]
    DIRECTION OUTPUT ;
    USE SIGNAL ;
    PORT
      LAYER M5 ;
        RECT  122.688 30.156 122.712 30.24 ;
    END
  END xb[225]
  PIN xb[226]
    DIRECTION OUTPUT ;
    USE SIGNAL ;
    PORT
      LAYER M5 ;
        RECT  122.832 30.156 122.856 30.24 ;
    END
  END xb[226]
  PIN xb[227]
    DIRECTION OUTPUT ;
    USE SIGNAL ;
    PORT
      LAYER M5 ;
        RECT  122.976 30.156 123 30.24 ;
    END
  END xb[227]
  PIN xb[228]
    DIRECTION OUTPUT ;
    USE SIGNAL ;
    PORT
      LAYER M5 ;
        RECT  123.12 30.156 123.144 30.24 ;
    END
  END xb[228]
  PIN xb[229]
    DIRECTION OUTPUT ;
    USE SIGNAL ;
    PORT
      LAYER M5 ;
        RECT  123.264 30.156 123.288 30.24 ;
    END
  END xb[229]
  PIN xb[22]
    DIRECTION OUTPUT ;
    USE SIGNAL ;
    PORT
      LAYER M5 ;
        RECT  93.456 30.156 93.48 30.24 ;
    END
  END xb[22]
  PIN xb[230]
    DIRECTION OUTPUT ;
    USE SIGNAL ;
    PORT
      LAYER M5 ;
        RECT  123.408 30.156 123.432 30.24 ;
    END
  END xb[230]
  PIN xb[231]
    DIRECTION OUTPUT ;
    USE SIGNAL ;
    PORT
      LAYER M5 ;
        RECT  123.552 30.156 123.576 30.24 ;
    END
  END xb[231]
  PIN xb[232]
    DIRECTION OUTPUT ;
    USE SIGNAL ;
    PORT
      LAYER M5 ;
        RECT  123.696 30.156 123.72 30.24 ;
    END
  END xb[232]
  PIN xb[233]
    DIRECTION OUTPUT ;
    USE SIGNAL ;
    PORT
      LAYER M5 ;
        RECT  123.84 30.156 123.864 30.24 ;
    END
  END xb[233]
  PIN xb[234]
    DIRECTION OUTPUT ;
    USE SIGNAL ;
    PORT
      LAYER M5 ;
        RECT  123.984 30.156 124.008 30.24 ;
    END
  END xb[234]
  PIN xb[235]
    DIRECTION OUTPUT ;
    USE SIGNAL ;
    PORT
      LAYER M5 ;
        RECT  124.128 30.156 124.152 30.24 ;
    END
  END xb[235]
  PIN xb[236]
    DIRECTION OUTPUT ;
    USE SIGNAL ;
    PORT
      LAYER M5 ;
        RECT  124.272 30.156 124.296 30.24 ;
    END
  END xb[236]
  PIN xb[237]
    DIRECTION OUTPUT ;
    USE SIGNAL ;
    PORT
      LAYER M5 ;
        RECT  124.416 30.156 124.44 30.24 ;
    END
  END xb[237]
  PIN xb[238]
    DIRECTION OUTPUT ;
    USE SIGNAL ;
    PORT
      LAYER M5 ;
        RECT  124.56 30.156 124.584 30.24 ;
    END
  END xb[238]
  PIN xb[239]
    DIRECTION OUTPUT ;
    USE SIGNAL ;
    PORT
      LAYER M5 ;
        RECT  124.704 30.156 124.728 30.24 ;
    END
  END xb[239]
  PIN xb[23]
    DIRECTION OUTPUT ;
    USE SIGNAL ;
    PORT
      LAYER M5 ;
        RECT  93.6 30.156 93.624 30.24 ;
    END
  END xb[23]
  PIN xb[240]
    DIRECTION OUTPUT ;
    USE SIGNAL ;
    PORT
      LAYER M5 ;
        RECT  124.848 30.156 124.872 30.24 ;
    END
  END xb[240]
  PIN xb[241]
    DIRECTION OUTPUT ;
    USE SIGNAL ;
    PORT
      LAYER M5 ;
        RECT  124.992 30.156 125.016 30.24 ;
    END
  END xb[241]
  PIN xb[242]
    DIRECTION OUTPUT ;
    USE SIGNAL ;
    PORT
      LAYER M5 ;
        RECT  125.136 30.156 125.16 30.24 ;
    END
  END xb[242]
  PIN xb[243]
    DIRECTION OUTPUT ;
    USE SIGNAL ;
    PORT
      LAYER M5 ;
        RECT  125.28 30.156 125.304 30.24 ;
    END
  END xb[243]
  PIN xb[244]
    DIRECTION OUTPUT ;
    USE SIGNAL ;
    PORT
      LAYER M5 ;
        RECT  125.424 30.156 125.448 30.24 ;
    END
  END xb[244]
  PIN xb[245]
    DIRECTION OUTPUT ;
    USE SIGNAL ;
    PORT
      LAYER M5 ;
        RECT  125.568 30.156 125.592 30.24 ;
    END
  END xb[245]
  PIN xb[246]
    DIRECTION OUTPUT ;
    USE SIGNAL ;
    PORT
      LAYER M5 ;
        RECT  125.712 30.156 125.736 30.24 ;
    END
  END xb[246]
  PIN xb[247]
    DIRECTION OUTPUT ;
    USE SIGNAL ;
    PORT
      LAYER M5 ;
        RECT  125.856 30.156 125.88 30.24 ;
    END
  END xb[247]
  PIN xb[248]
    DIRECTION OUTPUT ;
    USE SIGNAL ;
    PORT
      LAYER M5 ;
        RECT  126 30.156 126.024 30.24 ;
    END
  END xb[248]
  PIN xb[249]
    DIRECTION OUTPUT ;
    USE SIGNAL ;
    PORT
      LAYER M5 ;
        RECT  126.144 30.156 126.168 30.24 ;
    END
  END xb[249]
  PIN xb[24]
    DIRECTION OUTPUT ;
    USE SIGNAL ;
    PORT
      LAYER M5 ;
        RECT  93.744 30.156 93.768 30.24 ;
    END
  END xb[24]
  PIN xb[250]
    DIRECTION OUTPUT ;
    USE SIGNAL ;
    PORT
      LAYER M5 ;
        RECT  126.288 30.156 126.312 30.24 ;
    END
  END xb[250]
  PIN xb[251]
    DIRECTION OUTPUT ;
    USE SIGNAL ;
    PORT
      LAYER M5 ;
        RECT  126.432 30.156 126.456 30.24 ;
    END
  END xb[251]
  PIN xb[252]
    DIRECTION OUTPUT ;
    USE SIGNAL ;
    PORT
      LAYER M5 ;
        RECT  126.576 30.156 126.6 30.24 ;
    END
  END xb[252]
  PIN xb[253]
    DIRECTION OUTPUT ;
    USE SIGNAL ;
    PORT
      LAYER M5 ;
        RECT  126.72 30.156 126.744 30.24 ;
    END
  END xb[253]
  PIN xb[254]
    DIRECTION OUTPUT ;
    USE SIGNAL ;
    PORT
      LAYER M5 ;
        RECT  126.864 30.156 126.888 30.24 ;
    END
  END xb[254]
  PIN xb[255]
    DIRECTION OUTPUT ;
    USE SIGNAL ;
    PORT
      LAYER M5 ;
        RECT  127.008 30.156 127.032 30.24 ;
    END
  END xb[255]
  PIN xb[256]
    DIRECTION OUTPUT ;
    USE SIGNAL ;
    PORT
      LAYER M5 ;
        RECT  127.152 30.156 127.176 30.24 ;
    END
  END xb[256]
  PIN xb[257]
    DIRECTION OUTPUT ;
    USE SIGNAL ;
    PORT
      LAYER M5 ;
        RECT  127.296 30.156 127.32 30.24 ;
    END
  END xb[257]
  PIN xb[258]
    DIRECTION OUTPUT ;
    USE SIGNAL ;
    PORT
      LAYER M5 ;
        RECT  127.44 30.156 127.464 30.24 ;
    END
  END xb[258]
  PIN xb[259]
    DIRECTION OUTPUT ;
    USE SIGNAL ;
    PORT
      LAYER M5 ;
        RECT  127.584 30.156 127.608 30.24 ;
    END
  END xb[259]
  PIN xb[25]
    DIRECTION OUTPUT ;
    USE SIGNAL ;
    PORT
      LAYER M5 ;
        RECT  93.888 30.156 93.912 30.24 ;
    END
  END xb[25]
  PIN xb[260]
    DIRECTION OUTPUT ;
    USE SIGNAL ;
    PORT
      LAYER M5 ;
        RECT  127.728 30.156 127.752 30.24 ;
    END
  END xb[260]
  PIN xb[261]
    DIRECTION OUTPUT ;
    USE SIGNAL ;
    PORT
      LAYER M5 ;
        RECT  127.872 30.156 127.896 30.24 ;
    END
  END xb[261]
  PIN xb[262]
    DIRECTION OUTPUT ;
    USE SIGNAL ;
    PORT
      LAYER M5 ;
        RECT  128.016 30.156 128.04 30.24 ;
    END
  END xb[262]
  PIN xb[263]
    DIRECTION OUTPUT ;
    USE SIGNAL ;
    PORT
      LAYER M5 ;
        RECT  128.16 30.156 128.184 30.24 ;
    END
  END xb[263]
  PIN xb[264]
    DIRECTION OUTPUT ;
    USE SIGNAL ;
    PORT
      LAYER M5 ;
        RECT  128.304 30.156 128.328 30.24 ;
    END
  END xb[264]
  PIN xb[265]
    DIRECTION OUTPUT ;
    USE SIGNAL ;
    PORT
      LAYER M5 ;
        RECT  128.448 30.156 128.472 30.24 ;
    END
  END xb[265]
  PIN xb[26]
    DIRECTION OUTPUT ;
    USE SIGNAL ;
    PORT
      LAYER M5 ;
        RECT  94.032 30.156 94.056 30.24 ;
    END
  END xb[26]
  PIN xb[27]
    DIRECTION OUTPUT ;
    USE SIGNAL ;
    PORT
      LAYER M5 ;
        RECT  94.176 30.156 94.2 30.24 ;
    END
  END xb[27]
  PIN xb[28]
    DIRECTION OUTPUT ;
    USE SIGNAL ;
    PORT
      LAYER M5 ;
        RECT  94.32 30.156 94.344 30.24 ;
    END
  END xb[28]
  PIN xb[29]
    DIRECTION OUTPUT ;
    USE SIGNAL ;
    PORT
      LAYER M5 ;
        RECT  94.464 30.156 94.488 30.24 ;
    END
  END xb[29]
  PIN xb[2]
    DIRECTION OUTPUT ;
    USE SIGNAL ;
    PORT
      LAYER M5 ;
        RECT  90.576 30.156 90.6 30.24 ;
    END
  END xb[2]
  PIN xb[30]
    DIRECTION OUTPUT ;
    USE SIGNAL ;
    PORT
      LAYER M5 ;
        RECT  94.608 30.156 94.632 30.24 ;
    END
  END xb[30]
  PIN xb[31]
    DIRECTION OUTPUT ;
    USE SIGNAL ;
    PORT
      LAYER M5 ;
        RECT  94.752 30.156 94.776 30.24 ;
    END
  END xb[31]
  PIN xb[32]
    DIRECTION OUTPUT ;
    USE SIGNAL ;
    PORT
      LAYER M5 ;
        RECT  94.896 30.156 94.92 30.24 ;
    END
  END xb[32]
  PIN xb[33]
    DIRECTION OUTPUT ;
    USE SIGNAL ;
    PORT
      LAYER M5 ;
        RECT  95.04 30.156 95.064 30.24 ;
    END
  END xb[33]
  PIN xb[34]
    DIRECTION OUTPUT ;
    USE SIGNAL ;
    PORT
      LAYER M5 ;
        RECT  95.184 30.156 95.208 30.24 ;
    END
  END xb[34]
  PIN xb[35]
    DIRECTION OUTPUT ;
    USE SIGNAL ;
    PORT
      LAYER M5 ;
        RECT  95.328 30.156 95.352 30.24 ;
    END
  END xb[35]
  PIN xb[36]
    DIRECTION OUTPUT ;
    USE SIGNAL ;
    PORT
      LAYER M5 ;
        RECT  95.472 30.156 95.496 30.24 ;
    END
  END xb[36]
  PIN xb[37]
    DIRECTION OUTPUT ;
    USE SIGNAL ;
    PORT
      LAYER M5 ;
        RECT  95.616 30.156 95.64 30.24 ;
    END
  END xb[37]
  PIN xb[38]
    DIRECTION OUTPUT ;
    USE SIGNAL ;
    PORT
      LAYER M5 ;
        RECT  95.76 30.156 95.784 30.24 ;
    END
  END xb[38]
  PIN xb[39]
    DIRECTION OUTPUT ;
    USE SIGNAL ;
    PORT
      LAYER M5 ;
        RECT  95.904 30.156 95.928 30.24 ;
    END
  END xb[39]
  PIN xb[3]
    DIRECTION OUTPUT ;
    USE SIGNAL ;
    PORT
      LAYER M5 ;
        RECT  90.72 30.156 90.744 30.24 ;
    END
  END xb[3]
  PIN xb[40]
    DIRECTION OUTPUT ;
    USE SIGNAL ;
    PORT
      LAYER M5 ;
        RECT  96.048 30.156 96.072 30.24 ;
    END
  END xb[40]
  PIN xb[41]
    DIRECTION OUTPUT ;
    USE SIGNAL ;
    PORT
      LAYER M5 ;
        RECT  96.192 30.156 96.216 30.24 ;
    END
  END xb[41]
  PIN xb[42]
    DIRECTION OUTPUT ;
    USE SIGNAL ;
    PORT
      LAYER M5 ;
        RECT  96.336 30.156 96.36 30.24 ;
    END
  END xb[42]
  PIN xb[43]
    DIRECTION OUTPUT ;
    USE SIGNAL ;
    PORT
      LAYER M5 ;
        RECT  96.48 30.156 96.504 30.24 ;
    END
  END xb[43]
  PIN xb[44]
    DIRECTION OUTPUT ;
    USE SIGNAL ;
    PORT
      LAYER M5 ;
        RECT  96.624 30.156 96.648 30.24 ;
    END
  END xb[44]
  PIN xb[45]
    DIRECTION OUTPUT ;
    USE SIGNAL ;
    PORT
      LAYER M5 ;
        RECT  96.768 30.156 96.792 30.24 ;
    END
  END xb[45]
  PIN xb[46]
    DIRECTION OUTPUT ;
    USE SIGNAL ;
    PORT
      LAYER M5 ;
        RECT  96.912 30.156 96.936 30.24 ;
    END
  END xb[46]
  PIN xb[47]
    DIRECTION OUTPUT ;
    USE SIGNAL ;
    PORT
      LAYER M5 ;
        RECT  97.056 30.156 97.08 30.24 ;
    END
  END xb[47]
  PIN xb[48]
    DIRECTION OUTPUT ;
    USE SIGNAL ;
    PORT
      LAYER M5 ;
        RECT  97.2 30.156 97.224 30.24 ;
    END
  END xb[48]
  PIN xb[49]
    DIRECTION OUTPUT ;
    USE SIGNAL ;
    PORT
      LAYER M5 ;
        RECT  97.344 30.156 97.368 30.24 ;
    END
  END xb[49]
  PIN xb[4]
    DIRECTION OUTPUT ;
    USE SIGNAL ;
    PORT
      LAYER M5 ;
        RECT  90.864 30.156 90.888 30.24 ;
    END
  END xb[4]
  PIN xb[50]
    DIRECTION OUTPUT ;
    USE SIGNAL ;
    PORT
      LAYER M5 ;
        RECT  97.488 30.156 97.512 30.24 ;
    END
  END xb[50]
  PIN xb[51]
    DIRECTION OUTPUT ;
    USE SIGNAL ;
    PORT
      LAYER M5 ;
        RECT  97.632 30.156 97.656 30.24 ;
    END
  END xb[51]
  PIN xb[52]
    DIRECTION OUTPUT ;
    USE SIGNAL ;
    PORT
      LAYER M5 ;
        RECT  97.776 30.156 97.8 30.24 ;
    END
  END xb[52]
  PIN xb[53]
    DIRECTION OUTPUT ;
    USE SIGNAL ;
    PORT
      LAYER M5 ;
        RECT  97.92 30.156 97.944 30.24 ;
    END
  END xb[53]
  PIN xb[54]
    DIRECTION OUTPUT ;
    USE SIGNAL ;
    PORT
      LAYER M5 ;
        RECT  98.064 30.156 98.088 30.24 ;
    END
  END xb[54]
  PIN xb[55]
    DIRECTION OUTPUT ;
    USE SIGNAL ;
    PORT
      LAYER M5 ;
        RECT  98.208 30.156 98.232 30.24 ;
    END
  END xb[55]
  PIN xb[56]
    DIRECTION OUTPUT ;
    USE SIGNAL ;
    PORT
      LAYER M5 ;
        RECT  98.352 30.156 98.376 30.24 ;
    END
  END xb[56]
  PIN xb[57]
    DIRECTION OUTPUT ;
    USE SIGNAL ;
    PORT
      LAYER M5 ;
        RECT  98.496 30.156 98.52 30.24 ;
    END
  END xb[57]
  PIN xb[58]
    DIRECTION OUTPUT ;
    USE SIGNAL ;
    PORT
      LAYER M5 ;
        RECT  98.64 30.156 98.664 30.24 ;
    END
  END xb[58]
  PIN xb[59]
    DIRECTION OUTPUT ;
    USE SIGNAL ;
    PORT
      LAYER M5 ;
        RECT  98.784 30.156 98.808 30.24 ;
    END
  END xb[59]
  PIN xb[5]
    DIRECTION OUTPUT ;
    USE SIGNAL ;
    PORT
      LAYER M5 ;
        RECT  91.008 30.156 91.032 30.24 ;
    END
  END xb[5]
  PIN xb[60]
    DIRECTION OUTPUT ;
    USE SIGNAL ;
    PORT
      LAYER M5 ;
        RECT  98.928 30.156 98.952 30.24 ;
    END
  END xb[60]
  PIN xb[61]
    DIRECTION OUTPUT ;
    USE SIGNAL ;
    PORT
      LAYER M5 ;
        RECT  99.072 30.156 99.096 30.24 ;
    END
  END xb[61]
  PIN xb[62]
    DIRECTION OUTPUT ;
    USE SIGNAL ;
    PORT
      LAYER M5 ;
        RECT  99.216 30.156 99.24 30.24 ;
    END
  END xb[62]
  PIN xb[63]
    DIRECTION OUTPUT ;
    USE SIGNAL ;
    PORT
      LAYER M5 ;
        RECT  99.36 30.156 99.384 30.24 ;
    END
  END xb[63]
  PIN xb[64]
    DIRECTION OUTPUT ;
    USE SIGNAL ;
    PORT
      LAYER M5 ;
        RECT  99.504 30.156 99.528 30.24 ;
    END
  END xb[64]
  PIN xb[65]
    DIRECTION OUTPUT ;
    USE SIGNAL ;
    PORT
      LAYER M5 ;
        RECT  99.648 30.156 99.672 30.24 ;
    END
  END xb[65]
  PIN xb[66]
    DIRECTION OUTPUT ;
    USE SIGNAL ;
    PORT
      LAYER M5 ;
        RECT  99.792 30.156 99.816 30.24 ;
    END
  END xb[66]
  PIN xb[67]
    DIRECTION OUTPUT ;
    USE SIGNAL ;
    PORT
      LAYER M5 ;
        RECT  99.936 30.156 99.96 30.24 ;
    END
  END xb[67]
  PIN xb[68]
    DIRECTION OUTPUT ;
    USE SIGNAL ;
    PORT
      LAYER M5 ;
        RECT  100.08 30.156 100.104 30.24 ;
    END
  END xb[68]
  PIN xb[69]
    DIRECTION OUTPUT ;
    USE SIGNAL ;
    PORT
      LAYER M5 ;
        RECT  100.224 30.156 100.248 30.24 ;
    END
  END xb[69]
  PIN xb[6]
    DIRECTION OUTPUT ;
    USE SIGNAL ;
    PORT
      LAYER M5 ;
        RECT  91.152 30.156 91.176 30.24 ;
    END
  END xb[6]
  PIN xb[70]
    DIRECTION OUTPUT ;
    USE SIGNAL ;
    PORT
      LAYER M5 ;
        RECT  100.368 30.156 100.392 30.24 ;
    END
  END xb[70]
  PIN xb[71]
    DIRECTION OUTPUT ;
    USE SIGNAL ;
    PORT
      LAYER M5 ;
        RECT  100.512 30.156 100.536 30.24 ;
    END
  END xb[71]
  PIN xb[72]
    DIRECTION OUTPUT ;
    USE SIGNAL ;
    PORT
      LAYER M5 ;
        RECT  100.656 30.156 100.68 30.24 ;
    END
  END xb[72]
  PIN xb[73]
    DIRECTION OUTPUT ;
    USE SIGNAL ;
    PORT
      LAYER M5 ;
        RECT  100.8 30.156 100.824 30.24 ;
    END
  END xb[73]
  PIN xb[74]
    DIRECTION OUTPUT ;
    USE SIGNAL ;
    PORT
      LAYER M5 ;
        RECT  100.944 30.156 100.968 30.24 ;
    END
  END xb[74]
  PIN xb[75]
    DIRECTION OUTPUT ;
    USE SIGNAL ;
    PORT
      LAYER M5 ;
        RECT  101.088 30.156 101.112 30.24 ;
    END
  END xb[75]
  PIN xb[76]
    DIRECTION OUTPUT ;
    USE SIGNAL ;
    PORT
      LAYER M5 ;
        RECT  101.232 30.156 101.256 30.24 ;
    END
  END xb[76]
  PIN xb[77]
    DIRECTION OUTPUT ;
    USE SIGNAL ;
    PORT
      LAYER M5 ;
        RECT  101.376 30.156 101.4 30.24 ;
    END
  END xb[77]
  PIN xb[78]
    DIRECTION OUTPUT ;
    USE SIGNAL ;
    PORT
      LAYER M5 ;
        RECT  101.52 30.156 101.544 30.24 ;
    END
  END xb[78]
  PIN xb[79]
    DIRECTION OUTPUT ;
    USE SIGNAL ;
    PORT
      LAYER M5 ;
        RECT  101.664 30.156 101.688 30.24 ;
    END
  END xb[79]
  PIN xb[7]
    DIRECTION OUTPUT ;
    USE SIGNAL ;
    PORT
      LAYER M5 ;
        RECT  91.296 30.156 91.32 30.24 ;
    END
  END xb[7]
  PIN xb[80]
    DIRECTION OUTPUT ;
    USE SIGNAL ;
    PORT
      LAYER M5 ;
        RECT  101.808 30.156 101.832 30.24 ;
    END
  END xb[80]
  PIN xb[81]
    DIRECTION OUTPUT ;
    USE SIGNAL ;
    PORT
      LAYER M5 ;
        RECT  101.952 30.156 101.976 30.24 ;
    END
  END xb[81]
  PIN xb[82]
    DIRECTION OUTPUT ;
    USE SIGNAL ;
    PORT
      LAYER M5 ;
        RECT  102.096 30.156 102.12 30.24 ;
    END
  END xb[82]
  PIN xb[83]
    DIRECTION OUTPUT ;
    USE SIGNAL ;
    PORT
      LAYER M5 ;
        RECT  102.24 30.156 102.264 30.24 ;
    END
  END xb[83]
  PIN xb[84]
    DIRECTION OUTPUT ;
    USE SIGNAL ;
    PORT
      LAYER M5 ;
        RECT  102.384 30.156 102.408 30.24 ;
    END
  END xb[84]
  PIN xb[85]
    DIRECTION OUTPUT ;
    USE SIGNAL ;
    PORT
      LAYER M5 ;
        RECT  102.528 30.156 102.552 30.24 ;
    END
  END xb[85]
  PIN xb[86]
    DIRECTION OUTPUT ;
    USE SIGNAL ;
    PORT
      LAYER M5 ;
        RECT  102.672 30.156 102.696 30.24 ;
    END
  END xb[86]
  PIN xb[87]
    DIRECTION OUTPUT ;
    USE SIGNAL ;
    PORT
      LAYER M5 ;
        RECT  102.816 30.156 102.84 30.24 ;
    END
  END xb[87]
  PIN xb[88]
    DIRECTION OUTPUT ;
    USE SIGNAL ;
    PORT
      LAYER M5 ;
        RECT  102.96 30.156 102.984 30.24 ;
    END
  END xb[88]
  PIN xb[89]
    DIRECTION OUTPUT ;
    USE SIGNAL ;
    PORT
      LAYER M5 ;
        RECT  103.104 30.156 103.128 30.24 ;
    END
  END xb[89]
  PIN xb[8]
    DIRECTION OUTPUT ;
    USE SIGNAL ;
    PORT
      LAYER M5 ;
        RECT  91.44 30.156 91.464 30.24 ;
    END
  END xb[8]
  PIN xb[90]
    DIRECTION OUTPUT ;
    USE SIGNAL ;
    PORT
      LAYER M5 ;
        RECT  103.248 30.156 103.272 30.24 ;
    END
  END xb[90]
  PIN xb[91]
    DIRECTION OUTPUT ;
    USE SIGNAL ;
    PORT
      LAYER M5 ;
        RECT  103.392 30.156 103.416 30.24 ;
    END
  END xb[91]
  PIN xb[92]
    DIRECTION OUTPUT ;
    USE SIGNAL ;
    PORT
      LAYER M5 ;
        RECT  103.536 30.156 103.56 30.24 ;
    END
  END xb[92]
  PIN xb[93]
    DIRECTION OUTPUT ;
    USE SIGNAL ;
    PORT
      LAYER M5 ;
        RECT  103.68 30.156 103.704 30.24 ;
    END
  END xb[93]
  PIN xb[94]
    DIRECTION OUTPUT ;
    USE SIGNAL ;
    PORT
      LAYER M5 ;
        RECT  103.824 30.156 103.848 30.24 ;
    END
  END xb[94]
  PIN xb[95]
    DIRECTION OUTPUT ;
    USE SIGNAL ;
    PORT
      LAYER M5 ;
        RECT  103.968 30.156 103.992 30.24 ;
    END
  END xb[95]
  PIN xb[96]
    DIRECTION OUTPUT ;
    USE SIGNAL ;
    PORT
      LAYER M5 ;
        RECT  104.112 30.156 104.136 30.24 ;
    END
  END xb[96]
  PIN xb[97]
    DIRECTION OUTPUT ;
    USE SIGNAL ;
    PORT
      LAYER M5 ;
        RECT  104.256 30.156 104.28 30.24 ;
    END
  END xb[97]
  PIN xb[98]
    DIRECTION OUTPUT ;
    USE SIGNAL ;
    PORT
      LAYER M5 ;
        RECT  104.4 30.156 104.424 30.24 ;
    END
  END xb[98]
  PIN xb[99]
    DIRECTION OUTPUT ;
    USE SIGNAL ;
    PORT
      LAYER M5 ;
        RECT  104.544 30.156 104.568 30.24 ;
    END
  END xb[99]
  PIN xb[9]
    DIRECTION OUTPUT ;
    USE SIGNAL ;
    PORT
      LAYER M5 ;
        RECT  91.584 30.156 91.608 30.24 ;
    END
  END xb[9]
  PIN xbi[0]
    DIRECTION INPUT ;
    USE SIGNAL ;
    PORT
      LAYER M5 ;
        RECT  92.16 0 92.184 0.084 ;
    END
  END xbi[0]
  PIN xbi[100]
    DIRECTION INPUT ;
    USE SIGNAL ;
    PORT
      LAYER M5 ;
        RECT  106.56 0 106.584 0.084 ;
    END
  END xbi[100]
  PIN xbi[101]
    DIRECTION INPUT ;
    USE SIGNAL ;
    PORT
      LAYER M5 ;
        RECT  106.704 0 106.728 0.084 ;
    END
  END xbi[101]
  PIN xbi[102]
    DIRECTION INPUT ;
    USE SIGNAL ;
    PORT
      LAYER M5 ;
        RECT  106.848 0 106.872 0.084 ;
    END
  END xbi[102]
  PIN xbi[103]
    DIRECTION INPUT ;
    USE SIGNAL ;
    PORT
      LAYER M5 ;
        RECT  106.992 0 107.016 0.084 ;
    END
  END xbi[103]
  PIN xbi[104]
    DIRECTION INPUT ;
    USE SIGNAL ;
    PORT
      LAYER M5 ;
        RECT  107.136 0 107.16 0.084 ;
    END
  END xbi[104]
  PIN xbi[105]
    DIRECTION INPUT ;
    USE SIGNAL ;
    PORT
      LAYER M5 ;
        RECT  107.28 0 107.304 0.084 ;
    END
  END xbi[105]
  PIN xbi[106]
    DIRECTION INPUT ;
    USE SIGNAL ;
    PORT
      LAYER M5 ;
        RECT  107.424 0 107.448 0.084 ;
    END
  END xbi[106]
  PIN xbi[107]
    DIRECTION INPUT ;
    USE SIGNAL ;
    PORT
      LAYER M5 ;
        RECT  107.568 0 107.592 0.084 ;
    END
  END xbi[107]
  PIN xbi[108]
    DIRECTION INPUT ;
    USE SIGNAL ;
    PORT
      LAYER M5 ;
        RECT  107.712 0 107.736 0.084 ;
    END
  END xbi[108]
  PIN xbi[109]
    DIRECTION INPUT ;
    USE SIGNAL ;
    PORT
      LAYER M5 ;
        RECT  107.856 0 107.88 0.084 ;
    END
  END xbi[109]
  PIN xbi[10]
    DIRECTION INPUT ;
    USE SIGNAL ;
    PORT
      LAYER M5 ;
        RECT  93.6 0 93.624 0.084 ;
    END
  END xbi[10]
  PIN xbi[110]
    DIRECTION INPUT ;
    USE SIGNAL ;
    PORT
      LAYER M5 ;
        RECT  108 0 108.024 0.084 ;
    END
  END xbi[110]
  PIN xbi[111]
    DIRECTION INPUT ;
    USE SIGNAL ;
    PORT
      LAYER M5 ;
        RECT  108.144 0 108.168 0.084 ;
    END
  END xbi[111]
  PIN xbi[112]
    DIRECTION INPUT ;
    USE SIGNAL ;
    PORT
      LAYER M5 ;
        RECT  108.288 0 108.312 0.084 ;
    END
  END xbi[112]
  PIN xbi[113]
    DIRECTION INPUT ;
    USE SIGNAL ;
    PORT
      LAYER M5 ;
        RECT  108.432 0 108.456 0.084 ;
    END
  END xbi[113]
  PIN xbi[114]
    DIRECTION INPUT ;
    USE SIGNAL ;
    PORT
      LAYER M5 ;
        RECT  108.576 0 108.6 0.084 ;
    END
  END xbi[114]
  PIN xbi[115]
    DIRECTION INPUT ;
    USE SIGNAL ;
    PORT
      LAYER M5 ;
        RECT  108.72 0 108.744 0.084 ;
    END
  END xbi[115]
  PIN xbi[116]
    DIRECTION INPUT ;
    USE SIGNAL ;
    PORT
      LAYER M5 ;
        RECT  108.864 0 108.888 0.084 ;
    END
  END xbi[116]
  PIN xbi[117]
    DIRECTION INPUT ;
    USE SIGNAL ;
    PORT
      LAYER M5 ;
        RECT  109.008 0 109.032 0.084 ;
    END
  END xbi[117]
  PIN xbi[118]
    DIRECTION INPUT ;
    USE SIGNAL ;
    PORT
      LAYER M5 ;
        RECT  109.152 0 109.176 0.084 ;
    END
  END xbi[118]
  PIN xbi[119]
    DIRECTION INPUT ;
    USE SIGNAL ;
    PORT
      LAYER M5 ;
        RECT  109.296 0 109.32 0.084 ;
    END
  END xbi[119]
  PIN xbi[11]
    DIRECTION INPUT ;
    USE SIGNAL ;
    PORT
      LAYER M5 ;
        RECT  93.744 0 93.768 0.084 ;
    END
  END xbi[11]
  PIN xbi[120]
    DIRECTION INPUT ;
    USE SIGNAL ;
    PORT
      LAYER M5 ;
        RECT  109.44 0 109.464 0.084 ;
    END
  END xbi[120]
  PIN xbi[121]
    DIRECTION INPUT ;
    USE SIGNAL ;
    PORT
      LAYER M5 ;
        RECT  109.584 0 109.608 0.084 ;
    END
  END xbi[121]
  PIN xbi[122]
    DIRECTION INPUT ;
    USE SIGNAL ;
    PORT
      LAYER M5 ;
        RECT  109.728 0 109.752 0.084 ;
    END
  END xbi[122]
  PIN xbi[123]
    DIRECTION INPUT ;
    USE SIGNAL ;
    PORT
      LAYER M5 ;
        RECT  109.872 0 109.896 0.084 ;
    END
  END xbi[123]
  PIN xbi[124]
    DIRECTION INPUT ;
    USE SIGNAL ;
    PORT
      LAYER M5 ;
        RECT  110.016 0 110.04 0.084 ;
    END
  END xbi[124]
  PIN xbi[125]
    DIRECTION INPUT ;
    USE SIGNAL ;
    PORT
      LAYER M5 ;
        RECT  110.16 0 110.184 0.084 ;
    END
  END xbi[125]
  PIN xbi[126]
    DIRECTION INPUT ;
    USE SIGNAL ;
    PORT
      LAYER M5 ;
        RECT  110.304 0 110.328 0.084 ;
    END
  END xbi[126]
  PIN xbi[127]
    DIRECTION INPUT ;
    USE SIGNAL ;
    PORT
      LAYER M5 ;
        RECT  110.448 0 110.472 0.084 ;
    END
  END xbi[127]
  PIN xbi[128]
    DIRECTION INPUT ;
    USE SIGNAL ;
    PORT
      LAYER M5 ;
        RECT  110.592 0 110.616 0.084 ;
    END
  END xbi[128]
  PIN xbi[129]
    DIRECTION INPUT ;
    USE SIGNAL ;
    PORT
      LAYER M5 ;
        RECT  110.736 0 110.76 0.084 ;
    END
  END xbi[129]
  PIN xbi[12]
    DIRECTION INPUT ;
    USE SIGNAL ;
    PORT
      LAYER M5 ;
        RECT  93.888 0 93.912 0.084 ;
    END
  END xbi[12]
  PIN xbi[130]
    DIRECTION INPUT ;
    USE SIGNAL ;
    PORT
      LAYER M5 ;
        RECT  110.88 0 110.904 0.084 ;
    END
  END xbi[130]
  PIN xbi[131]
    DIRECTION INPUT ;
    USE SIGNAL ;
    PORT
      LAYER M5 ;
        RECT  111.024 0 111.048 0.084 ;
    END
  END xbi[131]
  PIN xbi[132]
    DIRECTION INPUT ;
    USE SIGNAL ;
    PORT
      LAYER M5 ;
        RECT  111.168 0 111.192 0.084 ;
    END
  END xbi[132]
  PIN xbi[133]
    DIRECTION INPUT ;
    USE SIGNAL ;
    PORT
      LAYER M5 ;
        RECT  111.312 0 111.336 0.084 ;
    END
  END xbi[133]
  PIN xbi[134]
    DIRECTION INPUT ;
    USE SIGNAL ;
    PORT
      LAYER M5 ;
        RECT  111.456 0 111.48 0.084 ;
    END
  END xbi[134]
  PIN xbi[135]
    DIRECTION INPUT ;
    USE SIGNAL ;
    PORT
      LAYER M5 ;
        RECT  111.6 0 111.624 0.084 ;
    END
  END xbi[135]
  PIN xbi[136]
    DIRECTION INPUT ;
    USE SIGNAL ;
    PORT
      LAYER M5 ;
        RECT  111.744 0 111.768 0.084 ;
    END
  END xbi[136]
  PIN xbi[137]
    DIRECTION INPUT ;
    USE SIGNAL ;
    PORT
      LAYER M5 ;
        RECT  111.888 0 111.912 0.084 ;
    END
  END xbi[137]
  PIN xbi[138]
    DIRECTION INPUT ;
    USE SIGNAL ;
    PORT
      LAYER M5 ;
        RECT  112.032 0 112.056 0.084 ;
    END
  END xbi[138]
  PIN xbi[139]
    DIRECTION INPUT ;
    USE SIGNAL ;
    PORT
      LAYER M5 ;
        RECT  112.176 0 112.2 0.084 ;
    END
  END xbi[139]
  PIN xbi[13]
    DIRECTION INPUT ;
    USE SIGNAL ;
    PORT
      LAYER M5 ;
        RECT  94.032 0 94.056 0.084 ;
    END
  END xbi[13]
  PIN xbi[140]
    DIRECTION INPUT ;
    USE SIGNAL ;
    PORT
      LAYER M5 ;
        RECT  112.32 0 112.344 0.084 ;
    END
  END xbi[140]
  PIN xbi[141]
    DIRECTION INPUT ;
    USE SIGNAL ;
    PORT
      LAYER M5 ;
        RECT  112.464 0 112.488 0.084 ;
    END
  END xbi[141]
  PIN xbi[142]
    DIRECTION INPUT ;
    USE SIGNAL ;
    PORT
      LAYER M5 ;
        RECT  112.608 0 112.632 0.084 ;
    END
  END xbi[142]
  PIN xbi[143]
    DIRECTION INPUT ;
    USE SIGNAL ;
    PORT
      LAYER M5 ;
        RECT  112.752 0 112.776 0.084 ;
    END
  END xbi[143]
  PIN xbi[144]
    DIRECTION INPUT ;
    USE SIGNAL ;
    PORT
      LAYER M5 ;
        RECT  112.896 0 112.92 0.084 ;
    END
  END xbi[144]
  PIN xbi[145]
    DIRECTION INPUT ;
    USE SIGNAL ;
    PORT
      LAYER M5 ;
        RECT  113.04 0 113.064 0.084 ;
    END
  END xbi[145]
  PIN xbi[146]
    DIRECTION INPUT ;
    USE SIGNAL ;
    PORT
      LAYER M5 ;
        RECT  113.184 0 113.208 0.084 ;
    END
  END xbi[146]
  PIN xbi[147]
    DIRECTION INPUT ;
    USE SIGNAL ;
    PORT
      LAYER M5 ;
        RECT  113.328 0 113.352 0.084 ;
    END
  END xbi[147]
  PIN xbi[148]
    DIRECTION INPUT ;
    USE SIGNAL ;
    PORT
      LAYER M5 ;
        RECT  113.472 0 113.496 0.084 ;
    END
  END xbi[148]
  PIN xbi[149]
    DIRECTION INPUT ;
    USE SIGNAL ;
    PORT
      LAYER M5 ;
        RECT  113.616 0 113.64 0.084 ;
    END
  END xbi[149]
  PIN xbi[14]
    DIRECTION INPUT ;
    USE SIGNAL ;
    PORT
      LAYER M5 ;
        RECT  94.176 0 94.2 0.084 ;
    END
  END xbi[14]
  PIN xbi[150]
    DIRECTION INPUT ;
    USE SIGNAL ;
    PORT
      LAYER M5 ;
        RECT  113.76 0 113.784 0.084 ;
    END
  END xbi[150]
  PIN xbi[151]
    DIRECTION INPUT ;
    USE SIGNAL ;
    PORT
      LAYER M5 ;
        RECT  113.904 0 113.928 0.084 ;
    END
  END xbi[151]
  PIN xbi[152]
    DIRECTION INPUT ;
    USE SIGNAL ;
    PORT
      LAYER M5 ;
        RECT  114.048 0 114.072 0.084 ;
    END
  END xbi[152]
  PIN xbi[153]
    DIRECTION INPUT ;
    USE SIGNAL ;
    PORT
      LAYER M5 ;
        RECT  114.192 0 114.216 0.084 ;
    END
  END xbi[153]
  PIN xbi[154]
    DIRECTION INPUT ;
    USE SIGNAL ;
    PORT
      LAYER M5 ;
        RECT  114.336 0 114.36 0.084 ;
    END
  END xbi[154]
  PIN xbi[155]
    DIRECTION INPUT ;
    USE SIGNAL ;
    PORT
      LAYER M5 ;
        RECT  114.48 0 114.504 0.084 ;
    END
  END xbi[155]
  PIN xbi[156]
    DIRECTION INPUT ;
    USE SIGNAL ;
    PORT
      LAYER M5 ;
        RECT  114.624 0 114.648 0.084 ;
    END
  END xbi[156]
  PIN xbi[157]
    DIRECTION INPUT ;
    USE SIGNAL ;
    PORT
      LAYER M5 ;
        RECT  114.768 0 114.792 0.084 ;
    END
  END xbi[157]
  PIN xbi[158]
    DIRECTION INPUT ;
    USE SIGNAL ;
    PORT
      LAYER M5 ;
        RECT  114.912 0 114.936 0.084 ;
    END
  END xbi[158]
  PIN xbi[159]
    DIRECTION INPUT ;
    USE SIGNAL ;
    PORT
      LAYER M5 ;
        RECT  115.056 0 115.08 0.084 ;
    END
  END xbi[159]
  PIN xbi[15]
    DIRECTION INPUT ;
    USE SIGNAL ;
    PORT
      LAYER M5 ;
        RECT  94.32 0 94.344 0.084 ;
    END
  END xbi[15]
  PIN xbi[160]
    DIRECTION INPUT ;
    USE SIGNAL ;
    PORT
      LAYER M5 ;
        RECT  115.2 0 115.224 0.084 ;
    END
  END xbi[160]
  PIN xbi[161]
    DIRECTION INPUT ;
    USE SIGNAL ;
    PORT
      LAYER M5 ;
        RECT  115.344 0 115.368 0.084 ;
    END
  END xbi[161]
  PIN xbi[162]
    DIRECTION INPUT ;
    USE SIGNAL ;
    PORT
      LAYER M5 ;
        RECT  115.488 0 115.512 0.084 ;
    END
  END xbi[162]
  PIN xbi[163]
    DIRECTION INPUT ;
    USE SIGNAL ;
    PORT
      LAYER M5 ;
        RECT  115.632 0 115.656 0.084 ;
    END
  END xbi[163]
  PIN xbi[164]
    DIRECTION INPUT ;
    USE SIGNAL ;
    PORT
      LAYER M5 ;
        RECT  115.776 0 115.8 0.084 ;
    END
  END xbi[164]
  PIN xbi[165]
    DIRECTION INPUT ;
    USE SIGNAL ;
    PORT
      LAYER M5 ;
        RECT  115.92 0 115.944 0.084 ;
    END
  END xbi[165]
  PIN xbi[166]
    DIRECTION INPUT ;
    USE SIGNAL ;
    PORT
      LAYER M5 ;
        RECT  116.064 0 116.088 0.084 ;
    END
  END xbi[166]
  PIN xbi[167]
    DIRECTION INPUT ;
    USE SIGNAL ;
    PORT
      LAYER M5 ;
        RECT  116.208 0 116.232 0.084 ;
    END
  END xbi[167]
  PIN xbi[168]
    DIRECTION INPUT ;
    USE SIGNAL ;
    PORT
      LAYER M5 ;
        RECT  116.352 0 116.376 0.084 ;
    END
  END xbi[168]
  PIN xbi[169]
    DIRECTION INPUT ;
    USE SIGNAL ;
    PORT
      LAYER M5 ;
        RECT  116.496 0 116.52 0.084 ;
    END
  END xbi[169]
  PIN xbi[16]
    DIRECTION INPUT ;
    USE SIGNAL ;
    PORT
      LAYER M5 ;
        RECT  94.464 0 94.488 0.084 ;
    END
  END xbi[16]
  PIN xbi[170]
    DIRECTION INPUT ;
    USE SIGNAL ;
    PORT
      LAYER M5 ;
        RECT  116.64 0 116.664 0.084 ;
    END
  END xbi[170]
  PIN xbi[171]
    DIRECTION INPUT ;
    USE SIGNAL ;
    PORT
      LAYER M5 ;
        RECT  116.784 0 116.808 0.084 ;
    END
  END xbi[171]
  PIN xbi[172]
    DIRECTION INPUT ;
    USE SIGNAL ;
    PORT
      LAYER M5 ;
        RECT  116.928 0 116.952 0.084 ;
    END
  END xbi[172]
  PIN xbi[173]
    DIRECTION INPUT ;
    USE SIGNAL ;
    PORT
      LAYER M5 ;
        RECT  117.072 0 117.096 0.084 ;
    END
  END xbi[173]
  PIN xbi[174]
    DIRECTION INPUT ;
    USE SIGNAL ;
    PORT
      LAYER M5 ;
        RECT  117.216 0 117.24 0.084 ;
    END
  END xbi[174]
  PIN xbi[175]
    DIRECTION INPUT ;
    USE SIGNAL ;
    PORT
      LAYER M5 ;
        RECT  117.36 0 117.384 0.084 ;
    END
  END xbi[175]
  PIN xbi[176]
    DIRECTION INPUT ;
    USE SIGNAL ;
    PORT
      LAYER M5 ;
        RECT  117.504 0 117.528 0.084 ;
    END
  END xbi[176]
  PIN xbi[177]
    DIRECTION INPUT ;
    USE SIGNAL ;
    PORT
      LAYER M5 ;
        RECT  117.648 0 117.672 0.084 ;
    END
  END xbi[177]
  PIN xbi[178]
    DIRECTION INPUT ;
    USE SIGNAL ;
    PORT
      LAYER M5 ;
        RECT  117.792 0 117.816 0.084 ;
    END
  END xbi[178]
  PIN xbi[179]
    DIRECTION INPUT ;
    USE SIGNAL ;
    PORT
      LAYER M5 ;
        RECT  117.936 0 117.96 0.084 ;
    END
  END xbi[179]
  PIN xbi[17]
    DIRECTION INPUT ;
    USE SIGNAL ;
    PORT
      LAYER M5 ;
        RECT  94.608 0 94.632 0.084 ;
    END
  END xbi[17]
  PIN xbi[180]
    DIRECTION INPUT ;
    USE SIGNAL ;
    PORT
      LAYER M5 ;
        RECT  118.08 0 118.104 0.084 ;
    END
  END xbi[180]
  PIN xbi[181]
    DIRECTION INPUT ;
    USE SIGNAL ;
    PORT
      LAYER M5 ;
        RECT  118.224 0 118.248 0.084 ;
    END
  END xbi[181]
  PIN xbi[182]
    DIRECTION INPUT ;
    USE SIGNAL ;
    PORT
      LAYER M5 ;
        RECT  118.368 0 118.392 0.084 ;
    END
  END xbi[182]
  PIN xbi[183]
    DIRECTION INPUT ;
    USE SIGNAL ;
    PORT
      LAYER M5 ;
        RECT  118.512 0 118.536 0.084 ;
    END
  END xbi[183]
  PIN xbi[184]
    DIRECTION INPUT ;
    USE SIGNAL ;
    PORT
      LAYER M5 ;
        RECT  118.656 0 118.68 0.084 ;
    END
  END xbi[184]
  PIN xbi[185]
    DIRECTION INPUT ;
    USE SIGNAL ;
    PORT
      LAYER M5 ;
        RECT  118.8 0 118.824 0.084 ;
    END
  END xbi[185]
  PIN xbi[186]
    DIRECTION INPUT ;
    USE SIGNAL ;
    PORT
      LAYER M5 ;
        RECT  118.944 0 118.968 0.084 ;
    END
  END xbi[186]
  PIN xbi[187]
    DIRECTION INPUT ;
    USE SIGNAL ;
    PORT
      LAYER M5 ;
        RECT  119.088 0 119.112 0.084 ;
    END
  END xbi[187]
  PIN xbi[188]
    DIRECTION INPUT ;
    USE SIGNAL ;
    PORT
      LAYER M5 ;
        RECT  119.232 0 119.256 0.084 ;
    END
  END xbi[188]
  PIN xbi[189]
    DIRECTION INPUT ;
    USE SIGNAL ;
    PORT
      LAYER M5 ;
        RECT  119.376 0 119.4 0.084 ;
    END
  END xbi[189]
  PIN xbi[18]
    DIRECTION INPUT ;
    USE SIGNAL ;
    PORT
      LAYER M5 ;
        RECT  94.752 0 94.776 0.084 ;
    END
  END xbi[18]
  PIN xbi[190]
    DIRECTION INPUT ;
    USE SIGNAL ;
    PORT
      LAYER M5 ;
        RECT  119.52 0 119.544 0.084 ;
    END
  END xbi[190]
  PIN xbi[191]
    DIRECTION INPUT ;
    USE SIGNAL ;
    PORT
      LAYER M5 ;
        RECT  119.664 0 119.688 0.084 ;
    END
  END xbi[191]
  PIN xbi[192]
    DIRECTION INPUT ;
    USE SIGNAL ;
    PORT
      LAYER M5 ;
        RECT  119.808 0 119.832 0.084 ;
    END
  END xbi[192]
  PIN xbi[193]
    DIRECTION INPUT ;
    USE SIGNAL ;
    PORT
      LAYER M5 ;
        RECT  119.952 0 119.976 0.084 ;
    END
  END xbi[193]
  PIN xbi[194]
    DIRECTION INPUT ;
    USE SIGNAL ;
    PORT
      LAYER M5 ;
        RECT  120.096 0 120.12 0.084 ;
    END
  END xbi[194]
  PIN xbi[195]
    DIRECTION INPUT ;
    USE SIGNAL ;
    PORT
      LAYER M5 ;
        RECT  120.24 0 120.264 0.084 ;
    END
  END xbi[195]
  PIN xbi[196]
    DIRECTION INPUT ;
    USE SIGNAL ;
    PORT
      LAYER M5 ;
        RECT  120.384 0 120.408 0.084 ;
    END
  END xbi[196]
  PIN xbi[197]
    DIRECTION INPUT ;
    USE SIGNAL ;
    PORT
      LAYER M5 ;
        RECT  120.528 0 120.552 0.084 ;
    END
  END xbi[197]
  PIN xbi[198]
    DIRECTION INPUT ;
    USE SIGNAL ;
    PORT
      LAYER M5 ;
        RECT  120.672 0 120.696 0.084 ;
    END
  END xbi[198]
  PIN xbi[199]
    DIRECTION INPUT ;
    USE SIGNAL ;
    PORT
      LAYER M5 ;
        RECT  120.816 0 120.84 0.084 ;
    END
  END xbi[199]
  PIN xbi[19]
    DIRECTION INPUT ;
    USE SIGNAL ;
    PORT
      LAYER M5 ;
        RECT  94.896 0 94.92 0.084 ;
    END
  END xbi[19]
  PIN xbi[1]
    DIRECTION INPUT ;
    USE SIGNAL ;
    PORT
      LAYER M5 ;
        RECT  92.304 0 92.328 0.084 ;
    END
  END xbi[1]
  PIN xbi[200]
    DIRECTION INPUT ;
    USE SIGNAL ;
    PORT
      LAYER M5 ;
        RECT  120.96 0 120.984 0.084 ;
    END
  END xbi[200]
  PIN xbi[201]
    DIRECTION INPUT ;
    USE SIGNAL ;
    PORT
      LAYER M5 ;
        RECT  121.104 0 121.128 0.084 ;
    END
  END xbi[201]
  PIN xbi[202]
    DIRECTION INPUT ;
    USE SIGNAL ;
    PORT
      LAYER M5 ;
        RECT  121.248 0 121.272 0.084 ;
    END
  END xbi[202]
  PIN xbi[203]
    DIRECTION INPUT ;
    USE SIGNAL ;
    PORT
      LAYER M5 ;
        RECT  121.392 0 121.416 0.084 ;
    END
  END xbi[203]
  PIN xbi[204]
    DIRECTION INPUT ;
    USE SIGNAL ;
    PORT
      LAYER M5 ;
        RECT  121.536 0 121.56 0.084 ;
    END
  END xbi[204]
  PIN xbi[205]
    DIRECTION INPUT ;
    USE SIGNAL ;
    PORT
      LAYER M5 ;
        RECT  121.68 0 121.704 0.084 ;
    END
  END xbi[205]
  PIN xbi[206]
    DIRECTION INPUT ;
    USE SIGNAL ;
    PORT
      LAYER M5 ;
        RECT  121.824 0 121.848 0.084 ;
    END
  END xbi[206]
  PIN xbi[207]
    DIRECTION INPUT ;
    USE SIGNAL ;
    PORT
      LAYER M5 ;
        RECT  121.968 0 121.992 0.084 ;
    END
  END xbi[207]
  PIN xbi[208]
    DIRECTION INPUT ;
    USE SIGNAL ;
    PORT
      LAYER M5 ;
        RECT  122.112 0 122.136 0.084 ;
    END
  END xbi[208]
  PIN xbi[209]
    DIRECTION INPUT ;
    USE SIGNAL ;
    PORT
      LAYER M5 ;
        RECT  122.256 0 122.28 0.084 ;
    END
  END xbi[209]
  PIN xbi[20]
    DIRECTION INPUT ;
    USE SIGNAL ;
    PORT
      LAYER M5 ;
        RECT  95.04 0 95.064 0.084 ;
    END
  END xbi[20]
  PIN xbi[210]
    DIRECTION INPUT ;
    USE SIGNAL ;
    PORT
      LAYER M5 ;
        RECT  122.4 0 122.424 0.084 ;
    END
  END xbi[210]
  PIN xbi[211]
    DIRECTION INPUT ;
    USE SIGNAL ;
    PORT
      LAYER M5 ;
        RECT  122.544 0 122.568 0.084 ;
    END
  END xbi[211]
  PIN xbi[212]
    DIRECTION INPUT ;
    USE SIGNAL ;
    PORT
      LAYER M5 ;
        RECT  122.688 0 122.712 0.084 ;
    END
  END xbi[212]
  PIN xbi[213]
    DIRECTION INPUT ;
    USE SIGNAL ;
    PORT
      LAYER M5 ;
        RECT  122.832 0 122.856 0.084 ;
    END
  END xbi[213]
  PIN xbi[214]
    DIRECTION INPUT ;
    USE SIGNAL ;
    PORT
      LAYER M5 ;
        RECT  122.976 0 123 0.084 ;
    END
  END xbi[214]
  PIN xbi[215]
    DIRECTION INPUT ;
    USE SIGNAL ;
    PORT
      LAYER M5 ;
        RECT  123.12 0 123.144 0.084 ;
    END
  END xbi[215]
  PIN xbi[216]
    DIRECTION INPUT ;
    USE SIGNAL ;
    PORT
      LAYER M5 ;
        RECT  123.264 0 123.288 0.084 ;
    END
  END xbi[216]
  PIN xbi[217]
    DIRECTION INPUT ;
    USE SIGNAL ;
    PORT
      LAYER M5 ;
        RECT  123.408 0 123.432 0.084 ;
    END
  END xbi[217]
  PIN xbi[218]
    DIRECTION INPUT ;
    USE SIGNAL ;
    PORT
      LAYER M5 ;
        RECT  123.552 0 123.576 0.084 ;
    END
  END xbi[218]
  PIN xbi[219]
    DIRECTION INPUT ;
    USE SIGNAL ;
    PORT
      LAYER M5 ;
        RECT  123.696 0 123.72 0.084 ;
    END
  END xbi[219]
  PIN xbi[21]
    DIRECTION INPUT ;
    USE SIGNAL ;
    PORT
      LAYER M5 ;
        RECT  95.184 0 95.208 0.084 ;
    END
  END xbi[21]
  PIN xbi[220]
    DIRECTION INPUT ;
    USE SIGNAL ;
    PORT
      LAYER M5 ;
        RECT  123.84 0 123.864 0.084 ;
    END
  END xbi[220]
  PIN xbi[221]
    DIRECTION INPUT ;
    USE SIGNAL ;
    PORT
      LAYER M5 ;
        RECT  123.984 0 124.008 0.084 ;
    END
  END xbi[221]
  PIN xbi[222]
    DIRECTION INPUT ;
    USE SIGNAL ;
    PORT
      LAYER M5 ;
        RECT  124.128 0 124.152 0.084 ;
    END
  END xbi[222]
  PIN xbi[223]
    DIRECTION INPUT ;
    USE SIGNAL ;
    PORT
      LAYER M5 ;
        RECT  124.272 0 124.296 0.084 ;
    END
  END xbi[223]
  PIN xbi[224]
    DIRECTION INPUT ;
    USE SIGNAL ;
    PORT
      LAYER M5 ;
        RECT  124.416 0 124.44 0.084 ;
    END
  END xbi[224]
  PIN xbi[225]
    DIRECTION INPUT ;
    USE SIGNAL ;
    PORT
      LAYER M5 ;
        RECT  124.56 0 124.584 0.084 ;
    END
  END xbi[225]
  PIN xbi[226]
    DIRECTION INPUT ;
    USE SIGNAL ;
    PORT
      LAYER M5 ;
        RECT  124.704 0 124.728 0.084 ;
    END
  END xbi[226]
  PIN xbi[227]
    DIRECTION INPUT ;
    USE SIGNAL ;
    PORT
      LAYER M5 ;
        RECT  124.848 0 124.872 0.084 ;
    END
  END xbi[227]
  PIN xbi[228]
    DIRECTION INPUT ;
    USE SIGNAL ;
    PORT
      LAYER M5 ;
        RECT  124.992 0 125.016 0.084 ;
    END
  END xbi[228]
  PIN xbi[229]
    DIRECTION INPUT ;
    USE SIGNAL ;
    PORT
      LAYER M5 ;
        RECT  125.136 0 125.16 0.084 ;
    END
  END xbi[229]
  PIN xbi[22]
    DIRECTION INPUT ;
    USE SIGNAL ;
    PORT
      LAYER M5 ;
        RECT  95.328 0 95.352 0.084 ;
    END
  END xbi[22]
  PIN xbi[230]
    DIRECTION INPUT ;
    USE SIGNAL ;
    PORT
      LAYER M5 ;
        RECT  125.28 0 125.304 0.084 ;
    END
  END xbi[230]
  PIN xbi[231]
    DIRECTION INPUT ;
    USE SIGNAL ;
    PORT
      LAYER M5 ;
        RECT  125.424 0 125.448 0.084 ;
    END
  END xbi[231]
  PIN xbi[232]
    DIRECTION INPUT ;
    USE SIGNAL ;
    PORT
      LAYER M5 ;
        RECT  125.568 0 125.592 0.084 ;
    END
  END xbi[232]
  PIN xbi[233]
    DIRECTION INPUT ;
    USE SIGNAL ;
    PORT
      LAYER M5 ;
        RECT  125.712 0 125.736 0.084 ;
    END
  END xbi[233]
  PIN xbi[234]
    DIRECTION INPUT ;
    USE SIGNAL ;
    PORT
      LAYER M5 ;
        RECT  125.856 0 125.88 0.084 ;
    END
  END xbi[234]
  PIN xbi[235]
    DIRECTION INPUT ;
    USE SIGNAL ;
    PORT
      LAYER M5 ;
        RECT  126 0 126.024 0.084 ;
    END
  END xbi[235]
  PIN xbi[236]
    DIRECTION INPUT ;
    USE SIGNAL ;
    PORT
      LAYER M5 ;
        RECT  126.144 0 126.168 0.084 ;
    END
  END xbi[236]
  PIN xbi[237]
    DIRECTION INPUT ;
    USE SIGNAL ;
    PORT
      LAYER M5 ;
        RECT  126.288 0 126.312 0.084 ;
    END
  END xbi[237]
  PIN xbi[238]
    DIRECTION INPUT ;
    USE SIGNAL ;
    PORT
      LAYER M5 ;
        RECT  126.432 0 126.456 0.084 ;
    END
  END xbi[238]
  PIN xbi[239]
    DIRECTION INPUT ;
    USE SIGNAL ;
    PORT
      LAYER M5 ;
        RECT  126.576 0 126.6 0.084 ;
    END
  END xbi[239]
  PIN xbi[23]
    DIRECTION INPUT ;
    USE SIGNAL ;
    PORT
      LAYER M5 ;
        RECT  95.472 0 95.496 0.084 ;
    END
  END xbi[23]
  PIN xbi[240]
    DIRECTION INPUT ;
    USE SIGNAL ;
    PORT
      LAYER M5 ;
        RECT  126.72 0 126.744 0.084 ;
    END
  END xbi[240]
  PIN xbi[241]
    DIRECTION INPUT ;
    USE SIGNAL ;
    PORT
      LAYER M5 ;
        RECT  126.864 0 126.888 0.084 ;
    END
  END xbi[241]
  PIN xbi[242]
    DIRECTION INPUT ;
    USE SIGNAL ;
    PORT
      LAYER M5 ;
        RECT  127.008 0 127.032 0.084 ;
    END
  END xbi[242]
  PIN xbi[243]
    DIRECTION INPUT ;
    USE SIGNAL ;
    PORT
      LAYER M5 ;
        RECT  127.152 0 127.176 0.084 ;
    END
  END xbi[243]
  PIN xbi[244]
    DIRECTION INPUT ;
    USE SIGNAL ;
    PORT
      LAYER M5 ;
        RECT  127.296 0 127.32 0.084 ;
    END
  END xbi[244]
  PIN xbi[245]
    DIRECTION INPUT ;
    USE SIGNAL ;
    PORT
      LAYER M5 ;
        RECT  127.44 0 127.464 0.084 ;
    END
  END xbi[245]
  PIN xbi[246]
    DIRECTION INPUT ;
    USE SIGNAL ;
    PORT
      LAYER M5 ;
        RECT  127.584 0 127.608 0.084 ;
    END
  END xbi[246]
  PIN xbi[247]
    DIRECTION INPUT ;
    USE SIGNAL ;
    PORT
      LAYER M5 ;
        RECT  127.728 0 127.752 0.084 ;
    END
  END xbi[247]
  PIN xbi[248]
    DIRECTION INPUT ;
    USE SIGNAL ;
    PORT
      LAYER M5 ;
        RECT  127.872 0 127.896 0.084 ;
    END
  END xbi[248]
  PIN xbi[249]
    DIRECTION INPUT ;
    USE SIGNAL ;
    PORT
      LAYER M5 ;
        RECT  128.016 0 128.04 0.084 ;
    END
  END xbi[249]
  PIN xbi[24]
    DIRECTION INPUT ;
    USE SIGNAL ;
    PORT
      LAYER M5 ;
        RECT  95.616 0 95.64 0.084 ;
    END
  END xbi[24]
  PIN xbi[250]
    DIRECTION INPUT ;
    USE SIGNAL ;
    PORT
      LAYER M5 ;
        RECT  128.16 0 128.184 0.084 ;
    END
  END xbi[250]
  PIN xbi[251]
    DIRECTION INPUT ;
    USE SIGNAL ;
    PORT
      LAYER M5 ;
        RECT  128.304 0 128.328 0.084 ;
    END
  END xbi[251]
  PIN xbi[252]
    DIRECTION INPUT ;
    USE SIGNAL ;
    PORT
      LAYER M5 ;
        RECT  128.448 0 128.472 0.084 ;
    END
  END xbi[252]
  PIN xbi[253]
    DIRECTION INPUT ;
    USE SIGNAL ;
    PORT
      LAYER M5 ;
        RECT  128.592 0 128.616 0.084 ;
    END
  END xbi[253]
  PIN xbi[254]
    DIRECTION INPUT ;
    USE SIGNAL ;
    PORT
      LAYER M5 ;
        RECT  128.736 0 128.76 0.084 ;
    END
  END xbi[254]
  PIN xbi[255]
    DIRECTION INPUT ;
    USE SIGNAL ;
    PORT
      LAYER M5 ;
        RECT  128.88 0 128.904 0.084 ;
    END
  END xbi[255]
  PIN xbi[256]
    DIRECTION INPUT ;
    USE SIGNAL ;
    PORT
      LAYER M5 ;
        RECT  129.024 0 129.048 0.084 ;
    END
  END xbi[256]
  PIN xbi[257]
    DIRECTION INPUT ;
    USE SIGNAL ;
    PORT
      LAYER M5 ;
        RECT  129.168 0 129.192 0.084 ;
    END
  END xbi[257]
  PIN xbi[258]
    DIRECTION INPUT ;
    USE SIGNAL ;
    PORT
      LAYER M5 ;
        RECT  129.312 0 129.336 0.084 ;
    END
  END xbi[258]
  PIN xbi[259]
    DIRECTION INPUT ;
    USE SIGNAL ;
    PORT
      LAYER M5 ;
        RECT  129.456 0 129.48 0.084 ;
    END
  END xbi[259]
  PIN xbi[25]
    DIRECTION INPUT ;
    USE SIGNAL ;
    PORT
      LAYER M5 ;
        RECT  95.76 0 95.784 0.084 ;
    END
  END xbi[25]
  PIN xbi[260]
    DIRECTION INPUT ;
    USE SIGNAL ;
    PORT
      LAYER M5 ;
        RECT  129.6 0 129.624 0.084 ;
    END
  END xbi[260]
  PIN xbi[261]
    DIRECTION INPUT ;
    USE SIGNAL ;
    PORT
      LAYER M5 ;
        RECT  129.744 0 129.768 0.084 ;
    END
  END xbi[261]
  PIN xbi[262]
    DIRECTION INPUT ;
    USE SIGNAL ;
    PORT
      LAYER M5 ;
        RECT  129.888 0 129.912 0.084 ;
    END
  END xbi[262]
  PIN xbi[263]
    DIRECTION INPUT ;
    USE SIGNAL ;
    PORT
      LAYER M5 ;
        RECT  130.032 0 130.056 0.084 ;
    END
  END xbi[263]
  PIN xbi[264]
    DIRECTION INPUT ;
    USE SIGNAL ;
    PORT
      LAYER M5 ;
        RECT  130.176 0 130.2 0.084 ;
    END
  END xbi[264]
  PIN xbi[265]
    DIRECTION INPUT ;
    USE SIGNAL ;
    PORT
      LAYER M5 ;
        RECT  130.32 0 130.344 0.084 ;
    END
  END xbi[265]
  PIN xbi[26]
    DIRECTION INPUT ;
    USE SIGNAL ;
    PORT
      LAYER M5 ;
        RECT  95.904 0 95.928 0.084 ;
    END
  END xbi[26]
  PIN xbi[27]
    DIRECTION INPUT ;
    USE SIGNAL ;
    PORT
      LAYER M5 ;
        RECT  96.048 0 96.072 0.084 ;
    END
  END xbi[27]
  PIN xbi[28]
    DIRECTION INPUT ;
    USE SIGNAL ;
    PORT
      LAYER M5 ;
        RECT  96.192 0 96.216 0.084 ;
    END
  END xbi[28]
  PIN xbi[29]
    DIRECTION INPUT ;
    USE SIGNAL ;
    PORT
      LAYER M5 ;
        RECT  96.336 0 96.36 0.084 ;
    END
  END xbi[29]
  PIN xbi[2]
    DIRECTION INPUT ;
    USE SIGNAL ;
    PORT
      LAYER M5 ;
        RECT  92.448 0 92.472 0.084 ;
    END
  END xbi[2]
  PIN xbi[30]
    DIRECTION INPUT ;
    USE SIGNAL ;
    PORT
      LAYER M5 ;
        RECT  96.48 0 96.504 0.084 ;
    END
  END xbi[30]
  PIN xbi[31]
    DIRECTION INPUT ;
    USE SIGNAL ;
    PORT
      LAYER M5 ;
        RECT  96.624 0 96.648 0.084 ;
    END
  END xbi[31]
  PIN xbi[32]
    DIRECTION INPUT ;
    USE SIGNAL ;
    PORT
      LAYER M5 ;
        RECT  96.768 0 96.792 0.084 ;
    END
  END xbi[32]
  PIN xbi[33]
    DIRECTION INPUT ;
    USE SIGNAL ;
    PORT
      LAYER M5 ;
        RECT  96.912 0 96.936 0.084 ;
    END
  END xbi[33]
  PIN xbi[34]
    DIRECTION INPUT ;
    USE SIGNAL ;
    PORT
      LAYER M5 ;
        RECT  97.056 0 97.08 0.084 ;
    END
  END xbi[34]
  PIN xbi[35]
    DIRECTION INPUT ;
    USE SIGNAL ;
    PORT
      LAYER M5 ;
        RECT  97.2 0 97.224 0.084 ;
    END
  END xbi[35]
  PIN xbi[36]
    DIRECTION INPUT ;
    USE SIGNAL ;
    PORT
      LAYER M5 ;
        RECT  97.344 0 97.368 0.084 ;
    END
  END xbi[36]
  PIN xbi[37]
    DIRECTION INPUT ;
    USE SIGNAL ;
    PORT
      LAYER M5 ;
        RECT  97.488 0 97.512 0.084 ;
    END
  END xbi[37]
  PIN xbi[38]
    DIRECTION INPUT ;
    USE SIGNAL ;
    PORT
      LAYER M5 ;
        RECT  97.632 0 97.656 0.084 ;
    END
  END xbi[38]
  PIN xbi[39]
    DIRECTION INPUT ;
    USE SIGNAL ;
    PORT
      LAYER M5 ;
        RECT  97.776 0 97.8 0.084 ;
    END
  END xbi[39]
  PIN xbi[3]
    DIRECTION INPUT ;
    USE SIGNAL ;
    PORT
      LAYER M5 ;
        RECT  92.592 0 92.616 0.084 ;
    END
  END xbi[3]
  PIN xbi[40]
    DIRECTION INPUT ;
    USE SIGNAL ;
    PORT
      LAYER M5 ;
        RECT  97.92 0 97.944 0.084 ;
    END
  END xbi[40]
  PIN xbi[41]
    DIRECTION INPUT ;
    USE SIGNAL ;
    PORT
      LAYER M5 ;
        RECT  98.064 0 98.088 0.084 ;
    END
  END xbi[41]
  PIN xbi[42]
    DIRECTION INPUT ;
    USE SIGNAL ;
    PORT
      LAYER M5 ;
        RECT  98.208 0 98.232 0.084 ;
    END
  END xbi[42]
  PIN xbi[43]
    DIRECTION INPUT ;
    USE SIGNAL ;
    PORT
      LAYER M5 ;
        RECT  98.352 0 98.376 0.084 ;
    END
  END xbi[43]
  PIN xbi[44]
    DIRECTION INPUT ;
    USE SIGNAL ;
    PORT
      LAYER M5 ;
        RECT  98.496 0 98.52 0.084 ;
    END
  END xbi[44]
  PIN xbi[45]
    DIRECTION INPUT ;
    USE SIGNAL ;
    PORT
      LAYER M5 ;
        RECT  98.64 0 98.664 0.084 ;
    END
  END xbi[45]
  PIN xbi[46]
    DIRECTION INPUT ;
    USE SIGNAL ;
    PORT
      LAYER M5 ;
        RECT  98.784 0 98.808 0.084 ;
    END
  END xbi[46]
  PIN xbi[47]
    DIRECTION INPUT ;
    USE SIGNAL ;
    PORT
      LAYER M5 ;
        RECT  98.928 0 98.952 0.084 ;
    END
  END xbi[47]
  PIN xbi[48]
    DIRECTION INPUT ;
    USE SIGNAL ;
    PORT
      LAYER M5 ;
        RECT  99.072 0 99.096 0.084 ;
    END
  END xbi[48]
  PIN xbi[49]
    DIRECTION INPUT ;
    USE SIGNAL ;
    PORT
      LAYER M5 ;
        RECT  99.216 0 99.24 0.084 ;
    END
  END xbi[49]
  PIN xbi[4]
    DIRECTION INPUT ;
    USE SIGNAL ;
    PORT
      LAYER M5 ;
        RECT  92.736 0 92.76 0.084 ;
    END
  END xbi[4]
  PIN xbi[50]
    DIRECTION INPUT ;
    USE SIGNAL ;
    PORT
      LAYER M5 ;
        RECT  99.36 0 99.384 0.084 ;
    END
  END xbi[50]
  PIN xbi[51]
    DIRECTION INPUT ;
    USE SIGNAL ;
    PORT
      LAYER M5 ;
        RECT  99.504 0 99.528 0.084 ;
    END
  END xbi[51]
  PIN xbi[52]
    DIRECTION INPUT ;
    USE SIGNAL ;
    PORT
      LAYER M5 ;
        RECT  99.648 0 99.672 0.084 ;
    END
  END xbi[52]
  PIN xbi[53]
    DIRECTION INPUT ;
    USE SIGNAL ;
    PORT
      LAYER M5 ;
        RECT  99.792 0 99.816 0.084 ;
    END
  END xbi[53]
  PIN xbi[54]
    DIRECTION INPUT ;
    USE SIGNAL ;
    PORT
      LAYER M5 ;
        RECT  99.936 0 99.96 0.084 ;
    END
  END xbi[54]
  PIN xbi[55]
    DIRECTION INPUT ;
    USE SIGNAL ;
    PORT
      LAYER M5 ;
        RECT  100.08 0 100.104 0.084 ;
    END
  END xbi[55]
  PIN xbi[56]
    DIRECTION INPUT ;
    USE SIGNAL ;
    PORT
      LAYER M5 ;
        RECT  100.224 0 100.248 0.084 ;
    END
  END xbi[56]
  PIN xbi[57]
    DIRECTION INPUT ;
    USE SIGNAL ;
    PORT
      LAYER M5 ;
        RECT  100.368 0 100.392 0.084 ;
    END
  END xbi[57]
  PIN xbi[58]
    DIRECTION INPUT ;
    USE SIGNAL ;
    PORT
      LAYER M5 ;
        RECT  100.512 0 100.536 0.084 ;
    END
  END xbi[58]
  PIN xbi[59]
    DIRECTION INPUT ;
    USE SIGNAL ;
    PORT
      LAYER M5 ;
        RECT  100.656 0 100.68 0.084 ;
    END
  END xbi[59]
  PIN xbi[5]
    DIRECTION INPUT ;
    USE SIGNAL ;
    PORT
      LAYER M5 ;
        RECT  92.88 0 92.904 0.084 ;
    END
  END xbi[5]
  PIN xbi[60]
    DIRECTION INPUT ;
    USE SIGNAL ;
    PORT
      LAYER M5 ;
        RECT  100.8 0 100.824 0.084 ;
    END
  END xbi[60]
  PIN xbi[61]
    DIRECTION INPUT ;
    USE SIGNAL ;
    PORT
      LAYER M5 ;
        RECT  100.944 0 100.968 0.084 ;
    END
  END xbi[61]
  PIN xbi[62]
    DIRECTION INPUT ;
    USE SIGNAL ;
    PORT
      LAYER M5 ;
        RECT  101.088 0 101.112 0.084 ;
    END
  END xbi[62]
  PIN xbi[63]
    DIRECTION INPUT ;
    USE SIGNAL ;
    PORT
      LAYER M5 ;
        RECT  101.232 0 101.256 0.084 ;
    END
  END xbi[63]
  PIN xbi[64]
    DIRECTION INPUT ;
    USE SIGNAL ;
    PORT
      LAYER M5 ;
        RECT  101.376 0 101.4 0.084 ;
    END
  END xbi[64]
  PIN xbi[65]
    DIRECTION INPUT ;
    USE SIGNAL ;
    PORT
      LAYER M5 ;
        RECT  101.52 0 101.544 0.084 ;
    END
  END xbi[65]
  PIN xbi[66]
    DIRECTION INPUT ;
    USE SIGNAL ;
    PORT
      LAYER M5 ;
        RECT  101.664 0 101.688 0.084 ;
    END
  END xbi[66]
  PIN xbi[67]
    DIRECTION INPUT ;
    USE SIGNAL ;
    PORT
      LAYER M5 ;
        RECT  101.808 0 101.832 0.084 ;
    END
  END xbi[67]
  PIN xbi[68]
    DIRECTION INPUT ;
    USE SIGNAL ;
    PORT
      LAYER M5 ;
        RECT  101.952 0 101.976 0.084 ;
    END
  END xbi[68]
  PIN xbi[69]
    DIRECTION INPUT ;
    USE SIGNAL ;
    PORT
      LAYER M5 ;
        RECT  102.096 0 102.12 0.084 ;
    END
  END xbi[69]
  PIN xbi[6]
    DIRECTION INPUT ;
    USE SIGNAL ;
    PORT
      LAYER M5 ;
        RECT  93.024 0 93.048 0.084 ;
    END
  END xbi[6]
  PIN xbi[70]
    DIRECTION INPUT ;
    USE SIGNAL ;
    PORT
      LAYER M5 ;
        RECT  102.24 0 102.264 0.084 ;
    END
  END xbi[70]
  PIN xbi[71]
    DIRECTION INPUT ;
    USE SIGNAL ;
    PORT
      LAYER M5 ;
        RECT  102.384 0 102.408 0.084 ;
    END
  END xbi[71]
  PIN xbi[72]
    DIRECTION INPUT ;
    USE SIGNAL ;
    PORT
      LAYER M5 ;
        RECT  102.528 0 102.552 0.084 ;
    END
  END xbi[72]
  PIN xbi[73]
    DIRECTION INPUT ;
    USE SIGNAL ;
    PORT
      LAYER M5 ;
        RECT  102.672 0 102.696 0.084 ;
    END
  END xbi[73]
  PIN xbi[74]
    DIRECTION INPUT ;
    USE SIGNAL ;
    PORT
      LAYER M5 ;
        RECT  102.816 0 102.84 0.084 ;
    END
  END xbi[74]
  PIN xbi[75]
    DIRECTION INPUT ;
    USE SIGNAL ;
    PORT
      LAYER M5 ;
        RECT  102.96 0 102.984 0.084 ;
    END
  END xbi[75]
  PIN xbi[76]
    DIRECTION INPUT ;
    USE SIGNAL ;
    PORT
      LAYER M5 ;
        RECT  103.104 0 103.128 0.084 ;
    END
  END xbi[76]
  PIN xbi[77]
    DIRECTION INPUT ;
    USE SIGNAL ;
    PORT
      LAYER M5 ;
        RECT  103.248 0 103.272 0.084 ;
    END
  END xbi[77]
  PIN xbi[78]
    DIRECTION INPUT ;
    USE SIGNAL ;
    PORT
      LAYER M5 ;
        RECT  103.392 0 103.416 0.084 ;
    END
  END xbi[78]
  PIN xbi[79]
    DIRECTION INPUT ;
    USE SIGNAL ;
    PORT
      LAYER M5 ;
        RECT  103.536 0 103.56 0.084 ;
    END
  END xbi[79]
  PIN xbi[7]
    DIRECTION INPUT ;
    USE SIGNAL ;
    PORT
      LAYER M5 ;
        RECT  93.168 0 93.192 0.084 ;
    END
  END xbi[7]
  PIN xbi[80]
    DIRECTION INPUT ;
    USE SIGNAL ;
    PORT
      LAYER M5 ;
        RECT  103.68 0 103.704 0.084 ;
    END
  END xbi[80]
  PIN xbi[81]
    DIRECTION INPUT ;
    USE SIGNAL ;
    PORT
      LAYER M5 ;
        RECT  103.824 0 103.848 0.084 ;
    END
  END xbi[81]
  PIN xbi[82]
    DIRECTION INPUT ;
    USE SIGNAL ;
    PORT
      LAYER M5 ;
        RECT  103.968 0 103.992 0.084 ;
    END
  END xbi[82]
  PIN xbi[83]
    DIRECTION INPUT ;
    USE SIGNAL ;
    PORT
      LAYER M5 ;
        RECT  104.112 0 104.136 0.084 ;
    END
  END xbi[83]
  PIN xbi[84]
    DIRECTION INPUT ;
    USE SIGNAL ;
    PORT
      LAYER M5 ;
        RECT  104.256 0 104.28 0.084 ;
    END
  END xbi[84]
  PIN xbi[85]
    DIRECTION INPUT ;
    USE SIGNAL ;
    PORT
      LAYER M5 ;
        RECT  104.4 0 104.424 0.084 ;
    END
  END xbi[85]
  PIN xbi[86]
    DIRECTION INPUT ;
    USE SIGNAL ;
    PORT
      LAYER M5 ;
        RECT  104.544 0 104.568 0.084 ;
    END
  END xbi[86]
  PIN xbi[87]
    DIRECTION INPUT ;
    USE SIGNAL ;
    PORT
      LAYER M5 ;
        RECT  104.688 0 104.712 0.084 ;
    END
  END xbi[87]
  PIN xbi[88]
    DIRECTION INPUT ;
    USE SIGNAL ;
    PORT
      LAYER M5 ;
        RECT  104.832 0 104.856 0.084 ;
    END
  END xbi[88]
  PIN xbi[89]
    DIRECTION INPUT ;
    USE SIGNAL ;
    PORT
      LAYER M5 ;
        RECT  104.976 0 105 0.084 ;
    END
  END xbi[89]
  PIN xbi[8]
    DIRECTION INPUT ;
    USE SIGNAL ;
    PORT
      LAYER M5 ;
        RECT  93.312 0 93.336 0.084 ;
    END
  END xbi[8]
  PIN xbi[90]
    DIRECTION INPUT ;
    USE SIGNAL ;
    PORT
      LAYER M5 ;
        RECT  105.12 0 105.144 0.084 ;
    END
  END xbi[90]
  PIN xbi[91]
    DIRECTION INPUT ;
    USE SIGNAL ;
    PORT
      LAYER M5 ;
        RECT  105.264 0 105.288 0.084 ;
    END
  END xbi[91]
  PIN xbi[92]
    DIRECTION INPUT ;
    USE SIGNAL ;
    PORT
      LAYER M5 ;
        RECT  105.408 0 105.432 0.084 ;
    END
  END xbi[92]
  PIN xbi[93]
    DIRECTION INPUT ;
    USE SIGNAL ;
    PORT
      LAYER M5 ;
        RECT  105.552 0 105.576 0.084 ;
    END
  END xbi[93]
  PIN xbi[94]
    DIRECTION INPUT ;
    USE SIGNAL ;
    PORT
      LAYER M5 ;
        RECT  105.696 0 105.72 0.084 ;
    END
  END xbi[94]
  PIN xbi[95]
    DIRECTION INPUT ;
    USE SIGNAL ;
    PORT
      LAYER M5 ;
        RECT  105.84 0 105.864 0.084 ;
    END
  END xbi[95]
  PIN xbi[96]
    DIRECTION INPUT ;
    USE SIGNAL ;
    PORT
      LAYER M5 ;
        RECT  105.984 0 106.008 0.084 ;
    END
  END xbi[96]
  PIN xbi[97]
    DIRECTION INPUT ;
    USE SIGNAL ;
    PORT
      LAYER M5 ;
        RECT  106.128 0 106.152 0.084 ;
    END
  END xbi[97]
  PIN xbi[98]
    DIRECTION INPUT ;
    USE SIGNAL ;
    PORT
      LAYER M5 ;
        RECT  106.272 0 106.296 0.084 ;
    END
  END xbi[98]
  PIN xbi[99]
    DIRECTION INPUT ;
    USE SIGNAL ;
    PORT
      LAYER M5 ;
        RECT  106.416 0 106.44 0.084 ;
    END
  END xbi[99]
  PIN xbi[9]
    DIRECTION INPUT ;
    USE SIGNAL ;
    PORT
      LAYER M5 ;
        RECT  93.456 0 93.48 0.084 ;
    END
  END xbi[9]
  PIN VDD
    DIRECTION INOUT ;
    USE POWER ;
    PORT
      LAYER M5 ;
        RECT  169.992 2.151 170.112 28.089 ;
        RECT  167.292 2.151 167.412 28.089 ;
        RECT  164.592 2.151 164.712 28.089 ;
        RECT  161.892 2.151 162.012 28.089 ;
        RECT  159.192 2.151 159.312 28.089 ;
        RECT  156.492 2.151 156.612 28.089 ;
        RECT  153.792 2.151 153.912 28.089 ;
        RECT  151.092 2.151 151.212 28.089 ;
        RECT  148.392 2.151 148.512 28.089 ;
        RECT  145.692 2.151 145.812 28.089 ;
        RECT  142.992 2.151 143.112 28.089 ;
        RECT  140.292 2.151 140.412 28.089 ;
        RECT  137.592 2.151 137.712 28.089 ;
        RECT  134.892 2.151 135.012 28.089 ;
        RECT  132.192 2.151 132.312 28.089 ;
        RECT  129.492 2.151 129.612 28.089 ;
        RECT  126.792 2.151 126.912 28.089 ;
        RECT  124.092 2.151 124.212 28.089 ;
        RECT  121.392 2.151 121.512 28.089 ;
        RECT  118.692 2.151 118.812 28.089 ;
        RECT  115.992 2.151 116.112 28.089 ;
        RECT  113.292 2.151 113.412 28.089 ;
        RECT  110.592 2.151 110.712 28.089 ;
        RECT  107.892 2.151 108.012 28.089 ;
        RECT  105.192 2.151 105.312 28.089 ;
        RECT  102.492 2.151 102.612 28.089 ;
        RECT  99.792 2.151 99.912 28.089 ;
        RECT  97.092 2.151 97.212 28.089 ;
        RECT  94.392 2.151 94.512 28.089 ;
        RECT  91.692 2.151 91.812 28.089 ;
        RECT  88.992 2.151 89.112 28.089 ;
        RECT  86.292 2.151 86.412 28.089 ;
        RECT  83.592 2.151 83.712 28.089 ;
        RECT  80.892 2.151 81.012 28.089 ;
        RECT  78.192 2.151 78.312 28.089 ;
        RECT  75.492 2.151 75.612 28.089 ;
        RECT  72.792 2.151 72.912 28.089 ;
        RECT  70.092 2.151 70.212 28.089 ;
        RECT  67.392 2.151 67.512 28.089 ;
        RECT  64.692 2.151 64.812 28.089 ;
        RECT  61.992 2.151 62.112 28.089 ;
        RECT  59.292 2.151 59.412 28.089 ;
        RECT  56.592 2.151 56.712 28.089 ;
        RECT  53.892 2.151 54.012 28.089 ;
        RECT  51.192 2.151 51.312 28.089 ;
        RECT  48.492 2.151 48.612 28.089 ;
        RECT  45.792 2.151 45.912 28.089 ;
        RECT  43.092 2.151 43.212 28.089 ;
        RECT  40.392 2.151 40.512 28.089 ;
        RECT  37.692 2.151 37.812 28.089 ;
        RECT  34.992 2.151 35.112 28.089 ;
        RECT  32.292 2.151 32.412 28.089 ;
        RECT  29.592 2.151 29.712 28.089 ;
        RECT  26.892 2.151 27.012 28.089 ;
        RECT  24.192 2.151 24.312 28.089 ;
        RECT  21.492 2.151 21.612 28.089 ;
        RECT  18.792 2.151 18.912 28.089 ;
        RECT  16.092 2.151 16.212 28.089 ;
        RECT  13.392 2.151 13.512 28.089 ;
        RECT  10.692 2.151 10.812 28.089 ;
        RECT  7.992 2.151 8.112 28.089 ;
        RECT  5.292 2.151 5.412 28.089 ;
        RECT  2.592 2.151 2.712 28.089 ;
    END
  END VDD
  PIN VSS
    DIRECTION INOUT ;
    USE GROUND ;
    PORT
      LAYER M5 ;
        RECT  169.8 2.137 169.92 28.103 ;
        RECT  167.1 2.137 167.22 28.103 ;
        RECT  164.4 2.137 164.52 28.103 ;
        RECT  161.7 2.137 161.82 28.103 ;
        RECT  159 2.137 159.12 28.103 ;
        RECT  156.3 2.137 156.42 28.103 ;
        RECT  153.6 2.137 153.72 28.103 ;
        RECT  150.9 2.137 151.02 28.103 ;
        RECT  148.2 2.137 148.32 28.103 ;
        RECT  145.5 2.137 145.62 28.103 ;
        RECT  142.8 2.137 142.92 28.103 ;
        RECT  140.1 2.137 140.22 28.103 ;
        RECT  137.4 2.137 137.52 28.103 ;
        RECT  134.7 2.137 134.82 28.103 ;
        RECT  132 2.137 132.12 28.103 ;
        RECT  129.3 2.137 129.42 28.103 ;
        RECT  126.6 2.137 126.72 28.103 ;
        RECT  123.9 2.137 124.02 28.103 ;
        RECT  121.2 2.137 121.32 28.103 ;
        RECT  118.5 2.137 118.62 28.103 ;
        RECT  115.8 2.137 115.92 28.103 ;
        RECT  113.1 2.137 113.22 28.103 ;
        RECT  110.4 2.137 110.52 28.103 ;
        RECT  107.7 2.137 107.82 28.103 ;
        RECT  105 2.137 105.12 28.103 ;
        RECT  102.3 2.137 102.42 28.103 ;
        RECT  99.6 2.137 99.72 28.103 ;
        RECT  96.9 2.137 97.02 28.103 ;
        RECT  94.2 2.137 94.32 28.103 ;
        RECT  91.5 2.137 91.62 28.103 ;
        RECT  88.8 2.137 88.92 28.103 ;
        RECT  86.1 2.137 86.22 28.103 ;
        RECT  83.4 2.137 83.52 28.103 ;
        RECT  80.7 2.137 80.82 28.103 ;
        RECT  78 2.137 78.12 28.103 ;
        RECT  75.3 2.137 75.42 28.103 ;
        RECT  72.6 2.137 72.72 28.103 ;
        RECT  69.9 2.137 70.02 28.103 ;
        RECT  67.2 2.137 67.32 28.103 ;
        RECT  64.5 2.137 64.62 28.103 ;
        RECT  61.8 2.137 61.92 28.103 ;
        RECT  59.1 2.137 59.22 28.103 ;
        RECT  56.4 2.137 56.52 28.103 ;
        RECT  53.7 2.137 53.82 28.103 ;
        RECT  51 2.137 51.12 28.103 ;
        RECT  48.3 2.137 48.42 28.103 ;
        RECT  45.6 2.137 45.72 28.103 ;
        RECT  42.9 2.137 43.02 28.103 ;
        RECT  40.2 2.137 40.32 28.103 ;
        RECT  37.5 2.137 37.62 28.103 ;
        RECT  34.8 2.137 34.92 28.103 ;
        RECT  32.1 2.137 32.22 28.103 ;
        RECT  29.4 2.137 29.52 28.103 ;
        RECT  26.7 2.137 26.82 28.103 ;
        RECT  24 2.137 24.12 28.103 ;
        RECT  21.3 2.137 21.42 28.103 ;
        RECT  18.6 2.137 18.72 28.103 ;
        RECT  15.9 2.137 16.02 28.103 ;
        RECT  13.2 2.137 13.32 28.103 ;
        RECT  10.5 2.137 10.62 28.103 ;
        RECT  7.8 2.137 7.92 28.103 ;
        RECT  5.1 2.137 5.22 28.103 ;
        RECT  2.4 2.137 2.52 28.103 ;
    END
  END VSS
  # OT_OBS_CLOSED layer=M5 d_um=1.536 added=120
  OBS
    LAYER RVTN ;
     RECT  2.16 2.16 170.64 2.295 ;
     RECT  2.16 2.565 170.64 2.835 ;
     RECT  2.16 3.105 170.64 3.375 ;
     RECT  2.16 3.645 170.64 3.915 ;
     RECT  2.16 4.185 170.64 4.455 ;
     RECT  2.16 4.725 170.64 4.995 ;
     RECT  2.16 5.265 170.64 5.535 ;
     RECT  2.16 5.805 170.64 6.075 ;
     RECT  2.16 6.345 170.64 6.615 ;
     RECT  2.16 6.885 170.64 7.155 ;
     RECT  2.16 7.425 170.64 7.695 ;
     RECT  2.16 7.965 170.64 8.235 ;
     RECT  2.16 8.505 170.64 8.775 ;
     RECT  2.16 9.045 170.64 9.315 ;
     RECT  2.16 9.585 170.64 9.855 ;
     RECT  2.16 10.125 170.64 10.395 ;
     RECT  2.16 10.665 170.64 10.935 ;
     RECT  2.16 11.205 170.64 11.475 ;
     RECT  2.16 11.745 170.64 12.015 ;
     RECT  2.16 12.285 170.64 12.555 ;
     RECT  2.16 12.825 170.64 13.095 ;
     RECT  2.16 13.365 170.64 13.635 ;
     RECT  2.16 13.905 170.64 14.175 ;
     RECT  2.16 14.445 170.64 14.715 ;
     RECT  2.16 14.985 170.64 15.255 ;
     RECT  2.16 15.525 170.64 15.795 ;
     RECT  2.16 16.065 170.64 16.335 ;
     RECT  2.16 16.605 170.64 16.875 ;
     RECT  2.16 17.145 170.64 17.415 ;
     RECT  2.16 17.685 170.64 17.955 ;
     RECT  2.16 18.225 170.64 18.495 ;
     RECT  2.16 18.765 170.64 19.035 ;
     RECT  2.16 19.305 170.64 19.575 ;
     RECT  2.16 19.845 170.64 20.115 ;
     RECT  2.16 20.385 170.64 20.655 ;
     RECT  2.16 20.925 170.64 21.195 ;
     RECT  2.16 21.465 170.64 21.735 ;
     RECT  2.16 22.005 170.64 22.275 ;
     RECT  2.16 22.545 170.64 22.815 ;
     RECT  2.16 23.085 170.64 23.355 ;
     RECT  2.16 23.625 170.64 23.895 ;
     RECT  2.16 24.165 170.64 24.435 ;
     RECT  2.16 24.705 170.64 24.975 ;
     RECT  2.16 25.245 170.64 25.515 ;
     RECT  2.16 25.785 170.64 26.055 ;
     RECT  2.16 26.325 170.64 26.595 ;
     RECT  2.16 26.865 170.64 27.135 ;
     RECT  2.16 27.405 170.64 27.675 ;
     RECT  2.16 27.945 170.64 28.08 ;
    LAYER RVTP ;
     RECT  2.16 2.295 170.64 2.565 ;
     RECT  2.16 2.835 170.64 3.105 ;
     RECT  2.16 3.375 170.64 3.645 ;
     RECT  2.16 3.915 170.64 4.185 ;
     RECT  2.16 4.455 170.64 4.725 ;
     RECT  2.16 4.995 170.64 5.265 ;
     RECT  2.16 5.535 170.64 5.805 ;
     RECT  2.16 6.075 170.64 6.345 ;
     RECT  2.16 6.615 170.64 6.885 ;
     RECT  2.16 7.155 170.64 7.425 ;
     RECT  2.16 7.695 170.64 7.965 ;
     RECT  2.16 8.235 170.64 8.505 ;
     RECT  2.16 8.775 170.64 9.045 ;
     RECT  2.16 9.315 170.64 9.585 ;
     RECT  2.16 9.855 170.64 10.125 ;
     RECT  2.16 10.395 170.64 10.665 ;
     RECT  2.16 10.935 170.64 11.205 ;
     RECT  2.16 11.475 170.64 11.745 ;
     RECT  2.16 12.015 170.64 12.285 ;
     RECT  2.16 12.555 170.64 12.825 ;
     RECT  2.16 13.095 170.64 13.365 ;
     RECT  2.16 13.635 170.64 13.905 ;
     RECT  2.16 14.175 170.64 14.445 ;
     RECT  2.16 14.715 170.64 14.985 ;
     RECT  2.16 15.255 170.64 15.525 ;
     RECT  2.16 15.795 170.64 16.065 ;
     RECT  2.16 16.335 170.64 16.605 ;
     RECT  2.16 16.875 170.64 17.145 ;
     RECT  2.16 17.415 170.64 17.685 ;
     RECT  2.16 17.955 170.64 18.225 ;
     RECT  2.16 18.495 170.64 18.765 ;
     RECT  2.16 19.035 170.64 19.305 ;
     RECT  2.16 19.575 170.64 19.845 ;
     RECT  2.16 20.115 170.64 20.385 ;
     RECT  2.16 20.655 170.64 20.925 ;
     RECT  2.16 21.195 170.64 21.465 ;
     RECT  2.16 21.735 170.64 22.005 ;
     RECT  2.16 22.275 170.64 22.545 ;
     RECT  2.16 22.815 170.64 23.085 ;
     RECT  2.16 23.355 170.64 23.625 ;
     RECT  2.16 23.895 170.64 24.165 ;
     RECT  2.16 24.435 170.64 24.705 ;
     RECT  2.16 24.975 170.64 25.245 ;
     RECT  2.16 25.515 170.64 25.785 ;
     RECT  2.16 26.055 170.64 26.325 ;
     RECT  2.16 26.595 170.64 26.865 ;
     RECT  2.16 27.135 170.64 27.405 ;
     RECT  2.16 27.675 170.64 27.945 ;
    LAYER M1 ;
     RECT  2.16 2.151 170.64 28.089 ;
    LAYER M2 ;
     RECT  50.359 0.414 53.239 0.432 ;
     RECT  53.239 0.414 55.003 1.008 ;
     RECT  2.16 2.151 55.003 28.089 ;
     RECT  55.003 0.414 65.227 28.089 ;
     RECT  76.747 29.034 76.847 29.052 ;
     RECT  78.979 29.034 79.115 29.052 ;
     RECT  80.023 29.034 80.663 29.052 ;
     RECT  110.767 29.034 110.939 29.052 ;
     RECT  65.227 0.342 139.667 28.089 ;
     RECT  139.667 0.378 142.583 28.089 ;
     RECT  142.583 0.45 162.131 28.089 ;
     RECT  162.131 0.45 163.859 0.9 ;
     RECT  163.859 0.45 164.291 0.549 ;
     RECT  164.291 0.531 167.027 0.549 ;
     RECT  162.131 2.034 169.799 28.089 ;
     RECT  169.799 2.151 170.64 28.089 ;
     RECT  170.64 5.31 170.987 5.49 ;
     RECT  170.64 3.582 171.059 4.41 ;
     RECT  171.059 3.582 171.311 3.6 ;
     RECT  171.059 4.392 171.599 4.41 ;
     RECT  170.987 5.31 171.779 5.328 ;
    LAYER M3 ;
     RECT  170.316 0.091 170.334 0.187 ;
     RECT  65.232 0.337 65.25 0.373 ;
     RECT  169.02 0.475 169.038 0.523 ;
     RECT  170.316 0.187 170.37 0.523 ;
     RECT  89.46 0.091 89.478 0.571 ;
     RECT  93.024 0.523 93.042 0.571 ;
     RECT  169.02 0.523 170.37 0.571 ;
     RECT  84.132 0.526 84.15 0.877 ;
     RECT  164.268 0.445 164.286 0.877 ;
     RECT  136.224 0.481 136.242 0.913 ;
     RECT  169.02 0.571 170.622 0.955 ;
     RECT  139.644 0.337 139.662 1.021 ;
     RECT  132.228 0.409 132.246 1.051 ;
     RECT  87.768 0.091 87.786 1.099 ;
     RECT  93.024 0.571 93.546 1.099 ;
     RECT  169.02 0.955 170.982 1.099 ;
     RECT  171.756 0.091 171.774 1.099 ;
     RECT  159.336 0.523 159.354 1.111 ;
     RECT  98.172 0.091 98.19 1.147 ;
     RECT  99.972 0.523 99.99 1.147 ;
     RECT  131.76 1.051 132.246 1.147 ;
     RECT  135.36 0.985 135.378 1.417 ;
     RECT  147.672 1.099 147.69 1.453 ;
     RECT  136.224 0.913 136.962 1.525 ;
     RECT  68.688 1.453 68.706 1.561 ;
     RECT  161.676 0.949 161.694 1.606 ;
     RECT  73.908 1.066 73.926 1.687 ;
     RECT  156.204 1.066 156.222 1.687 ;
     RECT  87.768 1.099 87.966 1.723 ;
     RECT  89.46 0.571 89.658 1.723 ;
     RECT  91.008 0.091 91.026 1.723 ;
     RECT  93.024 1.099 94.158 1.723 ;
     RECT  98.064 1.147 98.19 1.723 ;
     RECT  99.972 1.147 100.062 1.723 ;
     RECT  110.844 0.091 110.862 1.723 ;
     RECT  123.264 0.091 123.282 1.723 ;
     RECT  125.424 0.523 125.442 1.723 ;
     RECT  131.724 1.147 132.246 1.723 ;
     RECT  133.416 0.523 133.434 1.723 ;
     RECT  134.928 1.417 135.378 1.723 ;
     RECT  136.224 1.525 137.394 1.723 ;
     RECT  139.644 1.021 139.986 1.723 ;
     RECT  142.56 0.373 142.578 1.723 ;
     RECT  143.424 1.651 143.442 1.723 ;
     RECT  144.828 1.147 144.846 1.723 ;
     RECT  147.672 1.453 148.374 1.723 ;
     RECT  150.804 1.561 150.822 1.723 ;
     RECT  153.468 1.489 153.486 1.723 ;
     RECT  156.204 1.687 156.51 1.723 ;
     RECT  159.156 1.111 159.354 1.723 ;
     RECT  161.676 1.606 162.126 1.723 ;
     RECT  163.836 0.877 164.286 1.723 ;
     RECT  167.004 0.526 167.022 1.723 ;
     RECT  169.02 1.099 171.774 1.723 ;
     RECT  103.392 1.723 104.274 1.771 ;
     RECT  106.452 1.723 107.586 1.771 ;
     RECT  113.76 1.723 116.226 1.771 ;
     RECT  117.144 1.723 118.242 1.771 ;
     RECT  118.98 1.723 121.77 1.771 ;
     RECT  122.832 1.723 123.822 1.771 ;
     RECT  129.852 1.723 130.374 1.771 ;
     RECT  131.364 1.723 140.058 1.771 ;
     RECT  141.084 1.723 154.422 1.771 ;
     RECT  155.268 1.723 157.806 1.771 ;
     RECT  158.544 1.723 159.894 1.771 ;
     RECT  160.632 1.723 171.774 1.771 ;
     RECT  106.452 1.771 108.198 1.819 ;
     RECT  109.116 1.723 112.842 1.819 ;
     RECT  113.616 1.771 116.226 1.819 ;
     RECT  117.144 1.771 121.77 1.819 ;
     RECT  122.652 1.771 123.822 1.819 ;
     RECT  125.1 1.723 125.442 1.819 ;
     RECT  126.396 1.723 129.006 1.819 ;
     RECT  129.852 1.771 130.446 1.819 ;
     RECT  97.56 1.723 102.078 1.915 ;
     RECT  131.184 1.771 140.058 1.915 ;
     RECT  141.084 1.771 157.806 1.915 ;
     RECT  61.38 1.876 61.398 1.957 ;
     RECT  97.452 1.915 102.078 1.963 ;
     RECT  106.416 1.819 116.226 1.993 ;
     RECT  117.108 1.819 121.806 1.993 ;
     RECT  122.652 1.819 125.442 1.993 ;
     RECT  126.396 1.819 130.446 1.993 ;
     RECT  91.944 1.723 96.606 2.011 ;
     RECT  97.38 1.963 102.078 2.011 ;
     RECT  103.392 1.771 104.958 2.011 ;
     RECT  105.732 1.993 130.446 2.011 ;
     RECT  103.392 2.011 130.446 2.065 ;
     RECT  131.184 1.915 157.806 2.065 ;
     RECT  62.352 1.921 62.37 2.101 ;
     RECT  50.364 0.409 50.382 2.143 ;
     RECT  53.244 0.985 53.262 2.143 ;
     RECT  54.18 0.481 54.198 2.143 ;
     RECT  56.124 0.913 56.142 2.143 ;
     RECT  61.38 1.957 61.434 2.143 ;
     RECT  62.352 2.101 63.054 2.143 ;
     RECT  64.116 1.417 64.134 2.143 ;
     RECT  65.232 0.373 65.862 2.143 ;
     RECT  72.18 1.489 72.198 2.143 ;
     RECT  73.404 1.687 73.926 2.143 ;
     RECT  75.168 1.111 75.186 2.143 ;
     RECT  80.064 0.949 80.082 2.143 ;
     RECT  84.132 0.877 84.186 2.143 ;
     RECT  91.008 1.723 91.17 2.143 ;
     RECT  91.944 2.011 102.222 2.143 ;
     RECT  91.008 2.143 102.405 2.191 ;
     RECT  103.392 2.065 157.806 2.191 ;
     RECT  158.544 1.771 171.774 2.191 ;
     RECT  86.115 2.143 86.205 2.371 ;
     RECT  87.768 1.723 89.91 2.371 ;
     RECT  91.008 2.191 171.774 2.371 ;
     RECT  2.415 2.143 2.505 2.413 ;
     RECT  5.115 2.143 5.205 2.413 ;
     RECT  7.815 2.143 7.905 2.413 ;
     RECT  10.515 2.143 10.605 2.413 ;
     RECT  13.215 2.143 13.305 2.413 ;
     RECT  15.915 2.143 16.005 2.413 ;
     RECT  18.615 2.143 18.705 2.413 ;
     RECT  21.315 2.143 21.405 2.413 ;
     RECT  24.015 2.143 24.105 2.413 ;
     RECT  26.715 2.143 26.805 2.413 ;
     RECT  29.415 2.143 29.505 2.413 ;
     RECT  32.115 2.143 32.205 2.413 ;
     RECT  34.815 2.143 34.905 2.413 ;
     RECT  37.515 2.143 37.605 2.413 ;
     RECT  40.215 2.143 40.305 2.413 ;
     RECT  42.915 2.143 43.005 2.413 ;
     RECT  45.615 2.143 45.705 2.413 ;
     RECT  48.315 2.143 48.405 2.413 ;
     RECT  50.364 2.143 51.105 2.413 ;
     RECT  56.124 2.143 56.505 2.413 ;
     RECT  59.115 2.143 59.205 2.413 ;
     RECT  67.215 2.143 67.305 2.413 ;
     RECT  68.184 1.561 68.706 2.413 ;
     RECT  69.915 2.143 70.005 2.413 ;
     RECT  75.168 2.143 75.405 2.413 ;
     RECT  78.015 2.143 78.105 2.413 ;
     RECT  80.064 2.143 80.805 2.413 ;
     RECT  86.115 2.371 86.886 2.641 ;
     RECT  87.696 2.371 171.774 2.641 ;
     RECT  45.615 2.413 45.897 3.037 ;
     RECT  82.44 0.445 82.458 3.037 ;
     RECT  83.415 2.143 84.186 3.037 ;
     RECT  64.116 2.143 65.862 3.073 ;
     RECT  49.536 2.839 49.554 3.109 ;
     RECT  50.364 2.413 51.297 3.109 ;
     RECT  82.44 3.037 84.186 3.209 ;
     RECT  86.115 2.641 171.774 3.299 ;
     RECT  59.115 2.413 59.397 3.643 ;
     RECT  60.336 1.651 60.354 3.643 ;
     RECT  53.244 2.143 54.198 3.721 ;
     RECT  55.008 1.525 55.026 3.721 ;
     RECT  72.18 2.143 73.926 3.955 ;
     RECT  56.124 2.413 56.697 4.261 ;
     RECT  49.536 3.109 51.297 4.387 ;
     RECT  87.768 3.299 171.774 4.415 ;
     RECT  63.828 3.073 65.862 4.423 ;
     RECT  83.415 3.209 84.186 4.963 ;
     RECT  171.756 4.415 171.774 5.333 ;
     RECT  75.168 2.413 75.597 5.467 ;
     RECT  87.768 4.415 170.982 5.495 ;
     RECT  57.924 1.021 57.942 5.503 ;
     RECT  59.115 3.643 60.354 5.503 ;
     RECT  75.168 5.467 75.942 5.539 ;
     RECT  52.272 4.459 52.29 5.881 ;
     RECT  86.115 3.299 86.994 5.971 ;
     RECT  79.128 1.606 79.146 6.043 ;
     RECT  80.064 2.413 80.997 6.043 ;
     RECT  56.124 4.261 57.078 6.115 ;
     RECT  75.168 5.539 76.662 6.241 ;
     RECT  45.615 3.037 46.602 6.511 ;
     RECT  47.448 4.351 47.466 6.511 ;
     RECT  49.428 4.387 51.297 6.583 ;
     RECT  52.128 5.881 52.29 6.583 ;
     RECT  85.68 5.971 86.994 6.691 ;
     RECT  87.768 5.495 170.514 6.691 ;
     RECT  75.168 6.241 76.698 7.123 ;
     RECT  67.215 2.413 68.706 7.159 ;
     RECT  69.915 2.413 70.197 7.159 ;
     RECT  55.836 6.115 57.078 7.231 ;
     RECT  57.924 5.503 60.354 7.231 ;
     RECT  45.615 6.511 47.466 7.627 ;
     RECT  83.415 4.963 84.726 7.735 ;
     RECT  85.68 6.691 170.514 7.735 ;
     RECT  71.712 3.955 73.926 7.933 ;
     RECT  75.132 7.123 76.698 7.933 ;
     RECT  45.615 7.627 47.574 8.203 ;
     RECT  48.315 2.413 48.597 8.203 ;
     RECT  53.244 3.721 55.026 8.311 ;
     RECT  55.836 7.231 60.354 8.311 ;
     RECT  63.828 4.423 66.474 8.401 ;
     RECT  67.215 7.159 70.197 8.401 ;
     RECT  61.38 2.143 63.054 8.509 ;
     RECT  63.828 8.401 70.197 8.509 ;
     RECT  71.712 7.933 76.698 8.815 ;
     RECT  78.015 2.413 78.297 8.815 ;
     RECT  70.956 8.473 70.974 8.851 ;
     RECT  71.712 8.815 78.297 8.851 ;
     RECT  49.428 6.583 52.29 8.941 ;
     RECT  53.244 8.311 60.354 8.941 ;
     RECT  83.415 7.735 170.514 9.005 ;
     RECT  82.44 3.209 82.458 9.481 ;
     RECT  83.415 9.005 150.102 9.481 ;
     RECT  82.44 9.481 150.102 9.545 ;
     RECT  49.428 8.941 60.354 10.669 ;
     RECT  61.38 8.509 70.197 10.669 ;
     RECT  79.128 6.043 80.997 11.101 ;
     RECT  150.876 9.005 170.514 11.273 ;
     RECT  82.44 9.545 86.397 11.713 ;
     RECT  49.428 10.669 70.197 12.289 ;
     RECT  70.956 8.851 78.297 12.289 ;
     RECT  87.192 9.545 150.102 12.929 ;
     RECT  150.915 11.273 170.514 13.373 ;
     RECT  87.192 12.929 147.114 13.469 ;
     RECT  81.792 11.713 86.397 13.837 ;
     RECT  87.192 13.469 137.97 13.837 ;
     RECT  81.792 13.837 137.97 13.973 ;
     RECT  147.924 12.929 150.102 14.009 ;
     RECT  150.915 13.373 161.997 14.243 ;
     RECT  0.108 14.587 0.126 14.717 ;
     RECT  87.192 13.973 137.97 15.323 ;
     RECT  2.415 2.413 2.697 15.592 ;
     RECT  5.115 2.413 5.397 15.592 ;
     RECT  7.815 2.413 8.097 15.595 ;
     RECT  2.304 15.592 2.697 15.629 ;
     RECT  5.004 15.592 5.397 15.629 ;
     RECT  44.64 15.565 44.658 15.719 ;
     RECT  7.704 15.595 8.097 15.755 ;
     RECT  162.72 13.373 170.514 15.755 ;
     RECT  135.72 15.323 137.97 15.791 ;
     RECT  150.915 14.243 160.866 15.827 ;
     RECT  87.192 15.323 134.997 16.375 ;
     RECT  87.156 16.375 134.997 16.439 ;
     RECT  138.78 13.469 147.114 16.871 ;
     RECT  133.848 16.439 134.997 16.979 ;
     RECT  138.78 16.871 147.078 17.411 ;
     RECT  135.72 15.791 137.697 17.447 ;
     RECT  49.428 12.289 78.297 17.455 ;
     RECT  79.02 11.101 80.997 17.455 ;
     RECT  148.104 14.009 150.102 17.519 ;
     RECT  133.848 16.979 133.866 17.987 ;
     RECT  138.78 17.411 146.214 18.527 ;
     RECT  81.792 13.973 86.397 18.805 ;
     RECT  87.156 16.439 132.93 18.805 ;
     RECT  138.78 18.527 141.03 19.103 ;
     RECT  49.428 17.455 80.997 19.111 ;
     RECT  81.792 18.805 132.93 19.111 ;
     RECT  141.876 18.527 146.214 19.265 ;
     RECT  49.428 19.111 132.93 19.301 ;
     RECT  158.4 15.827 160.866 19.679 ;
     RECT  162.72 15.755 169.038 19.769 ;
     RECT  148.104 17.519 150.066 19.805 ;
     RECT  150.915 15.827 157.59 19.841 ;
     RECT  49.428 19.301 132.297 19.913 ;
     RECT  135.936 17.447 137.697 20.309 ;
     RECT  160.128 19.679 160.866 20.381 ;
     RECT  149.688 19.805 150.066 20.417 ;
     RECT  147.06 17.411 147.078 20.453 ;
     RECT  49.428 19.913 130.806 20.687 ;
     RECT  165.672 19.769 169.038 20.723 ;
     RECT  137.088 20.309 137.697 20.759 ;
     RECT  162.72 19.769 164.898 20.957 ;
     RECT  150.915 19.841 153.897 20.993 ;
     RECT  162.72 20.957 163.314 21.191 ;
     RECT  154.728 19.841 157.59 21.299 ;
     RECT  169.815 15.755 170.514 21.533 ;
     RECT  45.615 8.203 48.597 21.811 ;
     RECT  165.672 20.723 167.397 22.037 ;
     RECT  45.615 21.811 48.654 22.081 ;
     RECT  49.428 20.687 130.482 22.081 ;
     RECT  156.315 21.299 157.59 22.235 ;
     RECT  135.936 20.309 135.954 22.379 ;
     RECT  168.48 20.723 169.038 22.577 ;
     RECT  160.128 20.381 160.506 22.613 ;
     RECT  141.876 19.265 145.797 22.649 ;
     RECT  165.672 22.037 166.194 22.811 ;
     RECT  157.572 22.235 157.59 22.919 ;
     RECT  158.4 19.679 159.297 23.053 ;
     RECT  157.896 23.053 159.297 23.081 ;
     RECT  149.688 20.417 149.706 23.117 ;
     RECT  157.896 23.081 157.914 23.153 ;
     RECT  168.624 22.577 169.038 23.189 ;
     RECT  138.78 19.103 140.397 23.351 ;
     RECT  164.415 20.957 164.898 23.657 ;
     RECT  158.832 23.081 159.297 23.693 ;
     RECT  148.104 19.805 148.497 23.729 ;
     RECT  168.624 23.189 168.642 23.855 ;
     RECT  141.876 22.649 144.63 23.891 ;
     RECT  45.615 22.081 130.482 23.935 ;
     RECT  45.615 23.935 130.95 23.971 ;
     RECT  142.815 23.891 144.63 23.999 ;
     RECT  160.128 22.613 160.146 24.233 ;
     RECT  154.728 21.299 155.322 24.269 ;
     RECT  45.615 23.971 131.022 24.331 ;
     RECT  132.015 19.913 132.297 24.331 ;
     RECT  166.176 22.811 166.194 24.359 ;
     RECT  150.915 20.993 151.974 24.737 ;
     RECT  142.815 23.999 143.91 24.773 ;
     RECT  151.956 24.737 151.974 24.809 ;
     RECT  45.615 24.331 132.297 24.971 ;
     RECT  162.72 21.191 162.738 24.971 ;
     RECT  45.615 24.971 130.878 25.051 ;
     RECT  45.576 25.051 130.878 25.079 ;
     RECT  152.928 20.993 153.897 25.079 ;
     RECT  45.576 25.079 130.806 25.169 ;
     RECT  131.652 24.971 132.297 25.277 ;
     RECT  155.304 24.269 155.322 25.277 ;
     RECT  139.428 23.351 140.397 25.619 ;
     RECT  141.876 23.891 141.894 25.817 ;
     RECT  142.815 24.773 143.586 26.861 ;
     RECT  45.615 25.169 130.806 27.031 ;
     RECT  45.252 27.031 130.806 27.175 ;
     RECT  45.072 27.175 130.806 27.481 ;
     RECT  44.82 27.481 130.806 27.751 ;
     RECT  2.415 15.629 2.697 27.827 ;
     RECT  5.115 15.629 5.397 27.827 ;
     RECT  7.815 15.755 8.097 27.827 ;
     RECT  10.515 2.413 10.797 27.827 ;
     RECT  13.215 2.413 13.497 27.827 ;
     RECT  15.915 2.413 16.197 27.827 ;
     RECT  18.615 2.413 18.897 27.827 ;
     RECT  21.315 2.413 21.597 27.827 ;
     RECT  24.015 2.413 24.297 27.827 ;
     RECT  26.715 2.413 26.997 27.827 ;
     RECT  29.415 2.413 29.697 27.827 ;
     RECT  32.115 2.413 32.397 27.827 ;
     RECT  34.815 2.413 35.097 27.827 ;
     RECT  37.515 2.413 37.797 27.827 ;
     RECT  40.215 2.413 40.497 27.827 ;
     RECT  42.915 2.413 43.197 27.827 ;
     RECT  132.015 25.277 132.297 27.827 ;
     RECT  134.715 16.979 134.997 27.827 ;
     RECT  137.415 20.759 137.697 27.827 ;
     RECT  140.115 25.619 140.397 27.827 ;
     RECT  142.815 26.861 143.097 27.827 ;
     RECT  145.515 22.649 145.797 27.827 ;
     RECT  148.215 23.729 148.497 27.827 ;
     RECT  150.915 24.737 151.197 27.827 ;
     RECT  153.615 25.079 153.897 27.827 ;
     RECT  156.315 22.235 156.597 27.827 ;
     RECT  159.015 23.693 159.297 27.827 ;
     RECT  161.715 14.243 161.997 27.827 ;
     RECT  164.415 23.657 164.697 27.827 ;
     RECT  167.115 22.037 167.397 27.827 ;
     RECT  169.815 21.533 170.097 27.827 ;
     RECT  44.136 27.751 130.806 27.841 ;
     RECT  44.136 27.841 130.914 27.869 ;
     RECT  124.848 27.869 130.914 27.877 ;
     RECT  90.252 27.869 92.97 27.917 ;
     RECT  44.568 27.869 54.378 27.941 ;
     RECT  55.26 27.869 59.205 27.941 ;
     RECT  60.948 27.869 61.905 27.941 ;
     RECT  62.892 27.869 65.034 27.941 ;
     RECT  66.168 27.869 66.186 27.941 ;
     RECT  70.776 27.869 71.658 27.941 ;
     RECT  72.615 27.869 72.954 27.941 ;
     RECT  74.016 27.869 74.07 27.941 ;
     RECT  76.68 27.869 76.806 27.941 ;
     RECT  79.092 27.869 80.805 27.941 ;
     RECT  81.72 27.869 82.062 27.941 ;
     RECT  85.176 27.869 86.778 27.941 ;
     RECT  90.324 27.917 92.97 27.941 ;
     RECT  95.076 27.869 97.326 27.941 ;
     RECT  98.172 27.869 98.226 27.941 ;
     RECT  99.288 27.869 100.71 27.941 ;
     RECT  101.7 27.869 102.405 27.941 ;
     RECT  103.932 27.869 103.95 27.941 ;
     RECT  105.84 27.869 109.17 27.941 ;
     RECT  110.088 27.869 111.33 27.941 ;
     RECT  114.876 27.869 115.905 27.941 ;
     RECT  116.712 27.869 117.45 27.941 ;
     RECT  118.26 27.869 119.07 27.941 ;
     RECT  124.848 27.877 131.058 27.941 ;
     RECT  50.436 27.941 51.642 27.965 ;
     RECT  62.892 27.941 64.605 27.965 ;
     RECT  74.016 27.941 74.034 27.965 ;
     RECT  74.808 27.869 75.798 27.965 ;
     RECT  77.616 27.869 78.105 27.965 ;
     RECT  106.308 27.941 107.805 27.965 ;
     RECT  120.24 27.869 121.305 27.965 ;
     RECT  126.615 27.941 131.058 27.965 ;
     RECT  63.072 27.965 64.605 27.977 ;
     RECT  106.416 27.965 106.866 28.013 ;
     RECT  128.448 27.965 131.058 28.013 ;
     RECT  116.712 27.941 117.378 28.049 ;
     RECT  128.664 28.013 131.058 28.049 ;
     RECT  63.072 27.977 63.234 28.061 ;
     RECT  2.415 27.827 2.505 28.097 ;
     RECT  5.115 27.827 5.205 28.097 ;
     RECT  7.815 27.827 7.905 28.097 ;
     RECT  10.515 27.827 10.605 28.097 ;
     RECT  13.215 27.827 13.305 28.097 ;
     RECT  15.915 27.827 16.005 28.097 ;
     RECT  18.615 27.827 18.705 28.097 ;
     RECT  21.315 27.827 21.405 28.097 ;
     RECT  24.015 27.827 24.105 28.097 ;
     RECT  26.715 27.827 26.805 28.097 ;
     RECT  29.415 27.827 29.505 28.097 ;
     RECT  32.115 27.827 32.205 28.097 ;
     RECT  34.815 27.827 34.905 28.097 ;
     RECT  37.515 27.827 37.605 28.097 ;
     RECT  40.215 27.827 40.305 28.097 ;
     RECT  42.915 27.827 43.005 28.097 ;
     RECT  44.784 27.941 49.446 28.097 ;
     RECT  57.852 27.941 59.205 28.097 ;
     RECT  61.488 27.941 61.905 28.097 ;
     RECT  64.476 27.977 64.605 28.097 ;
     RECT  67.215 27.869 70.005 28.097 ;
     RECT  72.615 27.941 72.705 28.097 ;
     RECT  74.808 27.965 75.405 28.097 ;
     RECT  78.015 27.965 78.105 28.097 ;
     RECT  80.136 27.941 80.805 28.097 ;
     RECT  83.268 27.869 84.114 28.097 ;
     RECT  85.716 27.941 86.205 28.097 ;
     RECT  94.215 27.869 94.305 28.097 ;
     RECT  96.48 27.941 97.326 28.097 ;
     RECT  102.315 27.941 102.405 28.097 ;
     RECT  104.796 27.869 105.105 28.097 ;
     RECT  107.715 27.965 107.805 28.097 ;
     RECT  110.415 27.941 111.33 28.097 ;
     RECT  112.608 27.869 113.205 28.097 ;
     RECT  114.912 27.941 115.905 28.097 ;
     RECT  120.528 27.965 121.305 28.097 ;
     RECT  123.732 27.869 124.005 28.097 ;
     RECT  126.615 27.965 127.566 28.097 ;
     RECT  128.664 28.049 130.914 28.097 ;
     RECT  132.015 27.827 132.105 28.097 ;
     RECT  134.715 27.827 134.805 28.097 ;
     RECT  137.415 27.827 137.505 28.097 ;
     RECT  140.115 27.827 140.205 28.097 ;
     RECT  142.815 27.827 142.905 28.097 ;
     RECT  145.515 27.827 145.605 28.097 ;
     RECT  148.215 27.827 148.305 28.097 ;
     RECT  150.915 27.827 151.005 28.097 ;
     RECT  153.615 27.827 153.705 28.097 ;
     RECT  156.315 27.827 156.405 28.097 ;
     RECT  159.015 27.827 159.105 28.097 ;
     RECT  161.715 27.827 161.805 28.097 ;
     RECT  164.415 27.827 164.505 28.097 ;
     RECT  167.115 27.827 167.205 28.097 ;
     RECT  169.815 27.827 169.905 28.097 ;
     RECT  104.796 28.097 104.814 28.205 ;
     RECT  129.672 28.097 130.914 28.205 ;
     RECT  55.26 27.941 56.934 28.253 ;
     RECT  63.108 28.061 63.234 28.253 ;
     RECT  74.808 28.097 75.294 28.253 ;
     RECT  97.272 28.097 97.326 28.253 ;
     RECT  128.664 28.097 128.934 28.253 ;
     RECT  123.732 28.097 123.75 28.349 ;
     RECT  127.008 28.097 127.566 28.349 ;
     RECT  48.78 28.097 49.446 28.493 ;
     RECT  52.524 27.941 54.09 28.493 ;
     RECT  57.852 28.097 59.058 28.493 ;
     RECT  63.108 28.253 63.126 28.493 ;
     RECT  88.704 27.869 89.37 28.493 ;
     RECT  90.324 27.941 92.646 28.493 ;
     RECT  99.54 27.941 100.71 28.493 ;
     RECT  127.548 28.349 127.566 28.493 ;
     RECT  128.664 28.253 128.826 28.493 ;
     RECT  48.78 28.493 49.374 28.541 ;
     RECT  50.436 27.965 51.57 28.541 ;
     RECT  55.26 28.253 55.278 28.541 ;
     RECT  61.488 28.097 61.506 28.541 ;
     RECT  68.004 28.097 69.57 28.541 ;
     RECT  70.992 27.941 71.37 28.541 ;
     RECT  74.808 28.253 74.826 28.541 ;
     RECT  81.72 27.941 81.738 28.541 ;
     RECT  83.268 28.097 83.286 28.541 ;
     RECT  90.324 28.493 90.522 28.541 ;
     RECT  96.48 28.097 96.498 28.541 ;
     RECT  106.848 28.013 106.866 28.541 ;
     RECT  110.916 28.097 111.33 28.541 ;
     RECT  112.608 28.097 112.626 28.541 ;
     RECT  114.912 28.097 115.146 28.541 ;
     RECT  118.26 27.941 118.926 28.541 ;
     RECT  120.528 28.097 120.762 28.541 ;
     RECT  56.556 28.253 56.934 28.589 ;
     RECT  71.136 28.541 71.37 28.637 ;
     RECT  130.5 28.205 130.914 28.781 ;
     RECT  50.436 28.541 50.958 28.829 ;
     RECT  56.556 28.589 56.574 28.829 ;
     RECT  130.5 28.781 130.518 28.829 ;
     RECT  116.712 28.049 116.802 28.877 ;
     RECT  84.096 28.097 84.114 28.973 ;
     RECT  85.716 28.097 85.842 29.021 ;
     RECT  112.824 28.843 112.878 29.021 ;
     RECT  76.752 27.941 76.806 29.029 ;
     RECT  79.092 27.941 79.11 29.029 ;
     RECT  80.136 28.097 80.514 29.029 ;
     RECT  110.916 28.541 111.042 29.029 ;
     RECT  78.984 29.029 79.11 29.057 ;
     RECT  76.752 29.029 76.842 29.062 ;
     RECT  44.784 28.097 47.898 29.069 ;
     RECT  50.436 28.829 50.454 29.069 ;
     RECT  58.464 28.493 59.058 29.069 ;
     RECT  64.476 28.097 64.494 29.069 ;
     RECT  71.352 28.637 71.37 29.069 ;
     RECT  85.716 29.021 85.734 29.069 ;
     RECT  91.368 28.493 92.646 29.069 ;
     RECT  97.308 28.253 97.326 29.069 ;
     RECT  98.172 27.941 98.19 29.069 ;
     RECT  100.188 28.493 100.71 29.069 ;
     RECT  114.912 28.541 114.93 29.069 ;
     RECT  116.784 28.877 116.802 29.069 ;
     RECT  120.528 28.541 120.546 29.069 ;
     RECT  122.724 27.869 122.742 29.069 ;
     RECT  52.524 28.493 53.226 29.117 ;
     RECT  91.368 29.069 92.034 29.117 ;
     RECT  47.664 29.069 47.898 29.165 ;
     RECT  48.78 28.541 49.338 29.165 ;
     RECT  128.808 28.493 128.826 29.357 ;
     RECT  44.784 29.069 46.062 29.645 ;
     RECT  48.78 29.165 48.798 29.645 ;
     RECT  80.028 29.029 80.658 29.645 ;
     RECT  90.504 28.541 90.522 29.645 ;
     RECT  92.016 29.117 92.034 29.645 ;
     RECT  110.772 29.029 111.042 29.645 ;
     RECT  100.692 29.069 100.71 29.659 ;
     RECT  45.324 29.645 46.062 29.693 ;
     RECT  125.1 27.941 125.154 29.693 ;
     RECT  100.692 29.659 101.286 29.837 ;
     RECT  76.788 29.062 76.842 29.981 ;
     RECT  88.704 28.493 88.722 29.981 ;
     RECT  112.824 29.021 112.842 30.029 ;
     RECT  129.672 28.205 129.726 30.029 ;
     RECT  81.288 29.899 81.306 30.077 ;
     RECT  102.24 29.899 102.258 30.077 ;
     RECT  45.324 29.693 45.342 30.125 ;
     RECT  47.664 29.165 47.682 30.125 ;
     RECT  53.208 29.117 53.226 30.125 ;
     RECT  76.788 29.981 76.806 30.125 ;
     RECT  78.984 29.057 79.002 30.125 ;
     RECT  95.58 27.941 95.598 30.125 ;
     RECT  100.692 29.837 100.71 30.125 ;
     RECT  125.1 29.693 125.118 30.125 ;
     RECT  129.672 30.029 129.69 30.125 ;
     RECT  127.116 30.043 127.134 30.173 ;
    LAYER M4 ;
     RECT  0.097 14.592 0.137 15.624 ;
     RECT  0.137 14.688 2.408 15.624 ;
     RECT  2.408 2.148 2.512 28.092 ;
     RECT  2.512 2.418 2.704 27.822 ;
     RECT  2.704 14.688 5.108 15.624 ;
     RECT  5.108 2.148 5.212 28.092 ;
     RECT  5.212 2.418 5.404 27.822 ;
     RECT  5.404 14.688 7.808 15.624 ;
     RECT  7.808 2.148 7.912 28.092 ;
     RECT  7.912 2.418 8.104 27.822 ;
     RECT  8.104 14.688 10.508 14.712 ;
     RECT  10.508 2.148 10.612 28.092 ;
     RECT  10.612 2.418 10.804 27.822 ;
     RECT  10.804 14.688 13.208 14.712 ;
     RECT  13.208 2.148 13.312 28.092 ;
     RECT  13.312 2.418 13.504 27.822 ;
     RECT  13.504 14.688 15.908 14.712 ;
     RECT  15.908 2.148 16.012 28.092 ;
     RECT  16.012 2.418 16.204 27.822 ;
     RECT  16.204 14.688 18.608 14.712 ;
     RECT  18.608 2.148 18.712 28.092 ;
     RECT  18.712 2.418 18.904 27.822 ;
     RECT  18.904 14.688 21.308 14.712 ;
     RECT  21.308 2.148 21.412 28.092 ;
     RECT  21.412 2.418 21.604 27.822 ;
     RECT  21.604 14.688 24.008 14.712 ;
     RECT  24.008 2.148 24.112 28.092 ;
     RECT  24.112 2.418 24.304 27.822 ;
     RECT  24.304 14.688 26.708 14.712 ;
     RECT  26.708 2.148 26.812 28.092 ;
     RECT  26.812 2.418 27.004 27.822 ;
     RECT  27.004 14.688 29.408 14.712 ;
     RECT  29.408 2.148 29.512 28.092 ;
     RECT  29.512 2.418 29.704 27.822 ;
     RECT  29.704 14.688 32.108 14.712 ;
     RECT  32.108 2.148 32.212 28.092 ;
     RECT  32.212 2.418 32.404 27.822 ;
     RECT  32.404 14.688 34.808 14.712 ;
     RECT  34.808 2.148 34.912 28.092 ;
     RECT  34.912 2.418 35.104 27.822 ;
     RECT  35.104 14.688 37.508 14.712 ;
     RECT  37.508 2.148 37.612 28.092 ;
     RECT  37.612 2.418 37.804 27.822 ;
     RECT  37.804 14.688 40.208 14.712 ;
     RECT  40.208 2.148 40.312 28.092 ;
     RECT  40.312 2.418 40.504 27.822 ;
     RECT  40.504 14.688 42.908 14.712 ;
     RECT  42.757 25.248 42.908 25.272 ;
     RECT  42.757 30.048 42.949 30.072 ;
     RECT  42.908 2.148 43.012 28.092 ;
     RECT  42.949 30.048 43.139 30.12 ;
     RECT  43.012 2.418 43.204 27.822 ;
     RECT  43.139 30.096 43.331 30.12 ;
     RECT  44.773 29.616 45.133 29.64 ;
     RECT  45.133 29.136 45.313 29.64 ;
     RECT  45.313 29.136 45.565 30.12 ;
     RECT  43.204 14.688 45.608 14.712 ;
     RECT  44.341 23.568 45.608 23.592 ;
     RECT  43.204 24.72 45.608 25.272 ;
     RECT  45.565 29.088 45.635 30.12 ;
     RECT  45.608 2.148 45.712 28.092 ;
     RECT  45.712 2.418 45.904 27.912 ;
     RECT  45.635 29.088 46.211 29.688 ;
     RECT  45.904 27.36 46.355 27.912 ;
     RECT  46.355 27.888 46.505 27.912 ;
     RECT  46.565 29.04 46.68 29.064 ;
     RECT  45.904 23.232 47.113 25.272 ;
     RECT  47.113 22.752 47.293 25.272 ;
     RECT  47.317 30.096 47.693 30.12 ;
     RECT  46.68 28.464 47.801 29.064 ;
     RECT  45.904 14.688 48.308 14.712 ;
     RECT  47.293 22.032 48.308 25.272 ;
     RECT  48.013 26.736 48.308 26.76 ;
     RECT  48.308 2.148 48.412 28.092 ;
     RECT  48.412 2.418 48.604 28.092 ;
     RECT  47.869 29.088 48.997 29.64 ;
     RECT  48.604 27.888 49.141 28.092 ;
     RECT  48.997 29.088 49.141 30.072 ;
     RECT  49.141 27.888 49.283 30.072 ;
     RECT  49.283 27.888 49.457 29.16 ;
     RECT  49.457 29.136 49.475 29.16 ;
     RECT  49.457 27.888 49.619 27.912 ;
     RECT  48.604 23.568 49.813 23.592 ;
     RECT  49.717 27.504 49.861 27.672 ;
     RECT  49.861 27.36 50.129 27.672 ;
     RECT  48.604 24.624 50.293 25.464 ;
     RECT  50.425 29.04 50.509 29.064 ;
     RECT  50.293 24.624 50.581 26.184 ;
     RECT  50.129 27.312 50.581 27.672 ;
     RECT  50.581 24.624 50.725 27.672 ;
     RECT  50.725 24.624 50.969 28.824 ;
     RECT  48.604 14.688 51.008 14.712 ;
     RECT  48.604 22.032 51.008 22.056 ;
     RECT  49.813 23.328 51.008 23.592 ;
     RECT  50.969 24.624 51.008 28.536 ;
     RECT  51.008 2.148 51.112 28.536 ;
     RECT  50.821 30.048 51.203 30.072 ;
     RECT  51.112 2.418 51.304 28.536 ;
     RECT  51.304 27.936 51.581 28.536 ;
     RECT  51.304 21.648 51.635 21.672 ;
     RECT  51.304 23.568 52.453 26.088 ;
     RECT  52.453 23.568 52.513 26.232 ;
     RECT  52.513 29.088 52.787 29.112 ;
     RECT  52.513 23.568 53.053 26.712 ;
     RECT  51.581 27.936 53.053 27.96 ;
     RECT  53.053 23.568 53.077 27.96 ;
     RECT  53.153 30.096 53.237 30.12 ;
     RECT  53.077 23.376 53.585 27.96 ;
     RECT  53.509 22.032 53.593 22.056 ;
     RECT  51.304 14.688 53.708 14.712 ;
     RECT  53.593 21.696 53.708 22.056 ;
     RECT  53.585 23.376 53.708 28.488 ;
     RECT  53.708 2.148 53.812 28.488 ;
     RECT  53.812 2.418 54.004 28.488 ;
     RECT  54.004 21.696 54.179 28.488 ;
     RECT  54.179 21.696 54.227 27.48 ;
     RECT  53.317 30.048 54.323 30.072 ;
     RECT  54.227 21.696 54.461 27.144 ;
     RECT  54.461 21.696 54.467 26.184 ;
     RECT  54.325 29.952 54.467 29.976 ;
     RECT  54.901 28.512 55.213 28.536 ;
     RECT  54.467 21.696 55.237 25.944 ;
     RECT  55.213 27.36 55.289 28.536 ;
     RECT  55.289 27.36 55.331 28.248 ;
     RECT  55.237 21.648 55.477 25.944 ;
     RECT  55.477 21.648 55.565 26.232 ;
     RECT  54.004 14.688 56.408 14.712 ;
     RECT  55.565 21.648 56.408 26.952 ;
     RECT  55.331 28.224 56.408 28.248 ;
     RECT  56.408 2.148 56.485 28.248 ;
     RECT  56.485 2.148 56.512 28.824 ;
     RECT  56.512 2.418 56.585 28.824 ;
     RECT  56.585 2.418 56.704 28.584 ;
     RECT  56.704 22.032 56.945 28.584 ;
     RECT  56.945 22.032 57.457 28.488 ;
     RECT  57.457 28.464 57.881 28.488 ;
     RECT  58.357 28.512 58.549 29.064 ;
     RECT  57.349 30.048 58.549 30.072 ;
     RECT  56.704 14.688 59.108 14.712 ;
     RECT  57.457 22.032 59.108 27.48 ;
     RECT  58.549 28.512 59.108 30.072 ;
     RECT  59.108 2.148 59.212 30.072 ;
     RECT  59.212 2.418 59.404 27.822 ;
     RECT  59.404 21.36 59.825 27.432 ;
     RECT  59.825 21.648 59.861 27.432 ;
     RECT  59.212 29.04 60.419 30.072 ;
     RECT  60.419 29.04 60.661 29.064 ;
     RECT  60.661 28.944 60.947 29.064 ;
     RECT  59.861 22.56 60.973 27.432 ;
     RECT  61.237 28.512 61.517 28.536 ;
     RECT  60.419 30.048 61.573 30.072 ;
     RECT  59.404 3.648 61.808 3.672 ;
     RECT  59.404 14.688 61.808 14.712 ;
     RECT  59.404 18.432 61.808 18.456 ;
     RECT  60.973 22.032 61.808 27.432 ;
     RECT  61.808 2.148 61.912 28.092 ;
     RECT  61.912 2.418 62.104 28.056 ;
     RECT  62.104 21.792 62.597 28.056 ;
     RECT  61.573 29.616 62.819 30.072 ;
     RECT  62.819 29.616 62.963 29.64 ;
     RECT  62.597 27.936 62.965 28.056 ;
     RECT  62.104 18.432 63.137 18.84 ;
     RECT  62.965 27.936 63.137 28.488 ;
     RECT  63.137 27.936 63.299 28.248 ;
     RECT  62.597 21.792 63.781 26.856 ;
     RECT  64.405 29.04 64.505 29.064 ;
     RECT  62.104 3.648 64.508 3.672 ;
     RECT  62.104 14.688 64.508 14.712 ;
     RECT  63.137 18.432 64.508 18.456 ;
     RECT  63.781 21.792 64.508 27.672 ;
     RECT  64.508 2.148 64.612 28.2 ;
     RECT  63.829 30.048 64.693 30.072 ;
     RECT  64.612 2.418 64.804 28.2 ;
     RECT  64.804 18.432 64.931 18.792 ;
     RECT  64.693 29.952 64.979 30.072 ;
     RECT  64.804 24.624 65.027 27 ;
     RECT  64.804 28.176 65.075 28.2 ;
     RECT  64.979 29.952 65.123 29.976 ;
     RECT  64.804 21.792 66.085 23.592 ;
     RECT  66.085 21.504 66.092 23.592 ;
     RECT  65.027 24.624 66.092 26.904 ;
     RECT  66.092 21.504 66.325 26.904 ;
     RECT  66.133 30.048 66.901 30.072 ;
     RECT  64.804 3.648 67.208 3.672 ;
     RECT  64.804 14.688 67.208 14.712 ;
     RECT  64.931 18.432 67.208 18.456 ;
     RECT  66.325 21.504 67.208 27 ;
     RECT  67.208 2.148 67.312 28.092 ;
     RECT  67.312 2.418 67.504 28.092 ;
     RECT  67.504 21.504 67.565 27.384 ;
     RECT  66.901 29.952 67.667 30.072 ;
     RECT  67.667 30.048 67.715 30.072 ;
     RECT  67.565 22.128 68.257 27.384 ;
     RECT  68.257 22.128 68.321 26.904 ;
     RECT  67.861 28.512 69.635 28.536 ;
     RECT  69.541 30.048 69.685 30.072 ;
     RECT  68.321 22.176 69.781 26.904 ;
     RECT  69.781 22.176 69.901 27.384 ;
     RECT  67.504 3.648 69.908 3.672 ;
     RECT  69.145 13.392 69.908 13.416 ;
     RECT  67.504 14.688 69.908 14.712 ;
     RECT  67.504 18.432 69.908 18.456 ;
     RECT  69.901 22.176 69.908 28.092 ;
     RECT  69.685 30 69.923 30.072 ;
     RECT  69.908 2.148 70.012 28.092 ;
     RECT  69.923 30 70.165 30.024 ;
     RECT  70.012 2.418 70.204 28.092 ;
     RECT  70.165 29.856 70.309 30.024 ;
     RECT  70.204 21.648 70.94 28.092 ;
     RECT  70.309 29.76 71.027 30.024 ;
     RECT  70.94 21.648 71.029 28.536 ;
     RECT  71.029 21.648 71.165 28.632 ;
     RECT  71.165 21.648 71.221 27.672 ;
     RECT  71.221 21.168 71.237 27.672 ;
     RECT  71.297 29.04 71.381 29.064 ;
     RECT  70.204 3.648 72.608 3.672 ;
     RECT  70.204 13.392 72.608 13.416 ;
     RECT  70.204 14.688 72.608 14.712 ;
     RECT  70.204 18.432 72.608 18.456 ;
     RECT  71.237 21.168 72.608 27.48 ;
     RECT  72.608 2.148 72.613 28.092 ;
     RECT  72.613 2.148 72.712 28.248 ;
     RECT  72.712 2.418 72.904 28.248 ;
     RECT  72.904 21.168 73.043 28.248 ;
     RECT  73.043 21.168 73.139 28.2 ;
     RECT  72.085 30.048 73.237 30.072 ;
     RECT  73.237 29.952 73.523 30.072 ;
     RECT  73.139 21.168 73.657 27.96 ;
     RECT  73.657 27.936 74.045 27.96 ;
     RECT  73.523 30.048 74.533 30.072 ;
     RECT  74.533 29.952 74.675 30.072 ;
     RECT  73.657 21.168 75.085 26.856 ;
     RECT  74.675 30.048 75.251 30.072 ;
     RECT  75.085 21.168 75.265 27.48 ;
     RECT  74.773 28.512 75.265 28.536 ;
     RECT  72.904 3.648 75.308 3.672 ;
     RECT  72.904 13.392 75.308 13.416 ;
     RECT  72.904 14.688 75.308 14.712 ;
     RECT  72.904 18.432 75.308 18.456 ;
     RECT  75.265 21.168 75.308 28.536 ;
     RECT  75.308 2.148 75.412 28.536 ;
     RECT  75.412 2.418 75.604 28.536 ;
     RECT  75.604 21.168 75.637 28.536 ;
     RECT  75.637 21.168 75.731 29.064 ;
     RECT  75.731 29.04 75.779 29.064 ;
     RECT  75.731 21.168 75.827 27.96 ;
     RECT  75.827 21.168 75.875 27.576 ;
     RECT  75.875 21.168 75.923 27.192 ;
     RECT  76.213 30.048 76.357 30.072 ;
     RECT  76.357 29.952 76.645 30.072 ;
     RECT  76.645 29.952 76.789 30.12 ;
     RECT  76.789 29.04 76.817 30.12 ;
     RECT  76.817 29.04 76.931 30.072 ;
     RECT  75.923 21.168 77.137 26.904 ;
     RECT  76.931 29.952 77.171 30.072 ;
     RECT  77.137 21.168 77.605 27.384 ;
     RECT  77.605 21.168 77.749 27.96 ;
     RECT  75.604 3.648 78.008 3.672 ;
     RECT  75.604 13.392 78.008 13.416 ;
     RECT  75.604 14.688 78.008 14.712 ;
     RECT  75.604 18.432 78.008 18.456 ;
     RECT  77.749 21.168 78.008 28.248 ;
     RECT  78.008 2.148 78.112 28.248 ;
     RECT  77.171 30.048 78.229 30.072 ;
     RECT  78.112 2.418 78.304 27.822 ;
     RECT  78.229 29.952 78.515 30.072 ;
     RECT  78.304 21.168 78.611 26.904 ;
     RECT  78.517 29.04 78.659 29.064 ;
     RECT  78.515 30.048 78.929 30.072 ;
     RECT  78.929 30.048 79.013 30.12 ;
     RECT  78.611 21.168 79.649 26.856 ;
     RECT  79.013 30.048 79.957 30.072 ;
     RECT  79.649 21.168 80.117 26.904 ;
     RECT  79.957 29.616 80.389 30.072 ;
     RECT  78.304 3.648 80.708 3.672 ;
     RECT  78.304 13.344 80.708 13.416 ;
     RECT  78.304 14.688 80.708 14.712 ;
     RECT  78.304 18.432 80.708 18.456 ;
     RECT  80.117 21.168 80.708 27.432 ;
     RECT  80.389 29.52 80.723 30.072 ;
     RECT  80.708 2.148 80.812 28.092 ;
     RECT  80.812 2.418 81.004 28.092 ;
     RECT  81.004 21.168 81.101 27.384 ;
     RECT  80.723 29.904 81.317 30.072 ;
     RECT  81.317 29.904 81.347 30.024 ;
     RECT  81.347 30 81.395 30.024 ;
     RECT  81.541 28.512 81.749 28.536 ;
     RECT  81.101 21.408 81.973 27.384 ;
     RECT  81.973 21.408 82.067 26.904 ;
     RECT  82.067 21.408 82.22 26.856 ;
     RECT  82.22 21.312 82.307 26.856 ;
     RECT  81.004 13.344 83.077 13.416 ;
     RECT  82.307 21.408 83.173 26.856 ;
     RECT  83.173 21.408 83.269 27 ;
     RECT  81.004 3.648 83.408 3.672 ;
     RECT  83.077 12.768 83.408 13.416 ;
     RECT  81.004 14.688 83.408 14.712 ;
     RECT  81.004 18.432 83.408 18.456 ;
     RECT  83.269 21.408 83.408 27.48 ;
     RECT  83.257 28.512 83.408 28.536 ;
     RECT  83.408 2.148 83.512 28.536 ;
     RECT  83.512 2.418 83.704 28.536 ;
     RECT  83.704 28.176 83.845 28.536 ;
     RECT  83.845 28.176 83.891 29.064 ;
     RECT  83.891 28.944 83.987 29.064 ;
     RECT  83.704 14.688 84.083 14.712 ;
     RECT  83.987 28.944 84.125 28.968 ;
     RECT  83.704 18.432 85.489 18.456 ;
     RECT  85.573 29.04 85.717 29.064 ;
     RECT  85.717 28.992 85.853 29.064 ;
     RECT  83.704 3.648 86.108 3.672 ;
     RECT  83.704 12.768 86.108 13.416 ;
     RECT  85.489 18.432 86.108 18.84 ;
     RECT  83.704 21.216 86.108 26.904 ;
     RECT  82.981 30.048 86.149 30.072 ;
     RECT  86.108 2.148 86.212 28.2 ;
     RECT  86.212 2.418 86.404 28.2 ;
     RECT  86.149 29.808 86.627 30.072 ;
     RECT  86.404 21.168 86.723 28.2 ;
     RECT  86.627 30.048 87.011 30.072 ;
     RECT  86.404 3.648 87.613 3.672 ;
     RECT  87.613 2.88 87.793 3.672 ;
     RECT  87.781 1.104 87.901 1.128 ;
     RECT  87.757 0.096 88.115 0.12 ;
     RECT  86.723 21.168 88.309 27.384 ;
     RECT  87.901 1.104 88.513 1.752 ;
     RECT  87.793 2.784 88.513 3.672 ;
     RECT  88.513 1.104 88.547 3.672 ;
     RECT  88.453 30.048 88.597 30.072 ;
     RECT  88.597 29.952 88.693 30.072 ;
     RECT  88.693 29.904 88.787 30.072 ;
     RECT  88.547 1.728 88.808 3.672 ;
     RECT  86.404 12.768 88.808 13.416 ;
     RECT  86.404 18.432 88.808 18.456 ;
     RECT  88.309 21.168 88.808 27.912 ;
     RECT  88.787 29.904 88.931 29.928 ;
     RECT  88.808 1.728 89.029 28.092 ;
     RECT  89.029 1.728 89.104 28.488 ;
     RECT  89.104 1.728 89.165 1.848 ;
     RECT  89.104 21.168 89.452 26.856 ;
     RECT  89.449 0.096 89.555 0.12 ;
     RECT  89.629 0.576 89.713 0.6 ;
     RECT  89.452 21.168 89.777 25.608 ;
     RECT  89.452 26.688 89.813 26.856 ;
     RECT  89.165 1.728 89.921 1.752 ;
     RECT  89.777 23.568 90.209 25.608 ;
     RECT  89.104 27.888 90.313 28.488 ;
     RECT  89.104 3.648 90.349 3.672 ;
     RECT  89.104 18.432 90.467 18.456 ;
     RECT  90.349 3.648 90.637 3.72 ;
     RECT  89.813 26.832 90.709 26.856 ;
     RECT  90.313 27.888 90.709 28.536 ;
     RECT  90.709 26.832 90.961 28.536 ;
     RECT  90.901 0.096 91.037 0.12 ;
     RECT  90.637 3.648 91.141 3.864 ;
     RECT  89.777 21.168 91.141 22.296 ;
     RECT  90.961 26.736 91.141 28.536 ;
     RECT  91.141 3.648 91.213 3.912 ;
     RECT  90.209 23.568 91.285 25.32 ;
     RECT  91.141 26.304 91.285 28.536 ;
     RECT  91.213 3.408 91.292 3.96 ;
     RECT  91.292 3.408 91.333 4.008 ;
     RECT  91.285 23.568 91.357 28.536 ;
     RECT  90.277 29.616 91.357 29.64 ;
     RECT  91.357 23.568 91.381 29.64 ;
     RECT  91.333 3.024 91.429 4.008 ;
     RECT  91.381 23.568 91.475 30.072 ;
     RECT  91.045 1.728 91.508 1.752 ;
     RECT  91.429 2.832 91.508 4.008 ;
     RECT  89.104 12.768 91.508 13.416 ;
     RECT  91.141 21.168 91.508 22.344 ;
     RECT  91.475 23.568 91.508 28.488 ;
     RECT  91.475 29.616 91.763 30.072 ;
     RECT  91.508 1.728 91.804 28.488 ;
     RECT  91.763 29.616 92.045 29.64 ;
     RECT  91.804 21.168 92.081 26.856 ;
     RECT  91.804 18.816 92.153 18.84 ;
     RECT  91.804 27.936 92.333 28.488 ;
     RECT  92.437 29.04 92.657 29.064 ;
     RECT  92.333 27.936 92.915 28.056 ;
     RECT  92.081 22.176 93.049 26.856 ;
     RECT  91.804 1.728 93.053 3.672 ;
     RECT  93.013 0.528 93.347 0.552 ;
     RECT  93.517 0.576 93.635 0.6 ;
     RECT  93.013 29.952 93.685 30.072 ;
     RECT  92.081 21.168 93.733 21.192 ;
     RECT  93.049 22.176 93.733 27.384 ;
     RECT  93.685 29.04 93.827 30.072 ;
     RECT  93.733 21.168 94.021 27.384 ;
     RECT  93.827 29.952 94.067 30.072 ;
     RECT  93.053 1.728 94.124 2.232 ;
     RECT  94.124 1.104 94.208 2.232 ;
     RECT  93.053 3.648 94.208 3.672 ;
     RECT  91.804 12.768 94.208 13.416 ;
     RECT  94.021 21.168 94.208 28.248 ;
     RECT  94.208 1.104 94.211 28.248 ;
     RECT  94.211 1.728 94.504 28.2 ;
     RECT  94.504 1.728 94.601 1.992 ;
     RECT  94.601 1.728 94.637 1.896 ;
     RECT  94.504 3.024 94.637 3.672 ;
     RECT  94.504 21.168 94.643 28.2 ;
     RECT  94.643 28.176 94.691 28.2 ;
     RECT  94.597 0.144 94.739 0.168 ;
     RECT  94.067 29.952 94.835 29.976 ;
     RECT  94.637 3.648 95.605 3.672 ;
     RECT  95.461 30.048 95.609 30.12 ;
     RECT  95.605 2.928 95.641 3.672 ;
     RECT  94.643 21.168 95.644 27.144 ;
     RECT  94.637 1.728 95.749 1.848 ;
     RECT  95.641 2.832 95.749 3.672 ;
     RECT  95.609 30.048 96.613 30.072 ;
     RECT  96.613 29.952 96.803 30.072 ;
     RECT  96.325 28.512 96.901 28.536 ;
     RECT  95.749 1.728 96.908 3.672 ;
     RECT  94.504 12.768 96.908 13.416 ;
     RECT  95.644 21.168 96.908 26.904 ;
     RECT  96.901 28.224 96.908 28.536 ;
     RECT  96.908 1.728 97.045 28.536 ;
     RECT  97.045 1.728 97.204 29.064 ;
     RECT  97.204 21.168 97.301 29.064 ;
     RECT  97.301 28.992 97.475 29.064 ;
     RECT  97.204 1.728 97.481 3.672 ;
     RECT  97.475 29.04 98.101 29.064 ;
     RECT  96.803 30.048 98.101 30.072 ;
     RECT  98.053 0.096 98.201 0.12 ;
     RECT  98.101 29.04 98.435 30.072 ;
     RECT  97.301 21.168 99.089 27.384 ;
     RECT  97.481 1.728 99.205 1.8 ;
     RECT  97.481 2.784 99.205 3.672 ;
     RECT  99.205 1.728 99.608 3.672 ;
     RECT  97.204 12.768 99.608 13.416 ;
     RECT  99.089 21.168 99.608 27.432 ;
     RECT  99.349 28.464 99.608 28.488 ;
     RECT  99.608 1.728 99.712 28.488 ;
     RECT  98.435 29.952 99.781 30.072 ;
     RECT  99.712 1.728 99.904 27.822 ;
     RECT  99.781 29.856 99.925 30.072 ;
     RECT  99.781 0.528 100.001 0.552 ;
     RECT  99.925 29.76 100.177 30.072 ;
     RECT  100.177 29.04 100.211 30.072 ;
     RECT  99.904 1.728 100.217 1.8 ;
     RECT  100.211 29.04 100.261 29.064 ;
     RECT  100.501 30.096 100.721 30.12 ;
     RECT  99.904 21.168 100.969 27.384 ;
     RECT  99.904 2.88 101.401 3.672 ;
     RECT  101.213 29.568 101.411 29.832 ;
     RECT  100.217 1.728 101.509 1.752 ;
     RECT  101.401 2.784 101.509 3.672 ;
     RECT  101.509 1.728 102.133 3.672 ;
     RECT  102.133 0.144 102.181 0.168 ;
     RECT  102.133 29.904 102.229 30.024 ;
     RECT  102.133 2.016 102.308 3.672 ;
     RECT  99.904 12.768 102.308 13.416 ;
     RECT  100.969 20.976 102.308 27.384 ;
     RECT  102.308 2.016 102.517 28.092 ;
     RECT  102.181 0.144 102.563 0.264 ;
     RECT  102.517 2.016 102.604 28.2 ;
     RECT  102.563 0.144 102.803 0.168 ;
     RECT  102.604 20.88 102.803 28.2 ;
     RECT  102.803 20.88 102.917 27.384 ;
     RECT  102.229 29.904 102.949 30.072 ;
     RECT  102.949 29.856 103.139 30.072 ;
     RECT  102.604 2.016 103.237 3.672 ;
     RECT  102.917 21.024 103.277 27.384 ;
     RECT  103.277 21.024 103.925 26.904 ;
     RECT  103.237 1.728 104.329 3.672 ;
     RECT  103.139 29.904 104.869 30.024 ;
     RECT  104.329 1.776 105.008 3.672 ;
     RECT  102.604 12.768 105.008 13.416 ;
     RECT  103.925 21.168 105.008 26.904 ;
     RECT  104.785 28.176 105.008 28.2 ;
     RECT  104.869 29.904 105.011 30.072 ;
     RECT  105.008 1.776 105.013 28.2 ;
     RECT  105.253 0.336 105.301 0.36 ;
     RECT  105.013 1.968 105.301 28.2 ;
     RECT  105.301 1.968 105.304 28.296 ;
     RECT  105.301 0.24 105.443 0.36 ;
     RECT  105.011 29.904 105.443 30.024 ;
     RECT  105.304 21.936 105.491 28.296 ;
     RECT  105.304 1.968 106.261 3.672 ;
     RECT  106.261 1.824 106.405 3.672 ;
     RECT  106.405 1.776 106.409 3.672 ;
     RECT  106.409 1.776 106.441 2.28 ;
     RECT  105.491 21.936 106.513 28.008 ;
     RECT  106.513 21.504 106.613 28.008 ;
     RECT  106.613 21.408 106.697 28.008 ;
     RECT  106.697 21.456 106.837 28.008 ;
     RECT  106.837 21.456 107.171 28.536 ;
     RECT  106.441 1.728 107.449 2.28 ;
     RECT  106.409 3.648 107.449 3.672 ;
     RECT  107.449 1.728 107.641 3.672 ;
     RECT  107.641 1.776 107.708 3.672 ;
     RECT  105.304 12.768 107.708 13.416 ;
     RECT  106.765 18.816 107.708 18.84 ;
     RECT  107.171 21.456 107.708 28.092 ;
     RECT  107.708 1.776 107.812 28.092 ;
     RECT  107.509 30.048 107.989 30.072 ;
     RECT  107.812 1.776 108.004 27.822 ;
     RECT  108.004 21.456 108.209 27.48 ;
     RECT  107.989 30 108.277 30.072 ;
     RECT  108.209 21.504 108.371 27.48 ;
     RECT  108.277 29.904 108.419 30.072 ;
     RECT  108.004 1.776 108.997 3.672 ;
     RECT  109.573 29.04 109.715 29.064 ;
     RECT  108.419 30.048 110.101 30.072 ;
     RECT  108.371 21.504 110.365 27.384 ;
     RECT  108.997 1.728 110.408 3.672 ;
     RECT  108.004 12.768 110.408 13.416 ;
     RECT  110.365 21.504 110.408 27.48 ;
     RECT  110.197 0.144 110.483 0.168 ;
     RECT  110.408 1.728 110.704 28.092 ;
     RECT  110.704 21.504 110.819 27.48 ;
     RECT  110.101 29.616 110.867 30.072 ;
     RECT  110.581 0.096 110.873 0.12 ;
     RECT  110.867 29.616 110.917 29.928 ;
     RECT  110.917 28.512 111.059 29.928 ;
     RECT  110.704 1.728 111.203 3.672 ;
     RECT  111.203 1.728 111.521 1.848 ;
     RECT  110.819 21.504 111.797 26.904 ;
     RECT  111.059 29.904 111.877 29.928 ;
     RECT  111.797 21.504 111.881 27.384 ;
     RECT  111.881 21.504 111.949 27.144 ;
     RECT  111.877 18.816 112.061 18.84 ;
     RECT  111.949 21.168 112.061 27.144 ;
     RECT  111.203 2.88 112.237 3.672 ;
     RECT  111.059 28.512 112.549 28.536 ;
     RECT  111.877 29.904 112.549 30.024 ;
     RECT  112.549 28.512 112.597 30.024 ;
     RECT  111.521 1.728 112.733 1.8 ;
     RECT  112.237 2.784 112.733 3.672 ;
     RECT  112.597 28.512 113.075 30.072 ;
     RECT  112.733 1.728 113.108 3.672 ;
     RECT  110.704 12.768 113.108 13.416 ;
     RECT  112.061 21.504 113.108 27.144 ;
     RECT  113.075 28.512 113.108 30.024 ;
     RECT  113.108 1.728 113.315 30.024 ;
     RECT  113.315 1.728 113.404 28.2 ;
     RECT  113.404 28.176 113.555 28.2 ;
     RECT  113.315 29.904 113.651 30.024 ;
     RECT  113.651 30 113.747 30.024 ;
     RECT  113.404 21.504 114.389 26.856 ;
     RECT  114.389 21.504 114.517 26.904 ;
     RECT  114.901 29.04 114.985 29.064 ;
     RECT  115.045 28.512 115.157 28.536 ;
     RECT  114.517 21.408 115.513 26.904 ;
     RECT  115.513 21.408 115.669 27.384 ;
     RECT  113.404 1.728 115.808 3.672 ;
     RECT  113.404 12.768 115.808 13.416 ;
     RECT  115.669 21.408 115.808 28.296 ;
     RECT  116.053 0.336 116.101 0.36 ;
     RECT  115.765 29.76 116.101 29.88 ;
     RECT  115.808 1.728 116.104 28.296 ;
     RECT  116.101 0.24 116.243 0.36 ;
     RECT  116.104 21.408 116.485 28.296 ;
     RECT  116.101 29.76 116.485 30.024 ;
     RECT  116.485 21.408 116.675 30.024 ;
     RECT  116.675 21.408 116.741 29.064 ;
     RECT  116.741 29.04 116.813 29.064 ;
     RECT  116.741 21.408 116.849 27.96 ;
     RECT  116.849 21.408 116.867 27.384 ;
     RECT  116.867 21.408 118.429 26.856 ;
     RECT  116.104 1.728 118.508 3.672 ;
     RECT  116.104 12.768 118.508 13.416 ;
     RECT  118.429 21.408 118.508 27.384 ;
     RECT  118.213 28.512 118.508 28.536 ;
     RECT  118.261 0.144 118.547 0.168 ;
     RECT  118.508 1.728 118.804 28.536 ;
     RECT  118.804 28.512 118.937 28.536 ;
     RECT  118.804 21.408 119.045 27.384 ;
     RECT  119.045 25.2 119.075 27.384 ;
     RECT  117.061 30.048 119.413 30.072 ;
     RECT  119.413 29.952 119.651 30.072 ;
     RECT  119.651 29.952 119.699 29.976 ;
     RECT  119.045 21.408 120.013 24.168 ;
     RECT  119.075 25.2 120.013 26.856 ;
     RECT  120.013 21.408 120.481 26.856 ;
     RECT  119.797 27.936 120.517 27.96 ;
     RECT  119.941 29.04 120.517 29.064 ;
     RECT  120.481 21.408 120.697 26.904 ;
     RECT  120.517 27.936 120.697 29.064 ;
     RECT  118.804 12.768 120.805 13.416 ;
     RECT  120.697 21.408 120.853 29.064 ;
     RECT  120.853 21.408 120.997 30.024 ;
     RECT  120.997 21.408 121.139 30.072 ;
     RECT  118.804 1.728 121.208 3.672 ;
     RECT  120.805 12.768 121.208 14.232 ;
     RECT  121.139 21.408 121.208 28.092 ;
     RECT  121.139 29.952 121.283 30.024 ;
     RECT  121.208 1.728 121.312 28.092 ;
     RECT  121.045 0.144 121.427 0.168 ;
     RECT  121.312 1.728 121.504 27.822 ;
     RECT  121.504 12.768 121.781 14.232 ;
     RECT  121.504 1.728 121.861 1.848 ;
     RECT  121.283 30 122.101 30.024 ;
     RECT  121.781 12.768 122.285 13.656 ;
     RECT  122.101 30 122.533 30.072 ;
     RECT  122.533 29.952 122.669 30.072 ;
     RECT  122.669 29.04 122.675 30.072 ;
     RECT  122.675 29.04 122.753 29.064 ;
     RECT  121.504 21.12 122.965 27.432 ;
     RECT  123.109 0.096 123.293 0.12 ;
     RECT  122.965 21.12 123.677 27.48 ;
     RECT  123.677 21.12 123.692 27.672 ;
     RECT  123.253 28.752 123.692 28.824 ;
     RECT  121.861 1.728 123.757 1.8 ;
     RECT  121.504 2.88 123.757 3.672 ;
     RECT  122.675 30.048 123.781 30.072 ;
     RECT  123.757 1.728 123.833 3.672 ;
     RECT  123.833 1.824 123.908 3.672 ;
     RECT  122.285 12.768 123.908 13.416 ;
     RECT  123.685 18.768 123.908 18.792 ;
     RECT  123.692 21.12 123.908 28.824 ;
     RECT  123.908 1.824 124.204 28.824 ;
     RECT  124.204 1.824 124.265 3.672 ;
     RECT  124.204 21.12 124.355 27.384 ;
     RECT  124.355 21.12 124.403 27.144 ;
     RECT  124.265 1.824 124.517 1.848 ;
     RECT  124.204 28.752 124.549 28.824 ;
     RECT  123.781 29.952 124.549 30.072 ;
     RECT  124.549 28.752 124.837 30.072 ;
     RECT  124.981 1.728 125.129 1.752 ;
     RECT  124.837 28.752 125.129 30.12 ;
     RECT  125.129 28.752 125.171 29.688 ;
     RECT  125.372 0.528 125.459 0.552 ;
     RECT  125.171 28.752 125.557 29.352 ;
     RECT  124.265 2.88 125.989 3.672 ;
     RECT  124.403 21.12 125.989 27.096 ;
     RECT  125.557 28.176 125.989 29.352 ;
     RECT  125.989 2.16 126.277 3.672 ;
     RECT  126.277 1.728 126.608 3.672 ;
     RECT  124.204 12.768 126.608 13.416 ;
     RECT  125.989 21.12 126.608 29.352 ;
     RECT  126.608 1.728 126.709 29.352 ;
     RECT  126.709 0.288 126.901 0.312 ;
     RECT  126.709 1.728 126.904 29.976 ;
     RECT  126.904 21.12 126.965 24.216 ;
     RECT  126.904 25.248 126.997 29.976 ;
     RECT  126.901 0.192 127.043 0.312 ;
     RECT  126.997 25.248 127.045 30.072 ;
     RECT  127.045 25.248 127.145 30.168 ;
     RECT  126.904 6.576 127.649 6.6 ;
     RECT  127.145 25.248 127.937 29.352 ;
     RECT  126.965 21.12 128.293 23.976 ;
     RECT  127.937 26.304 128.837 29.352 ;
     RECT  126.904 1.728 129.308 3.672 ;
     RECT  126.904 12.768 129.308 13.416 ;
     RECT  128.293 21.12 129.308 24.216 ;
     RECT  127.937 25.248 129.308 25.272 ;
     RECT  128.837 26.304 129.308 28.824 ;
     RECT  129.308 1.728 129.604 28.824 ;
     RECT  129.541 30 129.701 30.12 ;
     RECT  129.604 21.6 129.737 22.056 ;
     RECT  129.701 30 129.737 30.024 ;
     RECT  129.604 1.728 129.809 3.672 ;
     RECT  129.604 26.784 129.809 28.824 ;
     RECT  129.737 21.6 130.097 21.624 ;
     RECT  129.809 3.264 130.133 3.672 ;
     RECT  129.809 26.832 130.205 28.824 ;
     RECT  129.809 1.728 130.385 2.232 ;
     RECT  130.385 1.776 130.421 2.232 ;
     RECT  130.205 27.84 130.529 28.824 ;
     RECT  130.529 27.84 130.817 28.776 ;
     RECT  130.817 28.752 130.925 28.776 ;
     RECT  129.604 24.672 131.033 25.272 ;
     RECT  130.421 1.776 131.353 1.8 ;
     RECT  131.353 1.728 131.669 1.8 ;
     RECT  131.669 1.152 131.749 1.8 ;
     RECT  131.749 1.056 131.929 1.8 ;
     RECT  131.929 1.056 132.008 2.04 ;
     RECT  130.133 3.648 132.008 3.672 ;
     RECT  129.604 12.768 132.008 13.416 ;
     RECT  131.033 25.248 132.008 25.272 ;
     RECT  130.205 26.832 132.008 26.856 ;
     RECT  132.008 1.056 132.112 28.092 ;
     RECT  132.112 1.056 132.304 27.822 ;
     RECT  132.304 1.056 132.611 1.992 ;
     RECT  133.388 0.528 133.475 0.552 ;
     RECT  132.611 1.728 133.657 1.992 ;
     RECT  133.657 1.728 133.861 2.376 ;
     RECT  132.304 3.648 133.861 3.672 ;
     RECT  133.861 1.728 134.708 3.672 ;
     RECT  132.304 12.768 134.708 13.416 ;
     RECT  132.304 26.832 134.708 26.856 ;
     RECT  134.708 1.728 134.812 28.092 ;
     RECT  134.812 1.728 135.004 27.822 ;
     RECT  135.004 1.728 135.461 2.088 ;
     RECT  135.461 1.728 135.649 1.848 ;
     RECT  135.004 3.648 136.165 3.672 ;
     RECT  135.649 1.728 136.681 1.8 ;
     RECT  136.165 2.88 136.681 3.672 ;
     RECT  136.681 1.728 136.844 3.672 ;
     RECT  136.844 1.104 136.931 3.672 ;
     RECT  136.931 1.728 137.408 3.672 ;
     RECT  135.004 12.768 137.408 13.416 ;
     RECT  135.004 26.832 137.408 26.856 ;
     RECT  137.408 1.728 137.512 28.092 ;
     RECT  137.512 1.728 137.704 27.822 ;
     RECT  137.749 0.144 137.891 0.168 ;
     RECT  137.704 1.728 138.449 3.672 ;
     RECT  138.449 1.728 138.515 2.088 ;
     RECT  138.449 3.36 139.621 3.672 ;
     RECT  139.957 0.144 140.099 0.168 ;
     RECT  138.515 1.728 140.108 1.848 ;
     RECT  139.621 2.88 140.108 3.672 ;
     RECT  137.704 12.768 140.108 13.416 ;
     RECT  137.704 26.832 140.108 26.856 ;
     RECT  140.108 1.728 140.212 28.092 ;
     RECT  140.212 1.728 140.404 27.822 ;
     RECT  142.549 0.192 142.693 0.216 ;
     RECT  140.404 1.728 142.808 3.672 ;
     RECT  140.404 12.768 142.808 13.416 ;
     RECT  140.404 26.832 142.808 26.856 ;
     RECT  142.693 0.144 142.835 0.216 ;
     RECT  142.808 1.728 142.912 28.092 ;
     RECT  142.835 0.192 142.979 0.216 ;
     RECT  142.912 1.728 143.104 27.822 ;
     RECT  143.104 26.832 143.597 26.856 ;
     RECT  143.104 1.728 143.633 3.144 ;
     RECT  143.633 1.728 144.389 2.904 ;
     RECT  144.389 1.728 144.773 2.52 ;
     RECT  144.773 1.152 144.857 2.52 ;
     RECT  144.857 1.728 145.357 2.52 ;
     RECT  145.357 1.728 145.508 2.856 ;
     RECT  143.104 12.768 145.508 13.416 ;
     RECT  145.508 1.728 145.612 28.092 ;
     RECT  145.612 1.728 145.804 27.822 ;
     RECT  145.804 1.728 147.011 2.28 ;
     RECT  147.157 2.736 147.541 3 ;
     RECT  147.011 1.728 147.644 1.752 ;
     RECT  147.644 1.104 147.731 1.752 ;
     RECT  147.731 1.728 148.208 1.752 ;
     RECT  147.541 2.736 148.208 3.048 ;
     RECT  145.804 12.768 148.208 13.416 ;
     RECT  148.208 1.728 148.312 28.092 ;
     RECT  148.312 1.728 148.504 27.822 ;
     RECT  148.021 0.144 148.643 0.264 ;
     RECT  148.643 0.24 148.691 0.264 ;
     RECT  148.504 1.728 148.691 3.192 ;
     RECT  148.691 1.728 150.908 2.904 ;
     RECT  148.504 12.768 150.908 13.416 ;
     RECT  150.908 1.728 151.012 28.092 ;
     RECT  150.757 0.144 151.043 0.168 ;
     RECT  151.012 1.728 151.204 27.822 ;
     RECT  151.141 0.192 151.331 0.312 ;
     RECT  151.204 3.312 151.331 3.336 ;
     RECT  151.331 0.192 151.427 0.216 ;
     RECT  151.204 12.768 152.345 13.416 ;
     RECT  151.204 1.728 152.437 2.28 ;
     RECT  152.437 1.728 152.725 3.096 ;
     RECT  152.725 1.728 153.493 3.144 ;
     RECT  153.493 1.728 153.608 3.336 ;
     RECT  152.345 12.768 153.608 13.368 ;
     RECT  153.608 1.728 153.712 28.092 ;
     RECT  153.493 0.144 153.779 0.168 ;
     RECT  153.712 1.728 153.904 27.822 ;
     RECT  153.904 2.88 155.045 2.904 ;
     RECT  155.941 2.976 156.037 3 ;
     RECT  156.037 2.88 156.149 3 ;
     RECT  153.904 1.728 156.308 1.896 ;
     RECT  156.149 2.88 156.308 3.096 ;
     RECT  153.904 12.768 156.308 13.368 ;
     RECT  156.308 1.728 156.412 28.092 ;
     RECT  156.412 1.728 156.604 27.822 ;
     RECT  156.604 1.728 156.629 3.096 ;
     RECT  156.325 0.144 156.755 0.168 ;
     RECT  156.629 1.728 156.845 3.048 ;
     RECT  156.845 2.88 157.621 3.048 ;
     RECT  156.845 1.728 157.868 1.8 ;
     RECT  157.621 2.88 157.868 3.24 ;
     RECT  157.868 1.728 158.773 3.24 ;
     RECT  158.773 1.728 159.008 3.336 ;
     RECT  156.604 12.768 159.008 13.368 ;
     RECT  158.821 0.144 159.061 0.168 ;
     RECT  159.008 1.728 159.112 28.092 ;
     RECT  159.112 1.728 159.304 27.822 ;
     RECT  159.061 0.144 159.365 0.552 ;
     RECT  159.365 0.144 159.491 0.168 ;
     RECT  159.304 2.832 160.265 3.192 ;
     RECT  159.304 1.728 160.316 1.8 ;
     RECT  160.265 2.832 160.316 3.096 ;
     RECT  160.316 1.728 160.403 3.096 ;
     RECT  160.403 2.88 160.589 3.096 ;
     RECT  160.403 1.728 161.629 1.8 ;
     RECT  160.589 2.88 161.629 2.952 ;
     RECT  161.557 0.144 161.699 0.168 ;
     RECT  161.629 1.728 161.708 2.952 ;
     RECT  159.304 12.768 161.708 13.368 ;
     RECT  161.708 1.728 161.812 28.092 ;
     RECT  161.812 1.728 162.004 27.822 ;
     RECT  162.004 1.728 162.641 3.144 ;
     RECT  162.641 1.728 162.707 2.904 ;
     RECT  162.004 12.768 162.713 13.368 ;
     RECT  162.707 1.728 163.669 1.848 ;
     RECT  162.707 2.88 163.669 2.904 ;
     RECT  163.669 1.728 164.293 2.904 ;
     RECT  164.293 1.728 164.408 3.048 ;
     RECT  162.713 12.768 164.408 12.792 ;
     RECT  164.408 1.728 164.512 28.092 ;
     RECT  164.293 0.144 164.579 0.168 ;
     RECT  164.512 1.728 164.704 27.822 ;
     RECT  164.704 2.88 164.729 3.096 ;
     RECT  164.704 1.728 165.089 1.8 ;
     RECT  164.729 2.928 165.587 3.096 ;
     RECT  165.587 2.976 165.685 3.096 ;
     RECT  165.685 2.976 165.773 3.144 ;
     RECT  165.089 1.728 166.261 1.752 ;
     RECT  166.261 1.728 166.373 1.8 ;
     RECT  165.773 2.976 166.633 3.096 ;
     RECT  166.373 1.728 166.796 1.896 ;
     RECT  166.633 2.88 166.796 3.096 ;
     RECT  166.796 1.728 166.981 3.096 ;
     RECT  166.981 1.728 167.108 3.384 ;
     RECT  164.704 12.768 167.108 12.792 ;
     RECT  167.108 1.728 167.212 28.092 ;
     RECT  167.212 1.728 167.404 27.822 ;
     RECT  167.269 0.336 167.413 0.36 ;
     RECT  167.413 0.336 167.557 0.456 ;
     RECT  167.557 0.144 167.603 0.456 ;
     RECT  167.603 0.144 167.699 0.168 ;
     RECT  167.404 1.728 168.389 3.144 ;
     RECT  169.009 0.48 169.081 0.504 ;
     RECT  168.389 1.728 169.081 3.528 ;
     RECT  169.081 0.48 169.369 3.528 ;
     RECT  169.369 0.48 169.808 4.488 ;
     RECT  169.808 0.48 169.861 28.092 ;
     RECT  169.861 0.096 169.912 28.092 ;
     RECT  169.912 0.096 170.104 27.822 ;
     RECT  170.104 4.464 170.291 4.68 ;
     RECT  170.291 4.464 170.309 4.584 ;
     RECT  170.104 0.096 170.345 2.28 ;
     RECT  170.345 0.192 170.381 2.28 ;
     RECT  170.309 4.56 170.453 4.584 ;
     RECT  170.381 0.48 171.059 2.28 ;
     RECT  171.059 2.256 171.277 2.28 ;
     RECT  171.277 2.256 171.361 2.904 ;
     RECT  171.361 2.256 171.491 2.28 ;
     RECT  171.059 0.48 171.635 1.128 ;
     RECT  171.635 0.48 171.701 0.984 ;
     RECT  171.701 0.096 171.785 0.984 ;
     RECT  171.785 0.48 171.923 0.984 ;
     RECT  171.923 0.48 172.067 0.504 ;
    LAYER M5 ;
     RECT  90.912 0.016 91.08 0.131 ;
     RECT  131.424 0.016 172.056 0.515 ;
     RECT  131.424 0.515 171.912 0.995 ;
     RECT  87.792 0.016 89.832 1.139 ;
     RECT  131.424 0.995 171.624 1.139 ;
     RECT  131.424 1.139 171.48 1.715 ;
     RECT  87.936 1.139 89.832 1.763 ;
     RECT  91.056 0.131 91.08 1.763 ;
     RECT  131.424 1.715 170.328 1.763 ;
     RECT  92.16 0.016 130.344 1.811 ;
     RECT  131.568 1.763 170.328 1.811 ;
     RECT  94.2 1.811 130.344 1.859 ;
     RECT  133.296 1.811 144.12 1.859 ;
     RECT  92.16 1.811 93.192 1.907 ;
     RECT  145.104 1.811 170.328 1.907 ;
     RECT  133.296 1.859 135.192 2.003 ;
     RECT  133.728 2.003 135.192 2.099 ;
     RECT  136.176 1.859 138.504 2.099 ;
     RECT  2.4 2.137 2.52 2.151 ;
     RECT  5.1 2.137 5.22 2.151 ;
     RECT  7.8 2.137 7.92 2.151 ;
     RECT  10.5 2.137 10.62 2.151 ;
     RECT  13.2 2.137 13.32 2.151 ;
     RECT  15.9 2.137 16.02 2.151 ;
     RECT  18.6 2.137 18.72 2.151 ;
     RECT  21.3 2.137 21.42 2.151 ;
     RECT  24 2.137 24.12 2.151 ;
     RECT  26.7 2.137 26.82 2.151 ;
     RECT  29.4 2.137 29.52 2.151 ;
     RECT  32.1 2.137 32.22 2.151 ;
     RECT  34.8 2.137 34.92 2.151 ;
     RECT  37.5 2.137 37.62 2.151 ;
     RECT  40.2 2.137 40.32 2.151 ;
     RECT  42.9 2.137 43.02 2.151 ;
     RECT  45.6 2.137 45.72 2.151 ;
     RECT  48.3 2.137 48.42 2.151 ;
     RECT  51 2.137 51.12 2.151 ;
     RECT  53.7 2.137 53.82 2.151 ;
     RECT  56.4 2.137 56.52 2.151 ;
     RECT  59.1 2.137 59.22 2.151 ;
     RECT  61.8 2.137 61.92 2.151 ;
     RECT  64.5 2.137 64.62 2.151 ;
     RECT  67.2 2.137 67.32 2.151 ;
     RECT  69.9 2.137 70.02 2.151 ;
     RECT  72.6 2.137 72.72 2.151 ;
     RECT  75.3 2.137 75.42 2.151 ;
     RECT  78 2.137 78.12 2.151 ;
     RECT  80.7 2.137 80.82 2.151 ;
     RECT  83.4 2.137 83.52 2.151 ;
     RECT  86.1 2.137 86.22 2.151 ;
     RECT  92.88 1.907 93.192 2.243 ;
     RECT  107.7 1.859 130.344 2.243 ;
     RECT  88.656 1.763 89.112 2.291 ;
     RECT  92.88 2.243 92.904 2.291 ;
     RECT  95.616 1.859 106.728 2.291 ;
     RECT  145.104 1.907 154.92 2.291 ;
     RECT  156.048 1.907 170.328 2.291 ;
     RECT  171.312 1.715 171.48 2.291 ;
     RECT  147.264 2.291 151.32 2.819 ;
     RECT  95.616 2.291 106.008 2.915 ;
     RECT  107.7 2.243 129.612 2.915 ;
     RECT  133.872 2.099 135.012 2.915 ;
     RECT  136.176 2.099 136.2 2.915 ;
     RECT  137.4 2.099 138.36 2.915 ;
     RECT  139.632 1.859 144.12 2.915 ;
     RECT  147.264 2.819 149.304 2.915 ;
     RECT  150.288 2.819 151.32 2.915 ;
     RECT  152.448 2.291 154.92 2.915 ;
     RECT  156.048 2.291 162.408 2.915 ;
     RECT  163.536 2.291 170.28 2.915 ;
     RECT  171.312 2.291 171.336 2.915 ;
     RECT  95.616 2.915 95.64 2.963 ;
     RECT  96.9 2.915 103.128 2.963 ;
     RECT  107.7 2.915 108.744 2.963 ;
     RECT  112.176 2.915 113.412 2.963 ;
     RECT  114.912 2.915 119.544 2.963 ;
     RECT  120.528 2.915 122.424 2.963 ;
     RECT  139.92 2.915 140.664 2.963 ;
     RECT  158.784 2.915 162.012 2.963 ;
     RECT  98.496 2.963 100.824 3.011 ;
     RECT  123.9 2.915 126.912 3.011 ;
     RECT  139.92 2.963 140.568 3.011 ;
     RECT  147.264 2.915 148.68 3.011 ;
     RECT  91.5 2.137 91.812 3.013 ;
     RECT  102.144 2.963 102.984 3.059 ;
     RECT  107.7 2.963 108.6 3.059 ;
     RECT  110.304 2.915 110.712 3.059 ;
     RECT  147.552 3.011 148.68 3.059 ;
     RECT  156.192 2.915 157.656 3.059 ;
     RECT  164.304 2.915 170.28 3.059 ;
     RECT  96.9 2.963 97.368 3.107 ;
     RECT  98.496 3.011 98.52 3.107 ;
     RECT  99.6 3.011 100.824 3.107 ;
     RECT  102.192 3.059 102.984 3.107 ;
     RECT  104.832 2.915 105.312 3.107 ;
     RECT  114.912 2.963 116.808 3.107 ;
     RECT  117.936 2.963 119.4 3.107 ;
     RECT  120.528 2.963 122.136 3.107 ;
     RECT  125.856 3.011 126.912 3.107 ;
     RECT  134.448 2.915 135.012 3.107 ;
     RECT  139.968 3.011 140.52 3.107 ;
     RECT  142.56 2.915 143.544 3.107 ;
     RECT  152.448 2.915 153.912 3.107 ;
     RECT  156.192 3.059 156.612 3.107 ;
     RECT  158.784 2.963 160.536 3.107 ;
     RECT  164.4 3.059 167.412 3.107 ;
     RECT  102.192 3.107 102.792 3.155 ;
     RECT  120.528 3.107 121.512 3.155 ;
     RECT  142.8 3.107 143.544 3.155 ;
     RECT  152.736 3.107 153.912 3.155 ;
     RECT  165.696 3.107 165.72 3.155 ;
     RECT  102.3 3.155 102.792 3.203 ;
     RECT  123.9 3.011 124.584 3.203 ;
     RECT  148.2 3.059 148.68 3.203 ;
     RECT  158.784 3.107 160.104 3.203 ;
     RECT  157.632 3.059 157.656 3.251 ;
     RECT  118.368 3.107 118.812 3.347 ;
     RECT  139.968 3.107 140.412 3.347 ;
     RECT  150.9 2.915 151.32 3.347 ;
     RECT  153.504 3.155 153.912 3.347 ;
     RECT  158.784 3.203 159.312 3.347 ;
     RECT  137.4 2.915 137.928 3.395 ;
     RECT  166.992 3.107 167.412 3.395 ;
     RECT  168.432 3.059 170.28 3.539 ;
     RECT  91.344 3.013 91.812 3.685 ;
     RECT  90.432 3.685 91.812 4.019 ;
     RECT  169.8 3.539 170.28 4.691 ;
     RECT  83.4 2.151 83.712 14.677 ;
     RECT  59.1 2.151 59.412 18.421 ;
     RECT  90.432 4.019 90.456 18.467 ;
     RECT  64.5 2.151 64.812 18.757 ;
     RECT  83.4 14.677 84.072 21.251 ;
     RECT  123.9 3.203 124.212 21.397 ;
     RECT  51 2.151 51.312 21.637 ;
     RECT  59.1 18.421 59.592 21.637 ;
     RECT  106.656 21.397 106.68 21.637 ;
     RECT  110.4 3.059 110.712 21.637 ;
     RECT  107.7 3.059 108.012 21.973 ;
     RECT  53.7 2.151 54.012 22.021 ;
     RECT  67.2 2.151 67.512 22.117 ;
     RECT  123.9 21.397 124.392 22.117 ;
     RECT  126.6 3.107 126.912 22.117 ;
     RECT  107.7 21.973 108.936 22.163 ;
     RECT  64.5 18.757 64.92 22.165 ;
     RECT  102.3 3.203 102.612 22.165 ;
     RECT  103.632 21.445 103.656 22.165 ;
     RECT  115.8 3.107 116.112 22.165 ;
     RECT  99.6 3.107 99.912 22.213 ;
     RECT  71.232 21.157 71.256 22.259 ;
     RECT  94.2 1.859 94.512 22.261 ;
     RECT  69.9 2.151 70.212 22.309 ;
     RECT  86.1 2.151 86.412 22.309 ;
     RECT  118.5 3.347 118.812 22.357 ;
     RECT  96.9 3.107 97.212 22.453 ;
     RECT  75.3 2.151 75.612 22.501 ;
     RECT  121.2 3.155 121.512 22.597 ;
     RECT  123.024 22.117 124.392 22.597 ;
     RECT  106.608 21.637 106.68 22.645 ;
     RECT  107.7 22.163 108.216 22.645 ;
     RECT  115.8 22.165 116.232 22.645 ;
     RECT  64.5 22.165 64.968 22.693 ;
     RECT  115.8 22.645 116.616 22.693 ;
     RECT  102.3 22.165 103.656 22.741 ;
     RECT  113.1 2.963 113.412 22.741 ;
     RECT  114.528 21.397 114.552 22.741 ;
     RECT  56.4 2.151 56.712 22.789 ;
     RECT  80.7 2.151 81.012 22.789 ;
     RECT  82.272 21.301 82.296 22.789 ;
     RECT  94.08 22.261 94.512 22.837 ;
     RECT  78 2.151 78.312 22.885 ;
     RECT  113.1 22.741 114.552 22.885 ;
     RECT  126.6 22.117 127.368 23.027 ;
     RECT  77.808 22.885 78.312 23.029 ;
     RECT  86.1 22.309 86.568 23.029 ;
     RECT  94.08 22.837 94.632 23.075 ;
     RECT  99.12 22.213 99.912 23.173 ;
     RECT  61.8 2.151 62.112 23.221 ;
     RECT  59.1 21.637 59.736 23.269 ;
     RECT  51 21.637 51.624 23.317 ;
     RECT  58.992 23.269 59.736 23.317 ;
     RECT  69.9 22.309 71.16 23.317 ;
     RECT  94.08 23.075 94.512 23.317 ;
     RECT  106.608 22.645 108.216 23.363 ;
     RECT  53.52 22.021 54.012 23.365 ;
     RECT  58.992 23.317 60.36 23.365 ;
     RECT  61.8 23.221 62.328 23.365 ;
     RECT  67.2 22.117 68.232 23.365 ;
     RECT  69.792 23.317 71.16 23.365 ;
     RECT  75.3 22.501 75.768 23.365 ;
     RECT  77.184 23.029 78.312 23.365 ;
     RECT  79.44 22.645 79.464 23.365 ;
     RECT  80.7 22.789 82.296 23.365 ;
     RECT  83.4 21.251 83.712 23.365 ;
     RECT  96.288 22.453 97.212 23.365 ;
     RECT  98.544 23.173 99.912 23.365 ;
     RECT  96.288 23.365 99.912 23.413 ;
     RECT  106.896 23.363 108.216 23.413 ;
     RECT  72.6 2.151 72.912 23.509 ;
     RECT  79.344 23.365 79.464 23.749 ;
     RECT  80.7 23.365 83.712 23.749 ;
     RECT  105 3.107 105.312 23.749 ;
     RECT  56.4 22.789 56.904 23.797 ;
     RECT  85.248 23.029 86.568 23.797 ;
     RECT  53.088 23.365 54.012 23.893 ;
     RECT  55.248 21.637 55.272 23.893 ;
     RECT  56.4 23.797 57.432 23.893 ;
     RECT  67.2 23.365 71.256 23.893 ;
     RECT  72.6 23.509 73.512 23.893 ;
     RECT  58.992 23.365 62.328 23.941 ;
     RECT  91.5 4.019 91.812 23.941 ;
     RECT  96.288 23.413 100.296 23.941 ;
     RECT  101.712 22.741 103.656 23.941 ;
     RECT  118.224 22.357 118.812 23.941 ;
     RECT  110.4 21.637 111.096 23.989 ;
     RECT  96.288 23.941 103.656 24.133 ;
     RECT  106.896 23.413 108.744 24.181 ;
     RECT  110.304 23.989 111.096 24.181 ;
     RECT  50.784 23.317 51.624 24.325 ;
     RECT  67.2 23.893 71.448 24.325 ;
     RECT  72.6 23.893 74.28 24.325 ;
     RECT  106.896 24.181 111.096 24.325 ;
     RECT  112.8 22.885 114.552 24.325 ;
     RECT  67.2 24.325 74.28 24.373 ;
     RECT  126.6 23.027 126.912 24.373 ;
     RECT  64.5 22.693 65.544 24.469 ;
     RECT  67.104 24.373 74.28 24.469 ;
     RECT  96.288 24.133 103.704 24.469 ;
     RECT  105 23.749 105.768 24.469 ;
     RECT  115.8 22.693 116.856 24.469 ;
     RECT  118.224 23.941 119.352 24.469 ;
     RECT  91.152 23.941 91.812 24.515 ;
     RECT  58.992 23.941 62.472 24.517 ;
     RECT  64.5 24.469 74.28 24.517 ;
     RECT  75.3 23.365 78.312 24.517 ;
     RECT  79.344 23.749 83.712 24.517 ;
     RECT  85.248 23.797 87.528 24.517 ;
     RECT  88.8 2.291 89.112 24.517 ;
     RECT  121.2 22.597 124.392 24.517 ;
     RECT  75.3 24.517 83.712 24.565 ;
     RECT  106.848 24.325 114.552 24.565 ;
     RECT  58.992 24.517 62.616 24.613 ;
     RECT  42.9 2.151 43.212 24.709 ;
     RECT  53.088 23.893 57.432 24.805 ;
     RECT  58.944 24.613 62.616 24.805 ;
     RECT  42.9 24.709 43.32 24.901 ;
     RECT  44.352 23.557 44.376 24.901 ;
     RECT  106.848 24.565 114.744 24.901 ;
     RECT  115.8 24.469 119.352 24.901 ;
     RECT  96.288 24.469 105.768 24.949 ;
     RECT  106.848 24.901 119.352 24.949 ;
     RECT  93.84 23.317 94.512 24.997 ;
     RECT  53.088 24.805 62.616 25.045 ;
     RECT  75.3 24.565 84.072 25.045 ;
     RECT  85.248 24.517 89.112 25.045 ;
     RECT  93.84 24.997 94.632 25.045 ;
     RECT  93.84 25.045 95.112 25.093 ;
     RECT  120.912 24.517 124.392 25.093 ;
     RECT  93.408 25.093 95.112 25.189 ;
     RECT  96.288 24.949 119.352 25.189 ;
     RECT  42.9 24.901 44.376 25.237 ;
     RECT  120.528 25.093 124.392 25.573 ;
     RECT  125.952 24.373 126.912 25.573 ;
     RECT  93.408 25.189 119.352 25.621 ;
     RECT  120.528 25.573 126.912 25.621 ;
     RECT  50.784 24.325 51.912 25.669 ;
     RECT  53.088 25.045 62.952 25.669 ;
     RECT  64.272 24.517 74.28 25.669 ;
     RECT  75.3 25.045 89.112 25.669 ;
     RECT  91.5 24.515 91.812 25.669 ;
     RECT  93.408 25.621 126.912 25.669 ;
     RECT  91.5 25.669 92.04 26.101 ;
     RECT  50.784 25.669 89.112 26.149 ;
     RECT  91.392 26.101 92.04 26.197 ;
     RECT  93.312 25.669 126.912 26.197 ;
     RECT  50.304 26.149 89.112 26.293 ;
     RECT  91.392 26.197 127.896 26.293 ;
     RECT  50.304 26.293 89.4 26.771 ;
     RECT  50.304 26.771 89.208 27.301 ;
     RECT  45.6 2.151 45.912 27.349 ;
     RECT  50.16 27.301 89.208 27.349 ;
     RECT  91.296 26.293 128.184 27.349 ;
     RECT  91.008 27.349 128.184 27.445 ;
     RECT  129.3 2.915 129.612 27.445 ;
     RECT  49.872 27.349 89.208 27.493 ;
     RECT  45.6 27.349 46.344 27.877 ;
     RECT  49.728 27.493 89.208 27.877 ;
     RECT  91.008 27.445 129.612 27.925 ;
     RECT  2.4 2.151 2.712 28.089 ;
     RECT  5.1 2.151 5.412 28.089 ;
     RECT  7.8 2.151 8.112 28.089 ;
     RECT  10.5 2.151 10.812 28.089 ;
     RECT  13.2 2.151 13.512 28.089 ;
     RECT  15.9 2.151 16.212 28.089 ;
     RECT  18.6 2.151 18.912 28.089 ;
     RECT  21.3 2.151 21.612 28.089 ;
     RECT  24 2.151 24.312 28.089 ;
     RECT  26.7 2.151 27.012 28.089 ;
     RECT  29.4 2.151 29.712 28.089 ;
     RECT  32.1 2.151 32.412 28.089 ;
     RECT  34.8 2.151 35.112 28.089 ;
     RECT  37.5 2.151 37.812 28.089 ;
     RECT  40.2 2.151 40.512 28.089 ;
     RECT  90.864 27.925 129.612 28.089 ;
     RECT  132 1.811 132.312 28.089 ;
     RECT  134.7 3.107 135.012 28.089 ;
     RECT  137.4 3.395 137.712 28.089 ;
     RECT  140.1 3.347 140.412 28.089 ;
     RECT  142.8 3.155 143.112 28.089 ;
     RECT  145.5 2.291 145.812 28.089 ;
     RECT  148.2 3.203 148.512 28.089 ;
     RECT  150.9 3.347 151.212 28.089 ;
     RECT  153.6 3.347 153.912 28.089 ;
     RECT  156.3 3.107 156.612 28.089 ;
     RECT  159 3.347 159.312 28.089 ;
     RECT  161.7 2.963 162.012 28.089 ;
     RECT  164.4 3.107 164.712 28.089 ;
     RECT  167.1 3.395 167.412 28.089 ;
     RECT  169.8 4.691 170.112 28.089 ;
     RECT  2.4 28.089 2.52 28.103 ;
     RECT  5.1 28.089 5.22 28.103 ;
     RECT  7.8 28.089 7.92 28.103 ;
     RECT  10.5 28.089 10.62 28.103 ;
     RECT  13.2 28.089 13.32 28.103 ;
     RECT  15.9 28.089 16.02 28.103 ;
     RECT  18.6 28.089 18.72 28.103 ;
     RECT  21.3 28.089 21.42 28.103 ;
     RECT  24 28.089 24.12 28.103 ;
     RECT  26.7 28.089 26.82 28.103 ;
     RECT  29.4 28.089 29.52 28.103 ;
     RECT  32.1 28.089 32.22 28.103 ;
     RECT  34.8 28.089 34.92 28.103 ;
     RECT  37.5 28.089 37.62 28.103 ;
     RECT  40.2 28.089 40.32 28.103 ;
     RECT  45.6 27.877 46.488 28.103 ;
     RECT  48.3 2.151 48.612 28.103 ;
     RECT  90.864 28.089 129.42 28.103 ;
     RECT  132 28.089 132.12 28.103 ;
     RECT  134.7 28.089 134.82 28.103 ;
     RECT  137.4 28.089 137.52 28.103 ;
     RECT  140.1 28.089 140.22 28.103 ;
     RECT  142.8 28.089 142.92 28.103 ;
     RECT  145.5 28.089 145.62 28.103 ;
     RECT  148.2 28.089 148.32 28.103 ;
     RECT  150.9 28.089 151.02 28.103 ;
     RECT  153.6 28.089 153.72 28.103 ;
     RECT  156.3 28.089 156.42 28.103 ;
     RECT  159 28.089 159.12 28.103 ;
     RECT  161.7 28.089 161.82 28.103 ;
     RECT  164.4 28.089 164.52 28.103 ;
     RECT  167.1 28.089 167.22 28.103 ;
     RECT  169.8 28.089 169.92 28.103 ;
     RECT  46.32 28.103 46.488 28.453 ;
     RECT  49.584 27.877 89.208 28.453 ;
     RECT  90.864 28.103 128.472 28.453 ;
     RECT  46.32 28.453 47.496 29.077 ;
     RECT  49.152 28.453 89.208 29.077 ;
     RECT  45.744 29.077 47.496 29.605 ;
     RECT  48.72 29.077 89.208 29.605 ;
     RECT  90.432 28.453 128.472 29.605 ;
     RECT  42.768 25.237 44.376 30.083 ;
     RECT  129.696 29.989 129.72 30.085 ;
     RECT  42.96 30.083 44.376 30.131 ;
     RECT  42.96 30.131 43.128 30.224 ;
     RECT  44.208 30.131 44.376 30.224 ;
     RECT  45.456 29.605 47.496 30.224 ;
     RECT  48.576 29.605 89.208 30.224 ;
     RECT  90.288 29.605 128.472 30.224 ;
     RECT  129.552 30.085 129.72 30.224 ;
     RECT  89.88 0.016 90.864 0.132 ;
     RECT  91.128 0.016 92.112 0.132 ;
     RECT  130.392 0.016 131.376 0.132 ;
     RECT  90.984 0.131 91.008 0.132 ;
     RECT  89.832 0.132 91.056 1.763 ;
     RECT  91.08 0.132 92.16 1.763 ;
     RECT  130.344 0.132 131.424 1.763 ;
     RECT  170.328 1.715 171.312 2.291 ;
     RECT  91.344 1.763 92.16 1.907 ;
     RECT  130.344 1.763 131.568 1.811 ;
     RECT  93.192 1.811 94.2 2.243 ;
     RECT  132.312 1.811 133.296 2.003 ;
     RECT  144.12 1.811 145.104 2.291 ;
     RECT  94.512 1.859 95.616 2.963 ;
     RECT  106.728 1.859 107.7 2.291 ;
     RECT  135.192 1.859 136.176 2.099 ;
     RECT  138.504 1.859 139.632 2.099 ;
     RECT  91.344 1.907 92.88 2.137 ;
     RECT  154.92 1.907 156.048 2.915 ;
     RECT  132.312 2.003 133.728 2.099 ;
     RECT  135.012 2.099 136.176 2.915 ;
     RECT  136.2 2.099 137.4 2.915 ;
     RECT  138.36 2.099 139.632 2.915 ;
     RECT  91.344 2.137 91.5 3.013 ;
     RECT  91.812 2.137 92.88 2.291 ;
     RECT  92.904 2.243 94.2 2.291 ;
     RECT  144.12 2.291 145.5 2.915 ;
     RECT  145.812 2.291 147.264 3.011 ;
     RECT  151.32 2.291 152.448 3.107 ;
     RECT  162.408 2.291 163.536 2.915 ;
     RECT  170.28 2.291 171.312 2.915 ;
     RECT  149.304 2.819 150.288 2.915 ;
     RECT  95.64 2.915 96.9 2.963 ;
     RECT  110.712 2.915 112.176 2.963 ;
     RECT  113.412 2.915 114.912 3.107 ;
     RECT  119.544 2.915 120.528 2.963 ;
     RECT  122.424 2.915 123.9 2.963 ;
     RECT  157.656 2.915 158.784 3.251 ;
     RECT  97.368 2.963 98.496 3.107 ;
     RECT  100.824 2.963 102.144 3.059 ;
     RECT  116.808 2.963 117.936 3.107 ;
     RECT  119.4 2.963 120.528 3.107 ;
     RECT  160.536 2.963 161.7 3.107 ;
     RECT  98.52 3.011 99.6 3.107 ;
     RECT  124.584 3.011 125.856 3.107 ;
     RECT  100.824 3.059 102.192 3.107 ;
     RECT  156.612 3.059 157.632 3.251 ;
     RECT  167.412 3.059 168.432 3.539 ;
     RECT  151.32 3.107 152.736 3.155 ;
     RECT  164.712 3.107 165.696 3.155 ;
     RECT  165.72 3.107 166.992 3.155 ;
     RECT  89.112 3.685 90.432 18.467 ;
     RECT  90.456 4.019 91.5 18.467 ;
     RECT  70.212 21.157 71.232 22.259 ;
     RECT  71.256 21.157 72.6 22.259 ;
     RECT  81.012 21.301 82.272 22.789 ;
     RECT  82.296 21.301 83.4 23.365 ;
     RECT  105.312 21.397 106.656 21.637 ;
     RECT  106.68 21.397 107.7 22.645 ;
     RECT  113.412 21.397 114.528 22.741 ;
     RECT  114.552 21.397 115.8 24.565 ;
     RECT  102.612 21.445 103.632 22.165 ;
     RECT  103.656 21.445 105 24.133 ;
     RECT  54.012 21.637 55.248 23.893 ;
     RECT  55.272 21.637 56.4 23.893 ;
     RECT  105.312 21.637 106.608 23.363 ;
     RECT  108.936 21.973 110.4 22.163 ;
     RECT  121.512 22.117 123.024 22.597 ;
     RECT  108.216 22.163 108.744 23.413 ;
     RECT  70.212 22.259 72.6 22.309 ;
     RECT  71.16 22.309 72.6 23.365 ;
     RECT  78.312 22.645 79.44 23.365 ;
     RECT  79.464 22.645 80.7 23.749 ;
     RECT  116.856 22.693 118.224 24.469 ;
     RECT  75.768 23.029 77.184 23.365 ;
     RECT  97.212 23.173 98.544 23.365 ;
     RECT  60.36 23.317 61.8 23.365 ;
     RECT  105.312 23.363 106.896 23.749 ;
     RECT  51.624 23.365 53.088 24.325 ;
     RECT  71.256 23.365 72.6 23.893 ;
     RECT  78.312 23.365 79.344 24.517 ;
     RECT  100.296 23.413 101.712 23.941 ;
     RECT  43.212 23.557 44.352 24.709 ;
     RECT  44.376 23.557 45.6 28.103 ;
     RECT  105.768 23.749 106.896 24.325 ;
     RECT  87.528 23.797 88.8 24.517 ;
     RECT  71.448 23.893 72.6 24.325 ;
     RECT  74.28 23.893 75.3 25.669 ;
     RECT  103.704 24.133 105 24.469 ;
     RECT  51.912 24.325 53.088 25.669 ;
     RECT  105.768 24.325 106.848 24.949 ;
     RECT  84.072 24.565 85.248 25.045 ;
     RECT  114.744 24.565 115.8 24.901 ;
     RECT  57.432 24.613 58.944 24.805 ;
     RECT  43.32 24.709 44.352 24.901 ;
     RECT  62.952 25.045 64.272 25.669 ;
     RECT  95.112 25.045 96.288 25.189 ;
     RECT  119.352 25.093 120.528 25.621 ;
     RECT  92.04 25.669 93.312 26.197 ;
     RECT  127.896 26.197 129.3 26.293 ;
     RECT  128.184 26.293 129.3 27.445 ;
     RECT  48.612 27.349 49.872 27.493 ;
     RECT  48.612 27.493 49.728 27.877 ;
     RECT  48.612 27.877 49.584 28.103 ;
     RECT  44.376 28.103 46.32 29.077 ;
     RECT  48.3 28.103 49.584 28.453 ;
     RECT  47.496 28.453 49.152 29.077 ;
     RECT  89.208 28.453 90.432 29.605 ;
     RECT  44.376 29.077 45.744 29.605 ;
     RECT  47.496 29.077 48.72 29.605 ;
     RECT  44.376 29.605 45.456 30.108 ;
     RECT  47.496 29.605 48.576 30.108 ;
     RECT  89.208 29.605 90.288 30.108 ;
     RECT  128.472 29.989 129.696 30.085 ;
     RECT  128.472 30.085 129.552 30.108 ;
     RECT  44.424 30.108 45.408 30.224 ;
     RECT  47.544 30.108 48.528 30.224 ;
     RECT  89.256 30.108 90.24 30.224 ;
     RECT  128.52 30.108 129.504 30.224 ;
     RECT  43.176 30.131 44.16 30.224 ;
  END
END dsfd_sstn_e0c0si
END LIBRARY
